VERSION 5.7 ;
  NOWIREEXTENSIONATPIN ON ;
  DIVIDERCHAR "/" ;
  BUSBITCHARS "[]" ;
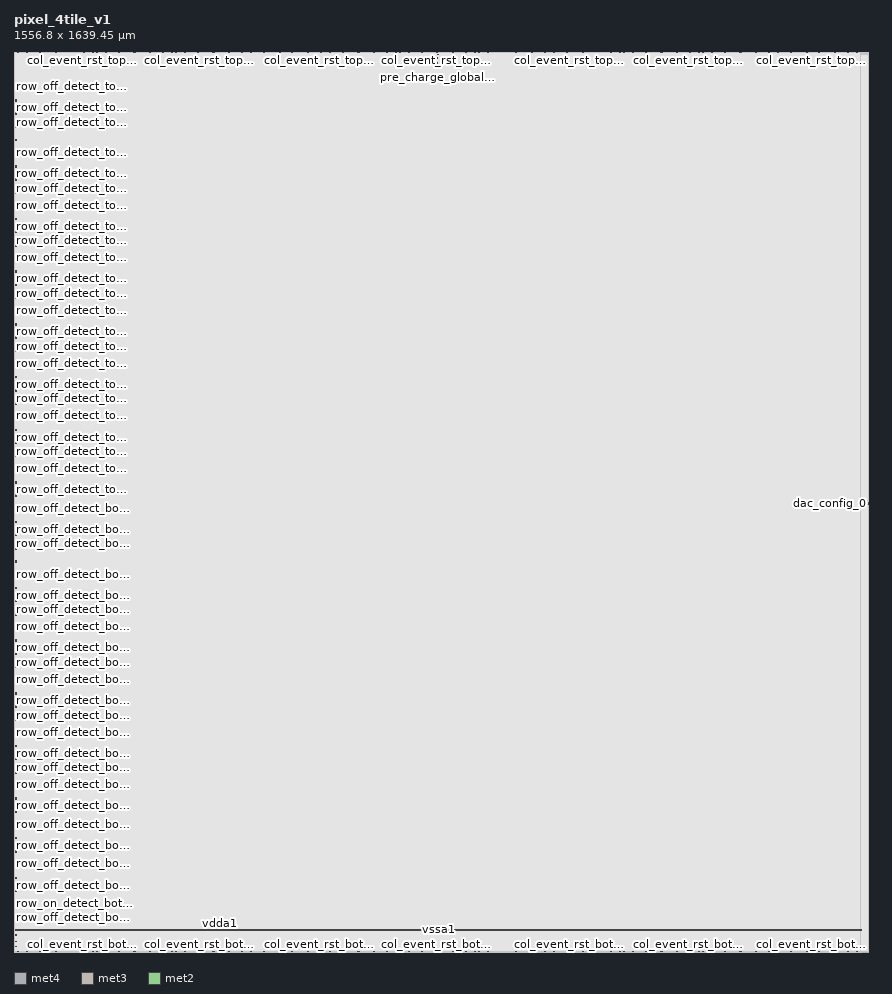
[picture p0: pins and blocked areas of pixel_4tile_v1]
MACRO pixel_4tile_v1
  CLASS BLOCK ;
  FOREIGN pixel_4tile_v1 ;
  ORIGIN 0.775 0.005 ;
  SIZE 1556.795 BY 1639.450 ;
  PIN vdda1
    ANTENNADIFFAREA 30146.603516 ;
    PORT
      LAYER met4 ;
        RECT 368.795 50.390 380.585 52.050 ;
    END
  END vdda1
  PIN dac_config_3
    ANTENNAGATEAREA 1228.799927 ;
    PORT
      LAYER met3 ;
        RECT 1555.525 820.220 1556.020 821.220 ;
    END
  END dac_config_3
  PIN dac_config_5
    ANTENNAGATEAREA 10321.919922 ;
    PORT
      LAYER met3 ;
        RECT 1555.525 821.715 1556.020 822.720 ;
    END
  END dac_config_5
  PIN dac_config_1
    ANTENNAGATEAREA 36864.000000 ;
    PORT
      LAYER met3 ;
        RECT 1555.525 817.220 1556.020 818.220 ;
    END
  END dac_config_1
  PIN dac_config_4
    ANTENNAGATEAREA 10321.919922 ;
    PORT
      LAYER met3 ;
        RECT 1555.525 818.720 1556.020 819.720 ;
    END
  END dac_config_4
  PIN dac_config_0
    ANTENNAGATEAREA 36576.000000 ;
    PORT
      LAYER met3 ;
        RECT 1555.525 815.720 1556.020 816.720 ;
    END
  END dac_config_0
  PIN array_col_bot_left<19>
    ANTENNADIFFAREA 0.870000 ;
    PORT
      LAYER met3 ;
        RECT 534.245 0.125 535.015 0.425 ;
    END
  END array_col_bot_left<19>
  PIN array_col_bot_left<18>
    ANTENNADIFFAREA 0.870000 ;
    PORT
      LAYER met3 ;
        RECT 550.365 0.125 551.135 0.425 ;
    END
  END array_col_bot_left<18>
  PIN array_col_bot_left<17>
    ANTENNADIFFAREA 0.870000 ;
    PORT
      LAYER met3 ;
        RECT 558.245 0.125 559.015 0.425 ;
    END
  END array_col_bot_left<17>
  PIN array_col_bot_left<16>
    ANTENNADIFFAREA 0.870000 ;
    PORT
      LAYER met3 ;
        RECT 574.365 0.125 575.135 0.425 ;
    END
  END array_col_bot_left<16>
  PIN array_col_bot_left<15>
    ANTENNADIFFAREA 0.870000 ;
    PORT
      LAYER met3 ;
        RECT 582.245 0.125 583.015 0.425 ;
    END
  END array_col_bot_left<15>
  PIN array_col_bot_left<6>
    ANTENNADIFFAREA 0.870000 ;
    PORT
      LAYER met3 ;
        RECT 694.365 0.125 695.135 0.425 ;
    END
  END array_col_bot_left<6>
  PIN array_col_top_right<15>
    ANTENNADIFFAREA 0.870000 ;
    PORT
      LAYER met3 ;
        RECT 1350.245 1638.015 1351.015 1638.315 ;
    END
  END array_col_top_right<15>
  PIN array_col_top_right<25>
    ANTENNADIFFAREA 0.870000 ;
    PORT
      LAYER met3 ;
        RECT 1230.245 1638.015 1231.015 1638.315 ;
    END
  END array_col_top_right<25>
  PIN array_col_top_right<14>
    ANTENNADIFFAREA 0.870000 ;
    PORT
      LAYER met3 ;
        RECT 1366.365 1638.015 1367.135 1638.315 ;
    END
  END array_col_top_right<14>
  PIN array_col_top_right<27>
    ANTENNADIFFAREA 0.870000 ;
    PORT
      LAYER met3 ;
        RECT 1206.245 1638.015 1207.015 1638.315 ;
    END
  END array_col_top_right<27>
  PIN array_col_top_right<21>
    ANTENNADIFFAREA 0.870000 ;
    PORT
      LAYER met3 ;
        RECT 1278.245 1638.015 1279.015 1638.315 ;
    END
  END array_col_top_right<21>
  PIN array_col_bot_left<63>
    ANTENNADIFFAREA 0.870000 ;
    PORT
      LAYER met3 ;
        RECT 6.245 0.125 7.015 0.425 ;
    END
  END array_col_bot_left<63>
  PIN array_col_bot_left<1>
    ANTENNADIFFAREA 0.870000 ;
    PORT
      LAYER met3 ;
        RECT 750.245 0.125 751.015 0.425 ;
    END
  END array_col_bot_left<1>
  PIN array_col_bot_left<4>
    ANTENNADIFFAREA 0.870000 ;
    PORT
      LAYER met3 ;
        RECT 718.365 0.125 719.135 0.425 ;
    END
  END array_col_bot_left<4>
  PIN col_event_rst_bot_left<53>
    ANTENNAGATEAREA 4.032000 ;
    PORT
      LAYER met3 ;
        RECT 123.500 0.245 123.800 0.545 ;
    END
  END col_event_rst_bot_left<53>
  PIN array_col_bot_right<50>
    ANTENNADIFFAREA 0.870000 ;
    PORT
      LAYER met3 ;
        RECT 934.365 0.125 935.135 0.425 ;
    END
  END array_col_bot_right<50>
  PIN col_event_rst_bot_left<47>
    ANTENNAGATEAREA 4.032000 ;
    PORT
      LAYER met3 ;
        RECT 195.500 0.245 195.800 0.545 ;
    END
  END col_event_rst_bot_left<47>
  PIN col_event_rst_top_left<62>
    ANTENNAGATEAREA 4.032000 ;
    PORT
      LAYER met3 ;
        RECT 25.595 1637.895 25.895 1638.195 ;
    END
  END col_event_rst_top_left<62>
  PIN array_col_bot_left<0>
    ANTENNADIFFAREA 0.870000 ;
    PORT
      LAYER met3 ;
        RECT 766.365 0.125 767.135 0.425 ;
    END
  END array_col_bot_left<0>
  PIN col_event_rst_bot_left<5>
    ANTENNAGATEAREA 4.032000 ;
    PORT
      LAYER met3 ;
        RECT 699.500 0.245 699.800 0.545 ;
    END
  END col_event_rst_bot_left<5>
  PIN col_event_rst_bot_left<6>
    ANTENNAGATEAREA 4.032000 ;
    PORT
      LAYER met3 ;
        RECT 697.595 0.245 697.895 0.545 ;
    END
  END col_event_rst_bot_left<6>
  PIN col_event_rst_bot_left<9>
    ANTENNAGATEAREA 4.032000 ;
    PORT
      LAYER met3 ;
        RECT 651.500 0.245 651.800 0.545 ;
    END
  END col_event_rst_bot_left<9>
  PIN col_event_rst_bot_left<10>
    ANTENNAGATEAREA 4.032000 ;
    PORT
      LAYER met3 ;
        RECT 649.595 0.245 649.895 0.545 ;
    END
  END col_event_rst_bot_left<10>
  PIN col_event_rst_bot_left<13>
    ANTENNAGATEAREA 4.032000 ;
    PORT
      LAYER met3 ;
        RECT 603.500 0.245 603.800 0.545 ;
    END
  END col_event_rst_bot_left<13>
  PIN array_col_bot_left<50>
    ANTENNADIFFAREA 0.870000 ;
    PORT
      LAYER met3 ;
        RECT 166.365 0.125 167.135 0.425 ;
    END
  END array_col_bot_left<50>
  PIN col_event_rst_bot_left<14>
    ANTENNAGATEAREA 4.032000 ;
    PORT
      LAYER met3 ;
        RECT 601.595 0.245 601.895 0.545 ;
    END
  END col_event_rst_bot_left<14>
  PIN col_event_rst_bot_left<15>
    ANTENNAGATEAREA 4.032000 ;
    PORT
      LAYER met3 ;
        RECT 579.500 0.245 579.800 0.545 ;
    END
  END col_event_rst_bot_left<15>
  PIN col_event_rst_bot_left<18>
    ANTENNAGATEAREA 4.032000 ;
    PORT
      LAYER met3 ;
        RECT 553.595 0.245 553.895 0.545 ;
    END
  END col_event_rst_bot_left<18>
  PIN col_event_rst_bot_left<19>
    ANTENNAGATEAREA 4.032000 ;
    PORT
      LAYER met3 ;
        RECT 531.500 0.245 531.800 0.545 ;
    END
  END col_event_rst_bot_left<19>
  PIN col_event_rst_bot_left<22>
    ANTENNAGATEAREA 4.032000 ;
    PORT
      LAYER met3 ;
        RECT 505.595 0.245 505.895 0.545 ;
    END
  END col_event_rst_bot_left<22>
  PIN col_event_rst_top_right<47>
    ANTENNAGATEAREA 4.032000 ;
    PORT
      LAYER met3 ;
        RECT 963.500 1637.895 963.800 1638.195 ;
    END
  END col_event_rst_top_right<47>
  PIN col_event_rst_top_right<49>
    ANTENNAGATEAREA 4.032000 ;
    PORT
      LAYER met3 ;
        RECT 939.500 1637.895 939.800 1638.195 ;
    END
  END col_event_rst_top_right<49>
  PIN col_event_rst_bot_left<24>
    ANTENNAGATEAREA 4.032000 ;
    PORT
      LAYER met3 ;
        RECT 481.595 0.245 481.895 0.545 ;
    END
  END col_event_rst_bot_left<24>
  PIN col_event_rst_bot_left<27>
    ANTENNAGATEAREA 4.032000 ;
    PORT
      LAYER met3 ;
        RECT 435.500 0.245 435.800 0.545 ;
    END
  END col_event_rst_bot_left<27>
  PIN col_event_rst_bot_left<28>
    ANTENNAGATEAREA 4.032000 ;
    PORT
      LAYER met3 ;
        RECT 433.595 0.245 433.895 0.545 ;
    END
  END col_event_rst_bot_left<28>
  PIN array_col_bot_left<47>
    ANTENNADIFFAREA 0.870000 ;
    PORT
      LAYER met3 ;
        RECT 198.245 0.125 199.015 0.425 ;
    END
  END array_col_bot_left<47>
  PIN col_event_rst_bot_left<31>
    ANTENNAGATEAREA 4.032000 ;
    PORT
      LAYER met3 ;
        RECT 387.500 0.245 387.800 0.545 ;
    END
  END col_event_rst_bot_left<31>
  PIN col_event_rst_bot_left<33>
    ANTENNAGATEAREA 4.032000 ;
    PORT
      LAYER met3 ;
        RECT 363.500 0.245 363.800 0.545 ;
    END
  END col_event_rst_bot_left<33>
  PIN col_event_rst_top_right<50>
    ANTENNAGATEAREA 4.032000 ;
    PORT
      LAYER met3 ;
        RECT 937.595 1637.895 937.895 1638.195 ;
    END
  END col_event_rst_top_right<50>
  PIN col_event_rst_bot_left<36>
    ANTENNAGATEAREA 4.032000 ;
    PORT
      LAYER met3 ;
        RECT 337.595 0.245 337.895 0.545 ;
    END
  END col_event_rst_bot_left<36>
  PIN col_event_rst_bot_left<37>
    ANTENNAGATEAREA 4.032000 ;
    PORT
      LAYER met3 ;
        RECT 315.500 0.245 315.800 0.545 ;
    END
  END col_event_rst_bot_left<37>
  PIN col_event_rst_bot_left<39>
    ANTENNAGATEAREA 4.032000 ;
    PORT
      LAYER met3 ;
        RECT 291.500 0.245 291.800 0.545 ;
    END
  END col_event_rst_bot_left<39>
  PIN col_event_rst_bot_left<40>
    ANTENNAGATEAREA 4.032000 ;
    PORT
      LAYER met3 ;
        RECT 289.595 0.245 289.895 0.545 ;
    END
  END col_event_rst_bot_left<40>
  PIN col_event_rst_bot_left<42>
    ANTENNAGATEAREA 4.032000 ;
    PORT
      LAYER met3 ;
        RECT 265.595 0.245 265.895 0.545 ;
    END
  END col_event_rst_bot_left<42>
  PIN col_event_rst_bot_left<43>
    ANTENNAGATEAREA 4.032000 ;
    PORT
      LAYER met3 ;
        RECT 243.500 0.245 243.800 0.545 ;
    END
  END col_event_rst_bot_left<43>
  PIN col_event_rst_top_right<51>
    ANTENNAGATEAREA 4.032000 ;
    PORT
      LAYER met3 ;
        RECT 915.500 1637.895 915.800 1638.195 ;
    END
  END col_event_rst_top_right<51>
  PIN col_event_rst_top_left<58>
    ANTENNAGATEAREA 4.032000 ;
    PORT
      LAYER met3 ;
        RECT 73.595 1637.895 73.895 1638.195 ;
    END
  END col_event_rst_top_left<58>
  PIN array_col_top_right<26>
    ANTENNADIFFAREA 0.870000 ;
    PORT
      LAYER met3 ;
        RECT 1222.365 1638.015 1223.135 1638.315 ;
    END
  END array_col_top_right<26>
  PIN col_event_rst_top_right<43>
    ANTENNAGATEAREA 4.032000 ;
    PORT
      LAYER met3 ;
        RECT 1011.500 1637.895 1011.800 1638.195 ;
    END
  END col_event_rst_top_right<43>
  PIN array_col_top_right<1>
    ANTENNADIFFAREA 0.870000 ;
    PORT
      LAYER met3 ;
        RECT 1518.245 1638.015 1519.015 1638.315 ;
    END
  END array_col_top_right<1>
  PIN array_col_top_right<2>
    ANTENNADIFFAREA 0.870000 ;
    PORT
      LAYER met3 ;
        RECT 1510.365 1638.015 1511.135 1638.315 ;
    END
  END array_col_top_right<2>
  PIN col_event_rst_top_left<44>
    ANTENNAGATEAREA 4.032000 ;
    PORT
      LAYER met3 ;
        RECT 241.595 1637.895 241.895 1638.195 ;
    END
  END col_event_rst_top_left<44>
  PIN array_col_top_right<12>
    ANTENNADIFFAREA 0.870000 ;
    PORT
      LAYER met3 ;
        RECT 1390.365 1638.015 1391.135 1638.315 ;
    END
  END array_col_top_right<12>
  PIN col_event_rst_bot_left<49>
    ANTENNAGATEAREA 4.032000 ;
    PORT
      LAYER met3 ;
        RECT 171.500 0.245 171.800 0.545 ;
    END
  END col_event_rst_bot_left<49>
  PIN col_event_rst_bot_left<48>
    ANTENNAGATEAREA 4.032000 ;
    PORT
      LAYER met3 ;
        RECT 193.595 0.245 193.895 0.545 ;
    END
  END col_event_rst_bot_left<48>
  PIN array_col_top_right<30>
    ANTENNADIFFAREA 0.870000 ;
    PORT
      LAYER met3 ;
        RECT 1174.365 1638.015 1175.135 1638.315 ;
    END
  END array_col_top_right<30>
  PIN array_col_top_right<29>
    ANTENNADIFFAREA 0.870000 ;
    PORT
      LAYER met3 ;
        RECT 1182.245 1638.015 1183.015 1638.315 ;
    END
  END array_col_top_right<29>
  PIN array_col_top_right<28>
    ANTENNADIFFAREA 0.870000 ;
    PORT
      LAYER met3 ;
        RECT 1198.365 1638.015 1199.135 1638.315 ;
    END
  END array_col_top_right<28>
  PIN array_col_bot_left<2>
    ANTENNADIFFAREA 0.870000 ;
    PORT
      LAYER met3 ;
        RECT 742.365 0.125 743.135 0.425 ;
    END
  END array_col_bot_left<2>
  PIN array_col_bot_left<3>
    ANTENNADIFFAREA 0.870000 ;
    PORT
      LAYER met3 ;
        RECT 726.245 0.125 727.015 0.425 ;
    END
  END array_col_bot_left<3>
  PIN col_event_rst_top_left<50>
    ANTENNAGATEAREA 4.032000 ;
    PORT
      LAYER met3 ;
        RECT 169.595 1637.895 169.895 1638.195 ;
    END
  END col_event_rst_top_left<50>
  PIN array_col_bot_left<5>
    ANTENNADIFFAREA 0.870000 ;
    PORT
      LAYER met3 ;
        RECT 702.245 0.125 703.015 0.425 ;
    END
  END array_col_bot_left<5>
  PIN array_col_bot_left<46>
    ANTENNADIFFAREA 0.870000 ;
    PORT
      LAYER met3 ;
        RECT 214.365 0.125 215.135 0.425 ;
    END
  END array_col_bot_left<46>
  PIN col_event_rst_top_left<61>
    ANTENNAGATEAREA 4.032000 ;
    PORT
      LAYER met3 ;
        RECT 27.500 1637.895 27.800 1638.195 ;
    END
  END col_event_rst_top_left<61>
  PIN array_col_top_right<16>
    ANTENNADIFFAREA 0.870000 ;
    PORT
      LAYER met3 ;
        RECT 1342.365 1638.015 1343.135 1638.315 ;
    END
  END array_col_top_right<16>
  PIN col_event_rst_bot_left<2>
    ANTENNAGATEAREA 4.032000 ;
    PORT
      LAYER met3 ;
        RECT 745.595 0.245 745.895 0.545 ;
    END
  END col_event_rst_bot_left<2>
  PIN col_event_rst_bot_left<7>
    ANTENNAGATEAREA 4.032000 ;
    PORT
      LAYER met3 ;
        RECT 675.500 0.245 675.800 0.545 ;
    END
  END col_event_rst_bot_left<7>
  PIN col_event_rst_bot_left<8>
    ANTENNAGATEAREA 4.032000 ;
    PORT
      LAYER met3 ;
        RECT 673.595 0.245 673.895 0.545 ;
    END
  END col_event_rst_bot_left<8>
  PIN col_event_rst_bot_left<11>
    ANTENNAGATEAREA 4.032000 ;
    PORT
      LAYER met3 ;
        RECT 627.500 0.245 627.800 0.545 ;
    END
  END col_event_rst_bot_left<11>
  PIN col_event_rst_bot_left<12>
    ANTENNAGATEAREA 4.032000 ;
    PORT
      LAYER met3 ;
        RECT 625.595 0.245 625.895 0.545 ;
    END
  END col_event_rst_bot_left<12>
  PIN col_event_rst_bot_left<3>
    ANTENNAGATEAREA 4.032000 ;
    PORT
      LAYER met3 ;
        RECT 723.500 0.245 723.800 0.545 ;
    END
  END col_event_rst_bot_left<3>
  PIN col_event_rst_top_right<48>
    ANTENNAGATEAREA 4.032000 ;
    PORT
      LAYER met3 ;
        RECT 961.595 1637.895 961.895 1638.195 ;
    END
  END col_event_rst_top_right<48>
  PIN col_event_rst_bot_left<16>
    ANTENNAGATEAREA 4.032000 ;
    PORT
      LAYER met3 ;
        RECT 577.595 0.245 577.895 0.545 ;
    END
  END col_event_rst_bot_left<16>
  PIN col_event_rst_bot_left<17>
    ANTENNAGATEAREA 4.032000 ;
    PORT
      LAYER met3 ;
        RECT 555.500 0.245 555.800 0.545 ;
    END
  END col_event_rst_bot_left<17>
  PIN col_event_rst_bot_left<20>
    ANTENNAGATEAREA 4.032000 ;
    PORT
      LAYER met3 ;
        RECT 529.595 0.245 529.895 0.545 ;
    END
  END col_event_rst_bot_left<20>
  PIN col_event_rst_bot_left<21>
    ANTENNAGATEAREA 4.032000 ;
    PORT
      LAYER met3 ;
        RECT 507.500 0.245 507.800 0.545 ;
    END
  END col_event_rst_bot_left<21>
  PIN col_event_rst_top_left<55>
    ANTENNAGATEAREA 4.032000 ;
    PORT
      LAYER met3 ;
        RECT 99.500 1637.895 99.800 1638.195 ;
    END
  END col_event_rst_top_left<55>
  PIN col_event_rst_bot_left<23>
    ANTENNAGATEAREA 4.032000 ;
    PORT
      LAYER met3 ;
        RECT 483.500 0.245 483.800 0.545 ;
    END
  END col_event_rst_bot_left<23>
  PIN col_event_rst_bot_left<25>
    ANTENNAGATEAREA 4.032000 ;
    PORT
      LAYER met3 ;
        RECT 459.500 0.245 459.800 0.545 ;
    END
  END col_event_rst_bot_left<25>
  PIN col_event_rst_bot_left<26>
    ANTENNAGATEAREA 4.032000 ;
    PORT
      LAYER met3 ;
        RECT 457.595 0.245 457.895 0.545 ;
    END
  END col_event_rst_bot_left<26>
  PIN col_event_rst_bot_left<29>
    ANTENNAGATEAREA 4.032000 ;
    PORT
      LAYER met3 ;
        RECT 411.500 0.245 411.800 0.545 ;
    END
  END col_event_rst_bot_left<29>
  PIN col_event_rst_bot_left<30>
    ANTENNAGATEAREA 4.032000 ;
    PORT
      LAYER met3 ;
        RECT 409.595 0.245 409.895 0.545 ;
    END
  END col_event_rst_bot_left<30>
  PIN col_event_rst_top_left<56>
    ANTENNAGATEAREA 4.032000 ;
    PORT
      LAYER met3 ;
        RECT 97.595 1637.895 97.895 1638.195 ;
    END
  END col_event_rst_top_left<56>
  PIN col_event_rst_bot_left<32>
    ANTENNAGATEAREA 4.032000 ;
    PORT
      LAYER met3 ;
        RECT 385.595 0.245 385.895 0.545 ;
    END
  END col_event_rst_bot_left<32>
  PIN col_event_rst_bot_left<34>
    ANTENNAGATEAREA 4.032000 ;
    PORT
      LAYER met3 ;
        RECT 361.595 0.245 361.895 0.545 ;
    END
  END col_event_rst_bot_left<34>
  PIN col_event_rst_bot_left<35>
    ANTENNAGATEAREA 4.032000 ;
    PORT
      LAYER met3 ;
        RECT 339.500 0.245 339.800 0.545 ;
    END
  END col_event_rst_bot_left<35>
  PIN col_event_rst_bot_left<38>
    ANTENNAGATEAREA 4.032000 ;
    PORT
      LAYER met3 ;
        RECT 313.595 0.245 313.895 0.545 ;
    END
  END col_event_rst_bot_left<38>
  PIN col_event_rst_bot_left<4>
    ANTENNAGATEAREA 4.032000 ;
    PORT
      LAYER met3 ;
        RECT 721.595 0.245 721.895 0.545 ;
    END
  END col_event_rst_bot_left<4>
  PIN col_event_rst_top_left<57>
    ANTENNAGATEAREA 4.032000 ;
    PORT
      LAYER met3 ;
        RECT 75.500 1637.895 75.800 1638.195 ;
    END
  END col_event_rst_top_left<57>
  PIN col_event_rst_bot_left<41>
    ANTENNAGATEAREA 4.032000 ;
    PORT
      LAYER met3 ;
        RECT 267.500 0.245 267.800 0.545 ;
    END
  END col_event_rst_bot_left<41>
  PIN array_col_bot_right<51>
    ANTENNADIFFAREA 0.870000 ;
    PORT
      LAYER met3 ;
        RECT 918.245 0.125 919.015 0.425 ;
    END
  END array_col_bot_right<51>
  PIN col_event_rst_top_right<55>
    ANTENNAGATEAREA 4.032000 ;
    PORT
      LAYER met3 ;
        RECT 867.500 1637.895 867.800 1638.195 ;
    END
  END col_event_rst_top_right<55>
  PIN col_event_rst_top_right<54>
    ANTENNAGATEAREA 4.032000 ;
    PORT
      LAYER met3 ;
        RECT 889.595 1637.895 889.895 1638.195 ;
    END
  END col_event_rst_top_right<54>
  PIN col_event_rst_top_right<42>
    ANTENNAGATEAREA 4.032000 ;
    PORT
      LAYER met3 ;
        RECT 1033.595 1637.895 1033.895 1638.195 ;
    END
  END col_event_rst_top_right<42>
  PIN col_event_rst_top_right<41>
    ANTENNAGATEAREA 4.032000 ;
    PORT
      LAYER met3 ;
        RECT 1035.500 1637.895 1035.800 1638.195 ;
    END
  END col_event_rst_top_right<41>
  PIN col_event_rst_top_right<40>
    ANTENNAGATEAREA 4.032000 ;
    PORT
      LAYER met3 ;
        RECT 1057.595 1637.895 1057.895 1638.195 ;
    END
  END col_event_rst_top_right<40>
  PIN col_event_rst_top_right<39>
    ANTENNAGATEAREA 4.032000 ;
    PORT
      LAYER met3 ;
        RECT 1059.500 1637.895 1059.800 1638.195 ;
    END
  END col_event_rst_top_right<39>
  PIN col_event_rst_top_right<53>
    ANTENNAGATEAREA 4.032000 ;
    PORT
      LAYER met3 ;
        RECT 891.500 1637.895 891.800 1638.195 ;
    END
  END col_event_rst_top_right<53>
  PIN col_event_rst_top_right<38>
    ANTENNAGATEAREA 4.032000 ;
    PORT
      LAYER met3 ;
        RECT 1081.595 1637.895 1081.895 1638.195 ;
    END
  END col_event_rst_top_right<38>
  PIN col_event_rst_top_right<37>
    ANTENNAGATEAREA 4.032000 ;
    PORT
      LAYER met3 ;
        RECT 1083.500 1637.895 1083.800 1638.195 ;
    END
  END col_event_rst_top_right<37>
  PIN col_event_rst_top_right<36>
    ANTENNAGATEAREA 4.032000 ;
    PORT
      LAYER met3 ;
        RECT 1105.595 1637.895 1105.895 1638.195 ;
    END
  END col_event_rst_top_right<36>
  PIN col_event_rst_top_right<35>
    ANTENNAGATEAREA 4.032000 ;
    PORT
      LAYER met3 ;
        RECT 1107.500 1637.895 1107.800 1638.195 ;
    END
  END col_event_rst_top_right<35>
  PIN col_event_rst_top_right<34>
    ANTENNAGATEAREA 4.032000 ;
    PORT
      LAYER met3 ;
        RECT 1129.595 1637.895 1129.895 1638.195 ;
    END
  END col_event_rst_top_right<34>
  PIN col_event_rst_top_right<33>
    ANTENNAGATEAREA 4.032000 ;
    PORT
      LAYER met3 ;
        RECT 1131.500 1637.895 1131.800 1638.195 ;
    END
  END col_event_rst_top_right<33>
  PIN array_col_bot_right<55>
    ANTENNADIFFAREA 0.870000 ;
    PORT
      LAYER met3 ;
        RECT 870.245 0.125 871.015 0.425 ;
    END
  END array_col_bot_right<55>
  PIN col_event_rst_top_right<32>
    ANTENNAGATEAREA 4.032000 ;
    PORT
      LAYER met3 ;
        RECT 1153.595 1637.895 1153.895 1638.195 ;
    END
  END col_event_rst_top_right<32>
  PIN array_col_bot_right<63>
    ANTENNADIFFAREA 0.870000 ;
    PORT
      LAYER met3 ;
        RECT 774.245 0.125 775.015 0.425 ;
    END
  END array_col_bot_right<63>
  PIN array_col_bot_right<0>
    ANTENNADIFFAREA 0.870000 ;
    PORT
      LAYER met3 ;
        RECT 1534.365 0.125 1535.135 0.425 ;
    END
  END array_col_bot_right<0>
  PIN array_col_top_right<3>
    ANTENNADIFFAREA 0.870000 ;
    PORT
      LAYER met3 ;
        RECT 1494.245 1638.015 1495.015 1638.315 ;
    END
  END array_col_top_right<3>
  PIN array_col_top_right<4>
    ANTENNADIFFAREA 0.870000 ;
    PORT
      LAYER met3 ;
        RECT 1486.365 1638.015 1487.135 1638.315 ;
    END
  END array_col_top_right<4>
  PIN array_col_top_right<13>
    ANTENNADIFFAREA 0.870000 ;
    PORT
      LAYER met3 ;
        RECT 1374.245 1638.015 1375.015 1638.315 ;
    END
  END array_col_top_right<13>
  PIN col_event_rst_top_right<31>
    ANTENNAGATEAREA 4.032000 ;
    PORT
      LAYER met3 ;
        RECT 1155.500 1637.895 1155.800 1638.195 ;
    END
  END col_event_rst_top_right<31>
  PIN col_event_rst_top_right<30>
    ANTENNAGATEAREA 4.032000 ;
    PORT
      LAYER met3 ;
        RECT 1177.595 1637.895 1177.895 1638.195 ;
    END
  END col_event_rst_top_right<30>
  PIN col_event_rst_top_right<52>
    ANTENNAGATEAREA 4.032000 ;
    PORT
      LAYER met3 ;
        RECT 913.595 1637.895 913.895 1638.195 ;
    END
  END col_event_rst_top_right<52>
  PIN col_event_rst_top_right<29>
    ANTENNAGATEAREA 4.032000 ;
    PORT
      LAYER met3 ;
        RECT 1179.500 1637.895 1179.800 1638.195 ;
    END
  END col_event_rst_top_right<29>
  PIN col_event_rst_top_right<28>
    ANTENNAGATEAREA 4.032000 ;
    PORT
      LAYER met3 ;
        RECT 1201.595 1637.895 1201.895 1638.195 ;
    END
  END col_event_rst_top_right<28>
  PIN col_event_rst_top_right<27>
    ANTENNAGATEAREA 4.032000 ;
    PORT
      LAYER met3 ;
        RECT 1203.500 1637.895 1203.800 1638.195 ;
    END
  END col_event_rst_top_right<27>
  PIN col_event_rst_top_right<26>
    ANTENNAGATEAREA 4.032000 ;
    PORT
      LAYER met3 ;
        RECT 1225.595 1637.895 1225.895 1638.195 ;
    END
  END col_event_rst_top_right<26>
  PIN col_event_rst_top_right<25>
    ANTENNAGATEAREA 4.032000 ;
    PORT
      LAYER met3 ;
        RECT 1227.500 1637.895 1227.800 1638.195 ;
    END
  END col_event_rst_top_right<25>
  PIN col_event_rst_top_right<24>
    ANTENNAGATEAREA 4.032000 ;
    PORT
      LAYER met3 ;
        RECT 1249.595 1637.895 1249.895 1638.195 ;
    END
  END col_event_rst_top_right<24>
  PIN col_event_rst_top_right<23>
    ANTENNAGATEAREA 4.032000 ;
    PORT
      LAYER met3 ;
        RECT 1251.500 1637.895 1251.800 1638.195 ;
    END
  END col_event_rst_top_right<23>
  PIN array_col_bot_right<54>
    ANTENNADIFFAREA 0.870000 ;
    PORT
      LAYER met3 ;
        RECT 886.365 0.125 887.135 0.425 ;
    END
  END array_col_bot_right<54>
  PIN col_event_rst_top_right<22>
    ANTENNAGATEAREA 4.032000 ;
    PORT
      LAYER met3 ;
        RECT 1273.595 1637.895 1273.895 1638.195 ;
    END
  END col_event_rst_top_right<22>
  PIN col_event_rst_top_right<21>
    ANTENNAGATEAREA 4.032000 ;
    PORT
      LAYER met3 ;
        RECT 1275.500 1637.895 1275.800 1638.195 ;
    END
  END col_event_rst_top_right<21>
  PIN col_event_rst_top_left<42>
    ANTENNAGATEAREA 4.032000 ;
    PORT
      LAYER met3 ;
        RECT 265.595 1637.895 265.895 1638.195 ;
    END
  END col_event_rst_top_left<42>
  PIN col_event_rst_top_right<20>
    ANTENNAGATEAREA 4.032000 ;
    PORT
      LAYER met3 ;
        RECT 1297.595 1637.895 1297.895 1638.195 ;
    END
  END col_event_rst_top_right<20>
  PIN col_event_rst_top_right<19>
    ANTENNAGATEAREA 4.032000 ;
    PORT
      LAYER met3 ;
        RECT 1299.500 1637.895 1299.800 1638.195 ;
    END
  END col_event_rst_top_right<19>
  PIN col_event_rst_top_right<18>
    ANTENNAGATEAREA 4.032000 ;
    PORT
      LAYER met3 ;
        RECT 1321.595 1637.895 1321.895 1638.195 ;
    END
  END col_event_rst_top_right<18>
  PIN col_event_rst_top_right<17>
    ANTENNAGATEAREA 4.032000 ;
    PORT
      LAYER met3 ;
        RECT 1323.500 1637.895 1323.800 1638.195 ;
    END
  END col_event_rst_top_right<17>
  PIN col_event_rst_top_right<16>
    ANTENNAGATEAREA 4.032000 ;
    PORT
      LAYER met3 ;
        RECT 1345.595 1637.895 1345.895 1638.195 ;
    END
  END col_event_rst_top_right<16>
  PIN col_event_rst_top_right<15>
    ANTENNAGATEAREA 4.032000 ;
    PORT
      LAYER met3 ;
        RECT 1347.500 1637.895 1347.800 1638.195 ;
    END
  END col_event_rst_top_right<15>
  PIN col_event_rst_top_right<14>
    ANTENNAGATEAREA 4.032000 ;
    PORT
      LAYER met3 ;
        RECT 1369.595 1637.895 1369.895 1638.195 ;
    END
  END col_event_rst_top_right<14>
  PIN col_event_rst_top_right<13>
    ANTENNAGATEAREA 4.032000 ;
    PORT
      LAYER met3 ;
        RECT 1371.500 1637.895 1371.800 1638.195 ;
    END
  END col_event_rst_top_right<13>
  PIN array_col_bot_right<53>
    ANTENNADIFFAREA 0.870000 ;
    PORT
      LAYER met3 ;
        RECT 894.245 0.125 895.015 0.425 ;
    END
  END array_col_bot_right<53>
  PIN col_event_rst_top_right<12>
    ANTENNAGATEAREA 4.032000 ;
    PORT
      LAYER met3 ;
        RECT 1393.595 1637.895 1393.895 1638.195 ;
    END
  END col_event_rst_top_right<12>
  PIN col_event_rst_bot_left<46>
    ANTENNAGATEAREA 4.032000 ;
    PORT
      LAYER met3 ;
        RECT 217.595 0.245 217.895 0.545 ;
    END
  END col_event_rst_bot_left<46>
  PIN col_event_rst_top_right<11>
    ANTENNAGATEAREA 4.032000 ;
    PORT
      LAYER met3 ;
        RECT 1395.500 1637.895 1395.800 1638.195 ;
    END
  END col_event_rst_top_right<11>
  PIN col_event_rst_top_right<10>
    ANTENNAGATEAREA 4.032000 ;
    PORT
      LAYER met3 ;
        RECT 1417.595 1637.895 1417.895 1638.195 ;
    END
  END col_event_rst_top_right<10>
  PIN col_event_rst_top_right<9>
    ANTENNAGATEAREA 4.032000 ;
    PORT
      LAYER met3 ;
        RECT 1419.500 1637.895 1419.800 1638.195 ;
    END
  END col_event_rst_top_right<9>
  PIN col_event_rst_top_right<8>
    ANTENNAGATEAREA 4.032000 ;
    PORT
      LAYER met3 ;
        RECT 1441.595 1637.895 1441.895 1638.195 ;
    END
  END col_event_rst_top_right<8>
  PIN col_event_rst_top_right<7>
    ANTENNAGATEAREA 4.032000 ;
    PORT
      LAYER met3 ;
        RECT 1443.500 1637.895 1443.800 1638.195 ;
    END
  END col_event_rst_top_right<7>
  PIN col_event_rst_top_right<6>
    ANTENNAGATEAREA 4.032000 ;
    PORT
      LAYER met3 ;
        RECT 1465.595 1637.895 1465.895 1638.195 ;
    END
  END col_event_rst_top_right<6>
  PIN col_event_rst_top_right<5>
    ANTENNAGATEAREA 4.032000 ;
    PORT
      LAYER met3 ;
        RECT 1467.500 1637.895 1467.800 1638.195 ;
    END
  END col_event_rst_top_right<5>
  PIN col_event_rst_top_right<4>
    ANTENNAGATEAREA 4.032000 ;
    PORT
      LAYER met3 ;
        RECT 1489.595 1637.895 1489.895 1638.195 ;
    END
  END col_event_rst_top_right<4>
  PIN col_event_rst_top_right<3>
    ANTENNAGATEAREA 4.032000 ;
    PORT
      LAYER met3 ;
        RECT 1491.500 1637.895 1491.800 1638.195 ;
    END
  END col_event_rst_top_right<3>
  PIN array_col_bot_right<52>
    ANTENNADIFFAREA 0.870000 ;
    PORT
      LAYER met3 ;
        RECT 910.365 0.125 911.135 0.425 ;
    END
  END array_col_bot_right<52>
  PIN col_event_rst_bot_left<45>
    ANTENNAGATEAREA 4.032000 ;
    PORT
      LAYER met3 ;
        RECT 219.500 0.245 219.800 0.545 ;
    END
  END col_event_rst_bot_left<45>
  PIN col_event_rst_top_right<2>
    ANTENNAGATEAREA 4.032000 ;
    PORT
      LAYER met3 ;
        RECT 1513.595 1637.895 1513.895 1638.195 ;
    END
  END col_event_rst_top_right<2>
  PIN col_event_rst_top_right<1>
    ANTENNAGATEAREA 4.032000 ;
    PORT
      LAYER met3 ;
        RECT 1515.500 1637.895 1515.800 1638.195 ;
    END
  END col_event_rst_top_right<1>
  PIN col_event_rst_top_right<63>
    ANTENNAGATEAREA 4.032000 ;
    PORT
      LAYER met3 ;
        RECT 771.500 1635.225 771.800 1635.525 ;
    END
  END col_event_rst_top_right<63>
  PIN col_event_rst_top_right<0>
    ANTENNAGATEAREA 4.032000 ;
    PORT
      LAYER met3 ;
        RECT 1537.595 1637.895 1537.895 1638.195 ;
    END
  END col_event_rst_top_right<0>
  PIN array_col_bot_right<62>
    ANTENNADIFFAREA 0.870000 ;
    PORT
      LAYER met3 ;
        RECT 790.365 0.125 791.135 0.425 ;
    END
  END array_col_bot_right<62>
  PIN array_col_bot_right<61>
    ANTENNADIFFAREA 0.870000 ;
    PORT
      LAYER met3 ;
        RECT 798.245 0.125 799.015 0.425 ;
    END
  END array_col_bot_right<61>
  PIN array_col_bot_right<60>
    ANTENNADIFFAREA 0.870000 ;
    PORT
      LAYER met3 ;
        RECT 814.365 0.125 815.135 0.425 ;
    END
  END array_col_bot_right<60>
  PIN array_col_bot_right<59>
    ANTENNADIFFAREA 0.870000 ;
    PORT
      LAYER met3 ;
        RECT 822.245 0.125 823.015 0.425 ;
    END
  END array_col_bot_right<59>
  PIN array_col_bot_right<58>
    ANTENNADIFFAREA 0.870000 ;
    PORT
      LAYER met3 ;
        RECT 838.365 0.125 839.135 0.425 ;
    END
  END array_col_bot_right<58>
  PIN array_col_bot_right<57>
    ANTENNADIFFAREA 0.870000 ;
    PORT
      LAYER met3 ;
        RECT 846.245 0.125 847.015 0.425 ;
    END
  END array_col_bot_right<57>
  PIN array_col_top_left<43>
    ANTENNADIFFAREA 0.870000 ;
    PORT
      LAYER met3 ;
        RECT 246.245 1638.015 247.015 1638.315 ;
    END
  END array_col_top_left<43>
  PIN array_col_top_left<44>
    ANTENNADIFFAREA 0.870000 ;
    PORT
      LAYER met3 ;
        RECT 238.365 1638.015 239.135 1638.315 ;
    END
  END array_col_top_left<44>
  PIN array_col_top_left<37>
    ANTENNADIFFAREA 0.870000 ;
    PORT
      LAYER met3 ;
        RECT 318.245 1638.015 319.015 1638.315 ;
    END
  END array_col_top_left<37>
  PIN array_col_top_left<50>
    ANTENNADIFFAREA 0.870000 ;
    PORT
      LAYER met3 ;
        RECT 166.365 1638.015 167.135 1638.315 ;
    END
  END array_col_top_left<50>
  PIN array_col_top_left<51>
    ANTENNADIFFAREA 0.870000 ;
    PORT
      LAYER met3 ;
        RECT 150.245 1638.015 151.015 1638.315 ;
    END
  END array_col_top_left<51>
  PIN col_event_rst_bot_right<40>
    ANTENNAGATEAREA 4.032000 ;
    PORT
      LAYER met3 ;
        RECT 1057.595 0.245 1057.895 0.545 ;
    END
  END col_event_rst_bot_right<40>
  PIN col_event_rst_bot_right<42>
    ANTENNAGATEAREA 4.032000 ;
    PORT
      LAYER met3 ;
        RECT 1033.595 0.245 1033.895 0.545 ;
    END
  END col_event_rst_bot_right<42>
  PIN col_event_rst_bot_right<43>
    ANTENNAGATEAREA 4.032000 ;
    PORT
      LAYER met3 ;
        RECT 1011.500 0.245 1011.800 0.545 ;
    END
  END col_event_rst_bot_right<43>
  PIN col_event_rst_bot_left<0>
    ANTENNAGATEAREA 4.032000 ;
    PORT
      LAYER met3 ;
        RECT 769.595 0.245 769.895 0.545 ;
    END
  END col_event_rst_bot_left<0>
  PIN col_event_rst_bot_left<63>
    ANTENNAGATEAREA 4.032000 ;
    PORT
      LAYER met3 ;
        RECT 3.500 0.245 3.800 0.545 ;
    END
  END col_event_rst_bot_left<63>
  PIN array_col_top_left<10>
    ANTENNADIFFAREA 0.870000 ;
    PORT
      LAYER met3 ;
        RECT 646.365 1638.015 647.135 1638.315 ;
    END
  END array_col_top_left<10>
  PIN array_col_top_left<12>
    ANTENNADIFFAREA 0.870000 ;
    PORT
      LAYER met3 ;
        RECT 622.365 1638.015 623.135 1638.315 ;
    END
  END array_col_top_left<12>
  PIN array_col_top_left<13>
    ANTENNADIFFAREA 0.870000 ;
    PORT
      LAYER met3 ;
        RECT 606.245 1638.015 607.015 1638.315 ;
    END
  END array_col_top_left<13>
  PIN array_col_top_left<16>
    ANTENNADIFFAREA 0.870000 ;
    PORT
      LAYER met3 ;
        RECT 574.365 1638.015 575.135 1638.315 ;
    END
  END array_col_top_left<16>
  PIN array_col_top_left<19>
    ANTENNADIFFAREA 0.870000 ;
    PORT
      LAYER met3 ;
        RECT 534.245 1638.015 535.015 1638.315 ;
    END
  END array_col_top_left<19>
  PIN array_col_top_left<1>
    ANTENNADIFFAREA 0.870000 ;
    PORT
      LAYER met3 ;
        RECT 750.245 1638.015 751.015 1638.315 ;
    END
  END array_col_top_left<1>
  PIN array_col_top_left<21>
    ANTENNADIFFAREA 0.870000 ;
    PORT
      LAYER met3 ;
        RECT 510.245 1638.015 511.015 1638.315 ;
    END
  END array_col_top_left<21>
  PIN array_col_top_left<22>
    ANTENNADIFFAREA 0.870000 ;
    PORT
      LAYER met3 ;
        RECT 502.365 1638.015 503.135 1638.315 ;
    END
  END array_col_top_left<22>
  PIN array_col_top_left<25>
    ANTENNADIFFAREA 0.870000 ;
    PORT
      LAYER met3 ;
        RECT 462.245 1638.015 463.015 1638.315 ;
    END
  END array_col_top_left<25>
  PIN array_col_top_left<28>
    ANTENNADIFFAREA 0.870000 ;
    PORT
      LAYER met3 ;
        RECT 430.365 1638.015 431.135 1638.315 ;
    END
  END array_col_top_left<28>
  PIN array_col_top_left<29>
    ANTENNADIFFAREA 0.870000 ;
    PORT
      LAYER met3 ;
        RECT 414.245 1638.015 415.015 1638.315 ;
    END
  END array_col_top_left<29>
  PIN array_col_top_left<30>
    ANTENNADIFFAREA 0.870000 ;
    PORT
      LAYER met3 ;
        RECT 406.365 1638.015 407.135 1638.315 ;
    END
  END array_col_top_left<30>
  PIN array_col_top_left<31>
    ANTENNADIFFAREA 0.870000 ;
    PORT
      LAYER met3 ;
        RECT 390.245 1638.015 391.015 1638.315 ;
    END
  END array_col_top_left<31>
  PIN array_col_top_left<33>
    ANTENNADIFFAREA 0.870000 ;
    PORT
      LAYER met3 ;
        RECT 366.245 1638.015 367.015 1638.315 ;
    END
  END array_col_top_left<33>
  PIN array_col_top_left<34>
    ANTENNADIFFAREA 0.870000 ;
    PORT
      LAYER met3 ;
        RECT 358.365 1638.015 359.135 1638.315 ;
    END
  END array_col_top_left<34>
  PIN array_col_bot_right<47>
    ANTENNADIFFAREA 0.870000 ;
    PORT
      LAYER met3 ;
        RECT 966.245 0.125 967.015 0.425 ;
    END
  END array_col_bot_right<47>
  PIN array_col_bot_right<42>
    ANTENNADIFFAREA 0.870000 ;
    PORT
      LAYER met3 ;
        RECT 1030.365 0.125 1031.135 0.425 ;
    END
  END array_col_bot_right<42>
  PIN array_col_top_right<20>
    ANTENNADIFFAREA 0.870000 ;
    PORT
      LAYER met3 ;
        RECT 1294.365 1638.015 1295.135 1638.315 ;
    END
  END array_col_top_right<20>
  PIN array_col_bot_right<35>
    ANTENNADIFFAREA 0.870000 ;
    PORT
      LAYER met3 ;
        RECT 1110.245 0.125 1111.015 0.425 ;
    END
  END array_col_bot_right<35>
  PIN array_col_bot_right<36>
    ANTENNADIFFAREA 0.870000 ;
    PORT
      LAYER met3 ;
        RECT 1102.365 0.125 1103.135 0.425 ;
    END
  END array_col_bot_right<36>
  PIN array_col_bot_right<37>
    ANTENNADIFFAREA 0.870000 ;
    PORT
      LAYER met3 ;
        RECT 1086.245 0.125 1087.015 0.425 ;
    END
  END array_col_bot_right<37>
  PIN array_col_bot_right<38>
    ANTENNADIFFAREA 0.870000 ;
    PORT
      LAYER met3 ;
        RECT 1078.365 0.125 1079.135 0.425 ;
    END
  END array_col_bot_right<38>
  PIN array_col_bot_right<3>
    ANTENNADIFFAREA 0.870000 ;
    PORT
      LAYER met3 ;
        RECT 1494.245 0.125 1495.015 0.425 ;
    END
  END array_col_bot_right<3>
  PIN col_event_rst_bot_left<52>
    ANTENNAGATEAREA 4.032000 ;
    PORT
      LAYER met3 ;
        RECT 145.595 0.245 145.895 0.545 ;
    END
  END col_event_rst_bot_left<52>
  PIN col_event_rst_top_right<58>
    ANTENNAGATEAREA 4.032000 ;
    PORT
      LAYER met3 ;
        RECT 841.595 1637.895 841.895 1638.195 ;
    END
  END col_event_rst_top_right<58>
  PIN col_event_rst_top_right<59>
    ANTENNAGATEAREA 4.032000 ;
    PORT
      LAYER met3 ;
        RECT 819.500 1637.895 819.800 1638.195 ;
    END
  END col_event_rst_top_right<59>
  PIN col_event_rst_top_right<61>
    ANTENNAGATEAREA 4.032000 ;
    PORT
      LAYER met3 ;
        RECT 795.500 1637.895 795.800 1638.195 ;
    END
  END col_event_rst_top_right<61>
  PIN col_event_rst_top_right<62>
    ANTENNAGATEAREA 4.032000 ;
    PORT
      LAYER met3 ;
        RECT 793.595 1637.895 793.895 1638.195 ;
    END
  END col_event_rst_top_right<62>
  PIN array_col_bot_right<5>
    ANTENNADIFFAREA 0.870000 ;
    PORT
      LAYER met3 ;
        RECT 1470.245 0.125 1471.015 0.425 ;
    END
  END array_col_bot_right<5>
  PIN array_col_bot_right<6>
    ANTENNADIFFAREA 0.870000 ;
    PORT
      LAYER met3 ;
        RECT 1462.365 0.125 1463.135 0.425 ;
    END
  END array_col_bot_right<6>
  PIN array_col_top_left<48>
    ANTENNADIFFAREA 0.870000 ;
    PORT
      LAYER met3 ;
        RECT 190.365 1638.015 191.135 1638.315 ;
    END
  END array_col_top_left<48>
  PIN array_col_top_left<58>
    ANTENNADIFFAREA 0.870000 ;
    PORT
      LAYER met3 ;
        RECT 70.365 1638.015 71.135 1638.315 ;
    END
  END array_col_top_left<58>
  PIN array_col_top_right<6>
    ANTENNADIFFAREA 0.870000 ;
    PORT
      LAYER met3 ;
        RECT 1462.365 1638.015 1463.135 1638.315 ;
    END
  END array_col_top_right<6>
  PIN array_col_top_left<39>
    ANTENNADIFFAREA 0.870000 ;
    PORT
      LAYER met3 ;
        RECT 294.245 1638.015 295.015 1638.315 ;
    END
  END array_col_top_left<39>
  PIN array_col_top_left<59>
    ANTENNADIFFAREA 0.870000 ;
    PORT
      LAYER met3 ;
        RECT 54.245 1638.015 55.015 1638.315 ;
    END
  END array_col_top_left<59>
  PIN array_col_top_right<8>
    ANTENNADIFFAREA 0.870000 ;
    PORT
      LAYER met3 ;
        RECT 1438.365 1638.015 1439.135 1638.315 ;
    END
  END array_col_top_right<8>
  PIN array_col_top_left<61>
    ANTENNADIFFAREA 0.870000 ;
    PORT
      LAYER met3 ;
        RECT 30.245 1638.015 31.015 1638.315 ;
    END
  END array_col_top_left<61>
  PIN array_col_top_left<6>
    ANTENNADIFFAREA 0.870000 ;
    PORT
      LAYER met3 ;
        RECT 694.365 1638.015 695.135 1638.315 ;
    END
  END array_col_top_left<6>
  PIN array_col_top_left<7>
    ANTENNADIFFAREA 0.870000 ;
    PORT
      LAYER met3 ;
        RECT 678.245 1638.015 679.015 1638.315 ;
    END
  END array_col_top_left<7>
  PIN array_col_top_left<9>
    ANTENNADIFFAREA 0.870000 ;
    PORT
      LAYER met3 ;
        RECT 654.245 1638.015 655.015 1638.315 ;
    END
  END array_col_top_left<9>
  PIN array_col_top_right<9>
    ANTENNADIFFAREA 0.870000 ;
    PORT
      LAYER met3 ;
        RECT 1422.245 1638.015 1423.015 1638.315 ;
    END
  END array_col_top_right<9>
  PIN array_col_top_right<10>
    ANTENNADIFFAREA 0.870000 ;
    PORT
      LAYER met3 ;
        RECT 1414.365 1638.015 1415.135 1638.315 ;
    END
  END array_col_top_right<10>
  PIN array_col_top_left<40>
    ANTENNADIFFAREA 0.870000 ;
    PORT
      LAYER met3 ;
        RECT 286.365 1638.015 287.135 1638.315 ;
    END
  END array_col_top_left<40>
  PIN array_col_top_right<11>
    ANTENNADIFFAREA 0.870000 ;
    PORT
      LAYER met3 ;
        RECT 1398.245 1638.015 1399.015 1638.315 ;
    END
  END array_col_top_right<11>
  PIN array_col_bot_right<56>
    ANTENNADIFFAREA 0.870000 ;
    PORT
      LAYER met3 ;
        RECT 862.365 0.125 863.135 0.425 ;
    END
  END array_col_bot_right<56>
  PIN col_event_rst_bot_left<54>
    ANTENNAGATEAREA 4.032000 ;
    PORT
      LAYER met3 ;
        RECT 121.595 0.245 121.895 0.545 ;
    END
  END col_event_rst_bot_left<54>
  PIN col_event_rst_top_left<35>
    ANTENNAGATEAREA 4.032000 ;
    PORT
      LAYER met3 ;
        RECT 339.500 1637.895 339.800 1638.195 ;
    END
  END col_event_rst_top_left<35>
  PIN col_event_rst_top_left<36>
    ANTENNAGATEAREA 4.032000 ;
    PORT
      LAYER met3 ;
        RECT 337.595 1637.895 337.895 1638.195 ;
    END
  END col_event_rst_top_left<36>
  PIN col_event_rst_top_left<37>
    ANTENNAGATEAREA 4.032000 ;
    PORT
      LAYER met3 ;
        RECT 315.500 1637.895 315.800 1638.195 ;
    END
  END col_event_rst_top_left<37>
  PIN col_event_rst_top_left<38>
    ANTENNAGATEAREA 4.032000 ;
    PORT
      LAYER met3 ;
        RECT 313.595 1637.895 313.895 1638.195 ;
    END
  END col_event_rst_top_left<38>
  PIN col_event_rst_top_left<39>
    ANTENNAGATEAREA 4.032000 ;
    PORT
      LAYER met3 ;
        RECT 291.500 1637.895 291.800 1638.195 ;
    END
  END col_event_rst_top_left<39>
  PIN array_col_top_left<63>
    ANTENNADIFFAREA 0.870000 ;
    PORT
      LAYER met3 ;
        RECT 6.245 1638.015 7.015 1638.315 ;
    END
  END array_col_top_left<63>
  PIN col_event_rst_top_left<43>
    ANTENNAGATEAREA 4.032000 ;
    PORT
      LAYER met3 ;
        RECT 243.500 1637.895 243.800 1638.195 ;
    END
  END col_event_rst_top_left<43>
  PIN col_event_rst_bot_right<57>
    ANTENNAGATEAREA 4.032000 ;
    PORT
      LAYER met3 ;
        RECT 843.500 0.245 843.800 0.545 ;
    END
  END col_event_rst_bot_right<57>
  PIN col_event_rst_bot_right<58>
    ANTENNAGATEAREA 4.032000 ;
    PORT
      LAYER met3 ;
        RECT 841.595 0.245 841.895 0.545 ;
    END
  END col_event_rst_bot_right<58>
  PIN col_event_rst_bot_right<59>
    ANTENNAGATEAREA 4.032000 ;
    PORT
      LAYER met3 ;
        RECT 819.500 0.245 819.800 0.545 ;
    END
  END col_event_rst_bot_right<59>
  PIN col_event_rst_bot_right<60>
    ANTENNAGATEAREA 4.032000 ;
    PORT
      LAYER met3 ;
        RECT 817.595 0.245 817.895 0.545 ;
    END
  END col_event_rst_bot_right<60>
  PIN col_event_rst_bot_right<61>
    ANTENNAGATEAREA 4.032000 ;
    PORT
      LAYER met3 ;
        RECT 795.500 0.245 795.800 0.545 ;
    END
  END col_event_rst_bot_right<61>
  PIN col_event_rst_bot_right<62>
    ANTENNAGATEAREA 4.032000 ;
    PORT
      LAYER met3 ;
        RECT 793.595 0.245 793.895 0.545 ;
    END
  END col_event_rst_bot_right<62>
  PIN col_event_rst_top_left<40>
    ANTENNAGATEAREA 4.032000 ;
    PORT
      LAYER met3 ;
        RECT 289.595 1637.895 289.895 1638.195 ;
    END
  END col_event_rst_top_left<40>
  PIN col_event_rst_top_left<0>
    ANTENNAGATEAREA 4.032000 ;
    PORT
      LAYER met3 ;
        RECT 769.595 1637.895 769.895 1638.195 ;
    END
  END col_event_rst_top_left<0>
  PIN col_event_rst_top_left<63>
    PORT
      LAYER met3 ;
        RECT 3.500 1639.145 3.800 1639.445 ;
    END
  END col_event_rst_top_left<63>
  PIN col_event_rst_top_left<1>
    ANTENNAGATEAREA 4.032000 ;
    PORT
      LAYER met3 ;
        RECT 747.500 1637.895 747.800 1638.195 ;
    END
  END col_event_rst_top_left<1>
  PIN col_event_rst_top_left<2>
    ANTENNAGATEAREA 4.032000 ;
    PORT
      LAYER met3 ;
        RECT 745.595 1637.895 745.895 1638.195 ;
    END
  END col_event_rst_top_left<2>
  PIN col_event_rst_bot_right<48>
    ANTENNAGATEAREA 4.032000 ;
    PORT
      LAYER met3 ;
        RECT 961.595 0.245 961.895 0.545 ;
    END
  END col_event_rst_bot_right<48>
  PIN col_event_rst_top_left<3>
    ANTENNAGATEAREA 4.032000 ;
    PORT
      LAYER met3 ;
        RECT 723.500 1637.895 723.800 1638.195 ;
    END
  END col_event_rst_top_left<3>
  PIN col_event_rst_top_left<4>
    ANTENNAGATEAREA 4.032000 ;
    PORT
      LAYER met3 ;
        RECT 721.595 1637.895 721.895 1638.195 ;
    END
  END col_event_rst_top_left<4>
  PIN col_event_rst_top_left<5>
    ANTENNAGATEAREA 4.032000 ;
    PORT
      LAYER met3 ;
        RECT 699.500 1637.895 699.800 1638.195 ;
    END
  END col_event_rst_top_left<5>
  PIN col_event_rst_top_left<6>
    ANTENNAGATEAREA 4.032000 ;
    PORT
      LAYER met3 ;
        RECT 697.595 1637.895 697.895 1638.195 ;
    END
  END col_event_rst_top_left<6>
  PIN col_event_rst_top_left<7>
    ANTENNAGATEAREA 4.032000 ;
    PORT
      LAYER met3 ;
        RECT 675.500 1637.895 675.800 1638.195 ;
    END
  END col_event_rst_top_left<7>
  PIN col_event_rst_top_left<41>
    ANTENNAGATEAREA 4.032000 ;
    PORT
      LAYER met3 ;
        RECT 267.500 1637.895 267.800 1638.195 ;
    END
  END col_event_rst_top_left<41>
  PIN col_event_rst_top_left<8>
    ANTENNAGATEAREA 4.032000 ;
    PORT
      LAYER met3 ;
        RECT 673.595 1637.895 673.895 1638.195 ;
    END
  END col_event_rst_top_left<8>
  PIN col_event_rst_top_left<9>
    ANTENNAGATEAREA 4.032000 ;
    PORT
      LAYER met3 ;
        RECT 651.500 1637.895 651.800 1638.195 ;
    END
  END col_event_rst_top_left<9>
  PIN col_event_rst_top_left<10>
    ANTENNAGATEAREA 4.032000 ;
    PORT
      LAYER met3 ;
        RECT 649.595 1637.895 649.895 1638.195 ;
    END
  END col_event_rst_top_left<10>
  PIN col_event_rst_top_left<11>
    ANTENNAGATEAREA 4.032000 ;
    PORT
      LAYER met3 ;
        RECT 627.500 1637.895 627.800 1638.195 ;
    END
  END col_event_rst_top_left<11>
  PIN col_event_rst_top_left<12>
    ANTENNAGATEAREA 4.032000 ;
    PORT
      LAYER met3 ;
        RECT 625.595 1637.895 625.895 1638.195 ;
    END
  END col_event_rst_top_left<12>
  PIN col_event_rst_bot_right<49>
    ANTENNAGATEAREA 4.032000 ;
    PORT
      LAYER met3 ;
        RECT 939.500 0.245 939.800 0.545 ;
    END
  END col_event_rst_bot_right<49>
  PIN col_event_rst_top_left<13>
    ANTENNAGATEAREA 4.032000 ;
    PORT
      LAYER met3 ;
        RECT 603.500 1637.895 603.800 1638.195 ;
    END
  END col_event_rst_top_left<13>
  PIN col_event_rst_top_left<14>
    ANTENNAGATEAREA 4.032000 ;
    PORT
      LAYER met3 ;
        RECT 601.595 1637.895 601.895 1638.195 ;
    END
  END col_event_rst_top_left<14>
  PIN col_event_rst_top_left<15>
    ANTENNAGATEAREA 4.032000 ;
    PORT
      LAYER met3 ;
        RECT 579.500 1637.895 579.800 1638.195 ;
    END
  END col_event_rst_top_left<15>
  PIN col_event_rst_top_left<16>
    ANTENNAGATEAREA 4.032000 ;
    PORT
      LAYER met3 ;
        RECT 577.595 1637.895 577.895 1638.195 ;
    END
  END col_event_rst_top_left<16>
  PIN array_col_top_left<41>
    ANTENNADIFFAREA 0.870000 ;
    PORT
      LAYER met3 ;
        RECT 270.245 1638.015 271.015 1638.315 ;
    END
  END array_col_top_left<41>
  PIN array_col_top_left<42>
    ANTENNADIFFAREA 0.870000 ;
    PORT
      LAYER met3 ;
        RECT 262.365 1638.015 263.135 1638.315 ;
    END
  END array_col_top_left<42>
  PIN array_col_top_left<45>
    ANTENNADIFFAREA 0.870000 ;
    PORT
      LAYER met3 ;
        RECT 222.245 1638.015 223.015 1638.315 ;
    END
  END array_col_top_left<45>
  PIN array_col_bot_left<54>
    ANTENNADIFFAREA 0.870000 ;
    PORT
      LAYER met3 ;
        RECT 118.365 0.125 119.135 0.425 ;
    END
  END array_col_bot_left<54>
  PIN array_col_top_left<49>
    ANTENNADIFFAREA 0.870000 ;
    PORT
      LAYER met3 ;
        RECT 174.245 1638.015 175.015 1638.315 ;
    END
  END array_col_top_left<49>
  PIN array_col_top_left<4>
    ANTENNADIFFAREA 0.870000 ;
    PORT
      LAYER met3 ;
        RECT 718.365 1638.015 719.135 1638.315 ;
    END
  END array_col_top_left<4>
  PIN array_col_top_left<57>
    ANTENNADIFFAREA 0.870000 ;
    PORT
      LAYER met3 ;
        RECT 78.245 1638.015 79.015 1638.315 ;
    END
  END array_col_top_left<57>
  PIN col_event_rst_bot_right<41>
    ANTENNAGATEAREA 4.032000 ;
    PORT
      LAYER met3 ;
        RECT 1035.500 0.245 1035.800 0.545 ;
    END
  END col_event_rst_bot_right<41>
  PIN array_col_top_left<52>
    ANTENNADIFFAREA 0.870000 ;
    PORT
      LAYER met3 ;
        RECT 142.365 1638.015 143.135 1638.315 ;
    END
  END array_col_top_left<52>
  PIN array_col_top_left<11>
    ANTENNADIFFAREA 0.870000 ;
    PORT
      LAYER met3 ;
        RECT 630.245 1638.015 631.015 1638.315 ;
    END
  END array_col_top_left<11>
  PIN array_col_top_left<53>
    ANTENNADIFFAREA 0.870000 ;
    PORT
      LAYER met3 ;
        RECT 126.245 1638.015 127.015 1638.315 ;
    END
  END array_col_top_left<53>
  PIN array_col_top_left<14>
    ANTENNADIFFAREA 0.870000 ;
    PORT
      LAYER met3 ;
        RECT 598.365 1638.015 599.135 1638.315 ;
    END
  END array_col_top_left<14>
  PIN array_col_top_left<15>
    ANTENNADIFFAREA 0.870000 ;
    PORT
      LAYER met3 ;
        RECT 582.245 1638.015 583.015 1638.315 ;
    END
  END array_col_top_left<15>
  PIN array_col_top_left<17>
    ANTENNADIFFAREA 0.870000 ;
    PORT
      LAYER met3 ;
        RECT 558.245 1638.015 559.015 1638.315 ;
    END
  END array_col_top_left<17>
  PIN array_col_top_left<18>
    ANTENNADIFFAREA 0.870000 ;
    PORT
      LAYER met3 ;
        RECT 550.365 1638.015 551.135 1638.315 ;
    END
  END array_col_top_left<18>
  PIN array_col_top_left<20>
    ANTENNADIFFAREA 0.870000 ;
    PORT
      LAYER met3 ;
        RECT 526.365 1638.015 527.135 1638.315 ;
    END
  END array_col_top_left<20>
  PIN array_col_top_left<54>
    ANTENNADIFFAREA 0.870000 ;
    PORT
      LAYER met3 ;
        RECT 118.365 1638.015 119.135 1638.315 ;
    END
  END array_col_top_left<54>
  PIN array_col_top_left<23>
    ANTENNADIFFAREA 0.870000 ;
    PORT
      LAYER met3 ;
        RECT 486.245 1638.015 487.015 1638.315 ;
    END
  END array_col_top_left<23>
  PIN array_col_top_left<24>
    ANTENNADIFFAREA 0.870000 ;
    PORT
      LAYER met3 ;
        RECT 478.365 1638.015 479.135 1638.315 ;
    END
  END array_col_top_left<24>
  PIN array_col_top_left<26>
    ANTENNADIFFAREA 0.870000 ;
    PORT
      LAYER met3 ;
        RECT 454.365 1638.015 455.135 1638.315 ;
    END
  END array_col_top_left<26>
  PIN array_col_top_left<27>
    ANTENNADIFFAREA 0.870000 ;
    PORT
      LAYER met3 ;
        RECT 438.245 1638.015 439.015 1638.315 ;
    END
  END array_col_top_left<27>
  PIN array_col_top_left<2>
    ANTENNADIFFAREA 0.870000 ;
    PORT
      LAYER met3 ;
        RECT 742.365 1638.015 743.135 1638.315 ;
    END
  END array_col_top_left<2>
  PIN array_col_top_left<55>
    ANTENNADIFFAREA 0.870000 ;
    PORT
      LAYER met3 ;
        RECT 102.245 1638.015 103.015 1638.315 ;
    END
  END array_col_top_left<55>
  PIN array_col_top_left<32>
    ANTENNADIFFAREA 0.870000 ;
    PORT
      LAYER met3 ;
        RECT 382.365 1638.015 383.135 1638.315 ;
    END
  END array_col_top_left<32>
  PIN array_col_top_left<35>
    ANTENNADIFFAREA 0.870000 ;
    PORT
      LAYER met3 ;
        RECT 342.245 1638.015 343.015 1638.315 ;
    END
  END array_col_top_left<35>
  PIN array_col_top_left<36>
    ANTENNADIFFAREA 0.870000 ;
    PORT
      LAYER met3 ;
        RECT 334.365 1638.015 335.135 1638.315 ;
    END
  END array_col_top_left<36>
  PIN col_event_rst_bot_right<46>
    ANTENNAGATEAREA 4.032000 ;
    PORT
      LAYER met3 ;
        RECT 985.595 0.245 985.895 0.545 ;
    END
  END col_event_rst_bot_right<46>
  PIN array_col_top_right<31>
    ANTENNADIFFAREA 0.870000 ;
    PORT
      LAYER met3 ;
        RECT 1158.245 1638.015 1159.015 1638.315 ;
    END
  END array_col_top_right<31>
  PIN array_col_top_right<32>
    ANTENNADIFFAREA 0.870000 ;
    PORT
      LAYER met3 ;
        RECT 1150.365 1638.015 1151.135 1638.315 ;
    END
  END array_col_top_right<32>
  PIN array_col_bot_left<53>
    ANTENNADIFFAREA 0.870000 ;
    PORT
      LAYER met3 ;
        RECT 126.245 0.125 127.015 0.425 ;
    END
  END array_col_bot_left<53>
  PIN array_col_bot_right<39>
    ANTENNADIFFAREA 0.870000 ;
    PORT
      LAYER met3 ;
        RECT 1062.245 0.125 1063.015 0.425 ;
    END
  END array_col_bot_right<39>
  PIN array_col_bot_right<40>
    ANTENNADIFFAREA 0.870000 ;
    PORT
      LAYER met3 ;
        RECT 1054.365 0.125 1055.135 0.425 ;
    END
  END array_col_bot_right<40>
  PIN col_event_rst_bot_left<44>
    ANTENNAGATEAREA 4.032000 ;
    PORT
      LAYER met3 ;
        RECT 241.595 0.245 241.895 0.545 ;
    END
  END col_event_rst_bot_left<44>
  PIN col_event_rst_top_right<57>
    ANTENNAGATEAREA 4.032000 ;
    PORT
      LAYER met3 ;
        RECT 843.500 1637.895 843.800 1638.195 ;
    END
  END col_event_rst_top_right<57>
  PIN col_event_rst_top_right<60>
    ANTENNAGATEAREA 4.032000 ;
    PORT
      LAYER met3 ;
        RECT 817.595 1637.895 817.895 1638.195 ;
    END
  END col_event_rst_top_right<60>
  PIN array_col_bot_right<4>
    ANTENNADIFFAREA 0.870000 ;
    PORT
      LAYER met3 ;
        RECT 1486.365 0.125 1487.135 0.425 ;
    END
  END array_col_bot_right<4>
  PIN col_event_rst_bot_left<1>
    ANTENNAGATEAREA 4.032000 ;
    PORT
      LAYER met3 ;
        RECT 747.500 0.245 747.800 0.545 ;
    END
  END col_event_rst_bot_left<1>
  PIN col_event_rst_top_right<44>
    ANTENNAGATEAREA 4.032000 ;
    PORT
      LAYER met3 ;
        RECT 1009.595 1637.895 1009.895 1638.195 ;
    END
  END col_event_rst_top_right<44>
  PIN array_col_bot_right<7>
    ANTENNADIFFAREA 0.870000 ;
    PORT
      LAYER met3 ;
        RECT 1446.245 0.125 1447.015 0.425 ;
    END
  END array_col_bot_right<7>
  PIN array_col_top_left<46>
    ANTENNADIFFAREA 0.870000 ;
    PORT
      LAYER met3 ;
        RECT 214.365 1638.015 215.135 1638.315 ;
    END
  END array_col_top_left<46>
  PIN array_col_top_left<47>
    ANTENNADIFFAREA 0.870000 ;
    PORT
      LAYER met3 ;
        RECT 198.245 1638.015 199.015 1638.315 ;
    END
  END array_col_top_left<47>
  PIN col_event_rst_bot_left<50>
    ANTENNAGATEAREA 4.032000 ;
    PORT
      LAYER met3 ;
        RECT 169.595 0.245 169.895 0.545 ;
    END
  END col_event_rst_bot_left<50>
  PIN array_col_top_right<5>
    ANTENNADIFFAREA 0.870000 ;
    PORT
      LAYER met3 ;
        RECT 1470.245 1638.015 1471.015 1638.315 ;
    END
  END array_col_top_right<5>
  PIN array_col_top_right<7>
    ANTENNADIFFAREA 0.870000 ;
    PORT
      LAYER met3 ;
        RECT 1446.245 1638.015 1447.015 1638.315 ;
    END
  END array_col_top_right<7>
  PIN array_col_top_left<5>
    ANTENNADIFFAREA 0.870000 ;
    PORT
      LAYER met3 ;
        RECT 702.245 1638.015 703.015 1638.315 ;
    END
  END array_col_top_left<5>
  PIN array_col_top_left<60>
    ANTENNADIFFAREA 0.870000 ;
    PORT
      LAYER met3 ;
        RECT 46.365 1638.015 47.135 1638.315 ;
    END
  END array_col_top_left<60>
  PIN array_col_top_left<62>
    ANTENNADIFFAREA 0.870000 ;
    PORT
      LAYER met3 ;
        RECT 22.365 1638.015 23.135 1638.315 ;
    END
  END array_col_top_left<62>
  PIN array_col_top_left<8>
    ANTENNADIFFAREA 0.870000 ;
    PORT
      LAYER met3 ;
        RECT 670.365 1638.015 671.135 1638.315 ;
    END
  END array_col_top_left<8>
  PIN array_col_top_left<56>
    ANTENNADIFFAREA 0.870000 ;
    PORT
      LAYER met3 ;
        RECT 94.365 1638.015 95.135 1638.315 ;
    END
  END array_col_top_left<56>
  PIN col_event_rst_bot_right<47>
    ANTENNAGATEAREA 4.032000 ;
    PORT
      LAYER met3 ;
        RECT 963.500 0.245 963.800 0.545 ;
    END
  END col_event_rst_bot_right<47>
  PIN array_col_top_left<3>
    ANTENNADIFFAREA 0.870000 ;
    PORT
      LAYER met3 ;
        RECT 726.245 1638.015 727.015 1638.315 ;
    END
  END array_col_top_left<3>
  PIN col_event_rst_top_left<45>
    ANTENNAGATEAREA 4.032000 ;
    PORT
      LAYER met3 ;
        RECT 219.500 1637.895 219.800 1638.195 ;
    END
  END col_event_rst_top_left<45>
  PIN col_event_rst_top_left<17>
    ANTENNAGATEAREA 4.032000 ;
    PORT
      LAYER met3 ;
        RECT 555.500 1637.895 555.800 1638.195 ;
    END
  END col_event_rst_top_left<17>
  PIN col_event_rst_top_left<18>
    ANTENNAGATEAREA 4.032000 ;
    PORT
      LAYER met3 ;
        RECT 553.595 1637.895 553.895 1638.195 ;
    END
  END col_event_rst_top_left<18>
  PIN col_event_rst_top_left<19>
    ANTENNAGATEAREA 4.032000 ;
    PORT
      LAYER met3 ;
        RECT 531.500 1637.895 531.800 1638.195 ;
    END
  END col_event_rst_top_left<19>
  PIN col_event_rst_top_left<20>
    ANTENNAGATEAREA 4.032000 ;
    PORT
      LAYER met3 ;
        RECT 529.595 1637.895 529.895 1638.195 ;
    END
  END col_event_rst_top_left<20>
  PIN col_event_rst_top_left<21>
    ANTENNAGATEAREA 4.032000 ;
    PORT
      LAYER met3 ;
        RECT 507.500 1637.895 507.800 1638.195 ;
    END
  END col_event_rst_top_left<21>
  PIN col_event_rst_top_left<22>
    ANTENNAGATEAREA 4.032000 ;
    PORT
      LAYER met3 ;
        RECT 505.595 1637.895 505.895 1638.195 ;
    END
  END col_event_rst_top_left<22>
  PIN col_event_rst_bot_right<50>
    ANTENNAGATEAREA 4.032000 ;
    PORT
      LAYER met3 ;
        RECT 937.595 0.245 937.895 0.545 ;
    END
  END col_event_rst_bot_right<50>
  PIN col_event_rst_top_left<23>
    ANTENNAGATEAREA 4.032000 ;
    PORT
      LAYER met3 ;
        RECT 483.500 1637.895 483.800 1638.195 ;
    END
  END col_event_rst_top_left<23>
  PIN col_event_rst_top_left<24>
    ANTENNAGATEAREA 4.032000 ;
    PORT
      LAYER met3 ;
        RECT 481.595 1637.895 481.895 1638.195 ;
    END
  END col_event_rst_top_left<24>
  PIN col_event_rst_top_left<25>
    ANTENNAGATEAREA 4.032000 ;
    PORT
      LAYER met3 ;
        RECT 459.500 1637.895 459.800 1638.195 ;
    END
  END col_event_rst_top_left<25>
  PIN col_event_rst_bot_right<52>
    ANTENNAGATEAREA 4.032000 ;
    PORT
      LAYER met3 ;
        RECT 913.595 0.245 913.895 0.545 ;
    END
  END col_event_rst_bot_right<52>
  PIN col_event_rst_top_left<26>
    ANTENNAGATEAREA 4.032000 ;
    PORT
      LAYER met3 ;
        RECT 457.595 1637.895 457.895 1638.195 ;
    END
  END col_event_rst_top_left<26>
  PIN col_event_rst_top_left<27>
    ANTENNAGATEAREA 4.032000 ;
    PORT
      LAYER met3 ;
        RECT 435.500 1637.895 435.800 1638.195 ;
    END
  END col_event_rst_top_left<27>
  PIN col_event_rst_top_left<28>
    ANTENNAGATEAREA 4.032000 ;
    PORT
      LAYER met3 ;
        RECT 433.595 1637.895 433.895 1638.195 ;
    END
  END col_event_rst_top_left<28>
  PIN col_event_rst_top_left<29>
    ANTENNAGATEAREA 4.032000 ;
    PORT
      LAYER met3 ;
        RECT 411.500 1637.895 411.800 1638.195 ;
    END
  END col_event_rst_top_left<29>
  PIN col_event_rst_top_left<30>
    ANTENNAGATEAREA 4.032000 ;
    PORT
      LAYER met3 ;
        RECT 409.595 1637.895 409.895 1638.195 ;
    END
  END col_event_rst_top_left<30>
  PIN col_event_rst_top_left<31>
    ANTENNAGATEAREA 4.032000 ;
    PORT
      LAYER met3 ;
        RECT 387.500 1637.895 387.800 1638.195 ;
    END
  END col_event_rst_top_left<31>
  PIN col_event_rst_top_left<32>
    ANTENNAGATEAREA 4.032000 ;
    PORT
      LAYER met3 ;
        RECT 385.595 1637.895 385.895 1638.195 ;
    END
  END col_event_rst_top_left<32>
  PIN col_event_rst_bot_right<51>
    ANTENNAGATEAREA 4.032000 ;
    PORT
      LAYER met3 ;
        RECT 915.500 0.245 915.800 0.545 ;
    END
  END col_event_rst_bot_right<51>
  PIN col_event_rst_top_left<33>
    ANTENNAGATEAREA 4.032000 ;
    PORT
      LAYER met3 ;
        RECT 363.500 1637.895 363.800 1638.195 ;
    END
  END col_event_rst_top_left<33>
  PIN col_event_rst_top_left<34>
    ANTENNAGATEAREA 4.032000 ;
    PORT
      LAYER met3 ;
        RECT 361.595 1637.895 361.895 1638.195 ;
    END
  END col_event_rst_top_left<34>
  PIN col_event_rst_bot_left<55>
    ANTENNAGATEAREA 4.032000 ;
    PORT
      LAYER met3 ;
        RECT 99.500 0.245 99.800 0.545 ;
    END
  END col_event_rst_bot_left<55>
  PIN col_event_rst_bot_right<31>
    ANTENNAGATEAREA 4.032000 ;
    PORT
      LAYER met3 ;
        RECT 1155.500 0.245 1155.800 0.545 ;
    END
  END col_event_rst_bot_right<31>
  PIN col_event_rst_bot_right<32>
    ANTENNAGATEAREA 4.032000 ;
    PORT
      LAYER met3 ;
        RECT 1153.595 0.245 1153.895 0.545 ;
    END
  END col_event_rst_bot_right<32>
  PIN col_event_rst_bot_right<33>
    ANTENNAGATEAREA 4.032000 ;
    PORT
      LAYER met3 ;
        RECT 1131.500 0.245 1131.800 0.545 ;
    END
  END col_event_rst_bot_right<33>
  PIN col_event_rst_bot_right<39>
    ANTENNAGATEAREA 4.032000 ;
    PORT
      LAYER met3 ;
        RECT 1059.500 0.245 1059.800 0.545 ;
    END
  END col_event_rst_bot_right<39>
  PIN col_event_rst_top_left<46>
    ANTENNAGATEAREA 4.032000 ;
    PORT
      LAYER met3 ;
        RECT 217.595 1637.895 217.895 1638.195 ;
    END
  END col_event_rst_top_left<46>
  PIN col_event_rst_top_left<47>
    ANTENNAGATEAREA 4.032000 ;
    PORT
      LAYER met3 ;
        RECT 195.500 1637.895 195.800 1638.195 ;
    END
  END col_event_rst_top_left<47>
  PIN col_event_rst_top_left<48>
    ANTENNAGATEAREA 4.032000 ;
    PORT
      LAYER met3 ;
        RECT 193.595 1637.895 193.895 1638.195 ;
    END
  END col_event_rst_top_left<48>
  PIN col_event_rst_bot_right<34>
    ANTENNAGATEAREA 4.032000 ;
    PORT
      LAYER met3 ;
        RECT 1129.595 0.245 1129.895 0.545 ;
    END
  END col_event_rst_bot_right<34>
  PIN array_col_bot_left<48>
    ANTENNADIFFAREA 0.870000 ;
    PORT
      LAYER met3 ;
        RECT 190.365 0.125 191.135 0.425 ;
    END
  END array_col_bot_left<48>
  PIN col_event_rst_bot_right<53>
    ANTENNAGATEAREA 4.032000 ;
    PORT
      LAYER met3 ;
        RECT 891.500 0.245 891.800 0.545 ;
    END
  END col_event_rst_bot_right<53>
  PIN col_event_rst_bot_right<54>
    ANTENNAGATEAREA 4.032000 ;
    PORT
      LAYER met3 ;
        RECT 889.595 0.245 889.895 0.545 ;
    END
  END col_event_rst_bot_right<54>
  PIN col_event_rst_bot_right<55>
    ANTENNAGATEAREA 4.032000 ;
    PORT
      LAYER met3 ;
        RECT 867.500 0.245 867.800 0.545 ;
    END
  END col_event_rst_bot_right<55>
  PIN col_event_rst_bot_right<56>
    ANTENNAGATEAREA 4.032000 ;
    PORT
      LAYER met3 ;
        RECT 865.595 0.245 865.895 0.545 ;
    END
  END col_event_rst_bot_right<56>
  PIN col_event_rst_bot_right<44>
    ANTENNAGATEAREA 4.032000 ;
    PORT
      LAYER met3 ;
        RECT 1009.595 0.245 1009.895 0.545 ;
    END
  END col_event_rst_bot_right<44>
  PIN col_event_rst_bot_right<1>
    ANTENNAGATEAREA 4.032000 ;
    PORT
      LAYER met3 ;
        RECT 1515.500 0.245 1515.800 0.545 ;
    END
  END col_event_rst_bot_right<1>
  PIN col_event_rst_bot_right<2>
    ANTENNAGATEAREA 4.032000 ;
    PORT
      LAYER met3 ;
        RECT 1513.595 0.245 1513.895 0.545 ;
    END
  END col_event_rst_bot_right<2>
  PIN col_event_rst_top_left<52>
    ANTENNAGATEAREA 4.032000 ;
    PORT
      LAYER met3 ;
        RECT 145.595 1637.895 145.895 1638.195 ;
    END
  END col_event_rst_top_left<52>
  PIN array_col_bot_left<25>
    ANTENNADIFFAREA 0.870000 ;
    PORT
      LAYER met3 ;
        RECT 462.245 0.125 463.015 0.425 ;
    END
  END array_col_bot_left<25>
  PIN array_col_bot_left<26>
    ANTENNADIFFAREA 0.870000 ;
    PORT
      LAYER met3 ;
        RECT 454.365 0.125 455.135 0.425 ;
    END
  END array_col_bot_left<26>
  PIN array_col_bot_left<27>
    ANTENNADIFFAREA 0.870000 ;
    PORT
      LAYER met3 ;
        RECT 438.245 0.125 439.015 0.425 ;
    END
  END array_col_bot_left<27>
  PIN array_col_bot_left<28>
    ANTENNADIFFAREA 0.870000 ;
    PORT
      LAYER met3 ;
        RECT 430.365 0.125 431.135 0.425 ;
    END
  END array_col_bot_left<28>
  PIN array_col_bot_left<29>
    ANTENNADIFFAREA 0.870000 ;
    PORT
      LAYER met3 ;
        RECT 414.245 0.125 415.015 0.425 ;
    END
  END array_col_bot_left<29>
  PIN array_col_bot_left<30>
    ANTENNADIFFAREA 0.870000 ;
    PORT
      LAYER met3 ;
        RECT 406.365 0.125 407.135 0.425 ;
    END
  END array_col_bot_left<30>
  PIN array_col_bot_left<31>
    ANTENNADIFFAREA 0.870000 ;
    PORT
      LAYER met3 ;
        RECT 390.245 0.125 391.015 0.425 ;
    END
  END array_col_bot_left<31>
  PIN array_col_bot_left<32>
    ANTENNADIFFAREA 0.870000 ;
    PORT
      LAYER met3 ;
        RECT 382.365 0.125 383.135 0.425 ;
    END
  END array_col_bot_left<32>
  PIN array_col_bot_left<9>
    ANTENNADIFFAREA 0.870000 ;
    PORT
      LAYER met3 ;
        RECT 654.245 0.125 655.015 0.425 ;
    END
  END array_col_bot_left<9>
  PIN array_col_bot_left<33>
    ANTENNADIFFAREA 0.870000 ;
    PORT
      LAYER met3 ;
        RECT 366.245 0.125 367.015 0.425 ;
    END
  END array_col_bot_left<33>
  PIN array_col_bot_left<57>
    ANTENNADIFFAREA 0.870000 ;
    PORT
      LAYER met3 ;
        RECT 78.245 0.125 79.015 0.425 ;
    END
  END array_col_bot_left<57>
  PIN array_col_bot_left<34>
    ANTENNADIFFAREA 0.870000 ;
    PORT
      LAYER met3 ;
        RECT 358.365 0.125 359.135 0.425 ;
    END
  END array_col_bot_left<34>
  PIN col_event_rst_top_left<53>
    ANTENNAGATEAREA 4.032000 ;
    PORT
      LAYER met3 ;
        RECT 123.500 1637.895 123.800 1638.195 ;
    END
  END col_event_rst_top_left<53>
  PIN array_col_bot_left<35>
    ANTENNADIFFAREA 0.870000 ;
    PORT
      LAYER met3 ;
        RECT 342.245 0.125 343.015 0.425 ;
    END
  END array_col_bot_left<35>
  PIN array_col_bot_left<36>
    ANTENNADIFFAREA 0.870000 ;
    PORT
      LAYER met3 ;
        RECT 334.365 0.125 335.135 0.425 ;
    END
  END array_col_bot_left<36>
  PIN array_col_bot_left<37>
    ANTENNADIFFAREA 0.870000 ;
    PORT
      LAYER met3 ;
        RECT 318.245 0.125 319.015 0.425 ;
    END
  END array_col_bot_left<37>
  PIN array_col_bot_left<38>
    ANTENNADIFFAREA 0.870000 ;
    PORT
      LAYER met3 ;
        RECT 310.365 0.125 311.135 0.425 ;
    END
  END array_col_bot_left<38>
  PIN array_col_bot_left<39>
    ANTENNADIFFAREA 0.870000 ;
    PORT
      LAYER met3 ;
        RECT 294.245 0.125 295.015 0.425 ;
    END
  END array_col_bot_left<39>
  PIN array_col_bot_left<40>
    ANTENNADIFFAREA 0.870000 ;
    PORT
      LAYER met3 ;
        RECT 286.365 0.125 287.135 0.425 ;
    END
  END array_col_bot_left<40>
  PIN array_col_bot_left<10>
    ANTENNADIFFAREA 0.870000 ;
    PORT
      LAYER met3 ;
        RECT 646.365 0.125 647.135 0.425 ;
    END
  END array_col_bot_left<10>
  PIN array_col_bot_left<41>
    ANTENNADIFFAREA 0.870000 ;
    PORT
      LAYER met3 ;
        RECT 270.245 0.125 271.015 0.425 ;
    END
  END array_col_bot_left<41>
  PIN array_col_top_left<0>
    ANTENNADIFFAREA 0.870000 ;
    PORT
      LAYER met3 ;
        RECT 766.365 1638.015 767.135 1638.315 ;
    END
  END array_col_top_left<0>
  PIN array_col_top_right<33>
    ANTENNADIFFAREA 0.870000 ;
    PORT
      LAYER met3 ;
        RECT 1134.245 1638.015 1135.015 1638.315 ;
    END
  END array_col_top_right<33>
  PIN array_col_top_right<34>
    ANTENNADIFFAREA 0.870000 ;
    PORT
      LAYER met3 ;
        RECT 1126.365 1638.015 1127.135 1638.315 ;
    END
  END array_col_top_right<34>
  PIN array_col_top_right<35>
    ANTENNADIFFAREA 0.870000 ;
    PORT
      LAYER met3 ;
        RECT 1110.245 1638.015 1111.015 1638.315 ;
    END
  END array_col_top_right<35>
  PIN array_col_top_right<36>
    ANTENNADIFFAREA 0.870000 ;
    PORT
      LAYER met3 ;
        RECT 1102.365 1638.015 1103.135 1638.315 ;
    END
  END array_col_top_right<36>
  PIN array_col_top_right<37>
    ANTENNADIFFAREA 0.870000 ;
    PORT
      LAYER met3 ;
        RECT 1086.245 1638.015 1087.015 1638.315 ;
    END
  END array_col_top_right<37>
  PIN array_col_top_right<38>
    ANTENNADIFFAREA 0.870000 ;
    PORT
      LAYER met3 ;
        RECT 1078.365 1638.015 1079.135 1638.315 ;
    END
  END array_col_top_right<38>
  PIN array_col_top_right<39>
    ANTENNADIFFAREA 0.870000 ;
    PORT
      LAYER met3 ;
        RECT 1062.245 1638.015 1063.015 1638.315 ;
    END
  END array_col_top_right<39>
  PIN array_col_bot_right<43>
    ANTENNADIFFAREA 0.870000 ;
    PORT
      LAYER met3 ;
        RECT 1014.245 0.125 1015.015 0.425 ;
    END
  END array_col_bot_right<43>
  PIN array_col_top_right<40>
    ANTENNADIFFAREA 0.870000 ;
    PORT
      LAYER met3 ;
        RECT 1054.365 1638.015 1055.135 1638.315 ;
    END
  END array_col_top_right<40>
  PIN array_col_top_right<22>
    ANTENNADIFFAREA 0.870000 ;
    PORT
      LAYER met3 ;
        RECT 1270.365 1638.015 1271.135 1638.315 ;
    END
  END array_col_top_right<22>
  PIN col_event_rst_top_right<46>
    ANTENNAGATEAREA 4.032000 ;
    PORT
      LAYER met3 ;
        RECT 985.595 1637.895 985.895 1638.195 ;
    END
  END col_event_rst_top_right<46>
  PIN array_col_top_right<41>
    ANTENNADIFFAREA 0.870000 ;
    PORT
      LAYER met3 ;
        RECT 1038.245 1638.015 1039.015 1638.315 ;
    END
  END array_col_top_right<41>
  PIN array_col_top_right<42>
    ANTENNADIFFAREA 0.870000 ;
    PORT
      LAYER met3 ;
        RECT 1030.365 1638.015 1031.135 1638.315 ;
    END
  END array_col_top_right<42>
  PIN array_col_top_right<43>
    ANTENNADIFFAREA 0.870000 ;
    PORT
      LAYER met3 ;
        RECT 1014.245 1638.015 1015.015 1638.315 ;
    END
  END array_col_top_right<43>
  PIN array_col_top_right<44>
    ANTENNADIFFAREA 0.870000 ;
    PORT
      LAYER met3 ;
        RECT 1006.365 1638.015 1007.135 1638.315 ;
    END
  END array_col_top_right<44>
  PIN array_col_top_right<45>
    ANTENNADIFFAREA 0.870000 ;
    PORT
      LAYER met3 ;
        RECT 990.245 1638.015 991.015 1638.315 ;
    END
  END array_col_top_right<45>
  PIN array_col_top_right<46>
    ANTENNADIFFAREA 0.870000 ;
    PORT
      LAYER met3 ;
        RECT 982.365 1638.015 983.135 1638.315 ;
    END
  END array_col_top_right<46>
  PIN array_col_top_right<47>
    ANTENNADIFFAREA 0.870000 ;
    PORT
      LAYER met3 ;
        RECT 966.245 1638.015 967.015 1638.315 ;
    END
  END array_col_top_right<47>
  PIN array_col_top_right<48>
    ANTENNADIFFAREA 0.870000 ;
    PORT
      LAYER met3 ;
        RECT 958.365 1638.015 959.135 1638.315 ;
    END
  END array_col_top_right<48>
  PIN array_col_bot_right<44>
    ANTENNADIFFAREA 0.870000 ;
    PORT
      LAYER met3 ;
        RECT 1006.365 0.125 1007.135 0.425 ;
    END
  END array_col_bot_right<44>
  PIN array_col_top_right<49>
    ANTENNADIFFAREA 0.870000 ;
    PORT
      LAYER met3 ;
        RECT 942.245 1638.015 943.015 1638.315 ;
    END
  END array_col_top_right<49>
  PIN col_event_rst_top_right<56>
    ANTENNAGATEAREA 4.032000 ;
    PORT
      LAYER met3 ;
        RECT 865.595 1637.895 865.895 1638.195 ;
    END
  END col_event_rst_top_right<56>
  PIN array_col_top_right<50>
    ANTENNADIFFAREA 0.870000 ;
    PORT
      LAYER met3 ;
        RECT 934.365 1638.015 935.135 1638.315 ;
    END
  END array_col_top_right<50>
  PIN array_col_top_right<23>
    ANTENNADIFFAREA 0.870000 ;
    PORT
      LAYER met3 ;
        RECT 1254.245 1638.015 1255.015 1638.315 ;
    END
  END array_col_top_right<23>
  PIN array_col_top_right<51>
    ANTENNADIFFAREA 0.870000 ;
    PORT
      LAYER met3 ;
        RECT 918.245 1638.015 919.015 1638.315 ;
    END
  END array_col_top_right<51>
  PIN array_col_top_right<52>
    ANTENNADIFFAREA 0.870000 ;
    PORT
      LAYER met3 ;
        RECT 910.365 1638.015 911.135 1638.315 ;
    END
  END array_col_top_right<52>
  PIN array_col_top_right<53>
    ANTENNADIFFAREA 0.870000 ;
    PORT
      LAYER met3 ;
        RECT 894.245 1638.015 895.015 1638.315 ;
    END
  END array_col_top_right<53>
  PIN array_col_top_right<54>
    ANTENNADIFFAREA 0.870000 ;
    PORT
      LAYER met3 ;
        RECT 886.365 1638.015 887.135 1638.315 ;
    END
  END array_col_top_right<54>
  PIN array_col_top_right<55>
    ANTENNADIFFAREA 0.870000 ;
    PORT
      LAYER met3 ;
        RECT 870.245 1638.015 871.015 1638.315 ;
    END
  END array_col_top_right<55>
  PIN array_col_top_right<56>
    ANTENNADIFFAREA 0.870000 ;
    PORT
      LAYER met3 ;
        RECT 862.365 1638.015 863.135 1638.315 ;
    END
  END array_col_top_right<56>
  PIN array_col_top_right<57>
    ANTENNADIFFAREA 0.870000 ;
    PORT
      LAYER met3 ;
        RECT 846.245 1638.015 847.015 1638.315 ;
    END
  END array_col_top_right<57>
  PIN array_col_bot_right<45>
    ANTENNADIFFAREA 0.870000 ;
    PORT
      LAYER met3 ;
        RECT 990.245 0.125 991.015 0.425 ;
    END
  END array_col_bot_right<45>
  PIN col_event_rst_bot_right<45>
    ANTENNAGATEAREA 4.032000 ;
    PORT
      LAYER met3 ;
        RECT 987.500 0.245 987.800 0.545 ;
    END
  END col_event_rst_bot_right<45>
  PIN array_col_top_right<58>
    ANTENNADIFFAREA 0.870000 ;
    PORT
      LAYER met3 ;
        RECT 838.365 1638.015 839.135 1638.315 ;
    END
  END array_col_top_right<58>
  PIN array_col_top_right<59>
    ANTENNADIFFAREA 0.870000 ;
    PORT
      LAYER met3 ;
        RECT 822.245 1638.015 823.015 1638.315 ;
    END
  END array_col_top_right<59>
  PIN array_col_top_right<60>
    ANTENNADIFFAREA 0.870000 ;
    PORT
      LAYER met3 ;
        RECT 814.365 1638.015 815.135 1638.315 ;
    END
  END array_col_top_right<60>
  PIN array_col_top_right<24>
    ANTENNADIFFAREA 0.870000 ;
    PORT
      LAYER met3 ;
        RECT 1246.365 1638.015 1247.135 1638.315 ;
    END
  END array_col_top_right<24>
  PIN array_col_top_right<61>
    ANTENNADIFFAREA 0.870000 ;
    PORT
      LAYER met3 ;
        RECT 798.245 1638.015 799.015 1638.315 ;
    END
  END array_col_top_right<61>
  PIN array_col_top_right<62>
    ANTENNADIFFAREA 0.870000 ;
    PORT
      LAYER met3 ;
        RECT 790.365 1638.015 791.135 1638.315 ;
    END
  END array_col_top_right<62>
  PIN array_col_top_right<63>
    ANTENNADIFFAREA 0.870000 ;
    PORT
      LAYER met3 ;
        RECT 774.245 1638.015 775.015 1638.315 ;
    END
  END array_col_top_right<63>
  PIN array_col_top_right<0>
    ANTENNADIFFAREA 0.870000 ;
    PORT
      LAYER met3 ;
        RECT 1534.365 1638.015 1535.135 1638.315 ;
    END
  END array_col_top_right<0>
  PIN array_col_bot_left<42>
    ANTENNADIFFAREA 0.870000 ;
    PORT
      LAYER met3 ;
        RECT 262.365 0.125 263.135 0.425 ;
    END
  END array_col_bot_left<42>
  PIN array_col_bot_left<58>
    ANTENNADIFFAREA 0.870000 ;
    PORT
      LAYER met3 ;
        RECT 70.365 0.125 71.135 0.425 ;
    END
  END array_col_bot_left<58>
  PIN array_col_bot_left<43>
    ANTENNADIFFAREA 0.870000 ;
    PORT
      LAYER met3 ;
        RECT 246.245 0.125 247.015 0.425 ;
    END
  END array_col_bot_left<43>
  PIN array_col_bot_left<44>
    ANTENNADIFFAREA 0.870000 ;
    PORT
      LAYER met3 ;
        RECT 238.365 0.125 239.135 0.425 ;
    END
  END array_col_bot_left<44>
  PIN col_event_rst_top_left<54>
    ANTENNAGATEAREA 4.032000 ;
    PORT
      LAYER met3 ;
        RECT 121.595 1637.895 121.895 1638.195 ;
    END
  END col_event_rst_top_left<54>
  PIN array_col_bot_left<45>
    ANTENNADIFFAREA 0.870000 ;
    PORT
      LAYER met3 ;
        RECT 222.245 0.125 223.015 0.425 ;
    END
  END array_col_bot_left<45>
  PIN col_event_rst_top_left<49>
    ANTENNAGATEAREA 4.032000 ;
    PORT
      LAYER met3 ;
        RECT 171.500 1637.895 171.800 1638.195 ;
    END
  END col_event_rst_top_left<49>
  PIN col_event_rst_top_left<59>
    ANTENNAGATEAREA 4.032000 ;
    PORT
      LAYER met3 ;
        RECT 51.500 1637.895 51.800 1638.195 ;
    END
  END col_event_rst_top_left<59>
  PIN array_col_bot_left<11>
    ANTENNADIFFAREA 0.870000 ;
    PORT
      LAYER met3 ;
        RECT 630.245 0.125 631.015 0.425 ;
    END
  END array_col_bot_left<11>
  PIN col_event_rst_top_left<60>
    ANTENNAGATEAREA 4.032000 ;
    PORT
      LAYER met3 ;
        RECT 49.595 1637.895 49.895 1638.195 ;
    END
  END col_event_rst_top_left<60>
  PIN col_event_rst_bot_left<51>
    ANTENNAGATEAREA 4.032000 ;
    PORT
      LAYER met3 ;
        RECT 147.500 0.245 147.800 0.545 ;
    END
  END col_event_rst_bot_left<51>
  PIN array_col_bot_right<41>
    ANTENNADIFFAREA 0.870000 ;
    PORT
      LAYER met3 ;
        RECT 1038.245 0.125 1039.015 0.425 ;
    END
  END array_col_bot_right<41>
  PIN array_col_bot_left<49>
    ANTENNADIFFAREA 0.870000 ;
    PORT
      LAYER met3 ;
        RECT 174.245 0.125 175.015 0.425 ;
    END
  END array_col_bot_left<49>
  PIN array_col_bot_left<59>
    ANTENNADIFFAREA 0.870000 ;
    PORT
      LAYER met3 ;
        RECT 54.245 0.125 55.015 0.425 ;
    END
  END array_col_bot_left<59>
  PIN array_col_bot_left<12>
    ANTENNADIFFAREA 0.870000 ;
    PORT
      LAYER met3 ;
        RECT 622.365 0.125 623.135 0.425 ;
    END
  END array_col_bot_left<12>
  PIN array_col_bot_left<60>
    ANTENNADIFFAREA 0.870000 ;
    PORT
      LAYER met3 ;
        RECT 46.365 0.125 47.135 0.425 ;
    END
  END array_col_bot_left<60>
  PIN col_event_rst_bot_right<3>
    ANTENNAGATEAREA 4.032000 ;
    PORT
      LAYER met3 ;
        RECT 1491.500 0.245 1491.800 0.545 ;
    END
  END col_event_rst_bot_right<3>
  PIN col_event_rst_bot_right<35>
    ANTENNAGATEAREA 4.032000 ;
    PORT
      LAYER met3 ;
        RECT 1107.500 0.245 1107.800 0.545 ;
    END
  END col_event_rst_bot_right<35>
  PIN col_event_rst_bot_right<4>
    ANTENNAGATEAREA 4.032000 ;
    PORT
      LAYER met3 ;
        RECT 1489.595 0.245 1489.895 0.545 ;
    END
  END col_event_rst_bot_right<4>
  PIN col_event_rst_bot_right<5>
    ANTENNAGATEAREA 4.032000 ;
    PORT
      LAYER met3 ;
        RECT 1467.500 0.245 1467.800 0.545 ;
    END
  END col_event_rst_bot_right<5>
  PIN col_event_rst_bot_right<6>
    ANTENNAGATEAREA 4.032000 ;
    PORT
      LAYER met3 ;
        RECT 1465.595 0.245 1465.895 0.545 ;
    END
  END col_event_rst_bot_right<6>
  PIN col_event_rst_bot_right<7>
    ANTENNAGATEAREA 4.032000 ;
    PORT
      LAYER met3 ;
        RECT 1443.500 0.245 1443.800 0.545 ;
    END
  END col_event_rst_bot_right<7>
  PIN col_event_rst_bot_right<8>
    ANTENNAGATEAREA 4.032000 ;
    PORT
      LAYER met3 ;
        RECT 1441.595 0.245 1441.895 0.545 ;
    END
  END col_event_rst_bot_right<8>
  PIN col_event_rst_bot_right<9>
    ANTENNAGATEAREA 4.032000 ;
    PORT
      LAYER met3 ;
        RECT 1419.500 0.245 1419.800 0.545 ;
    END
  END col_event_rst_bot_right<9>
  PIN col_event_rst_bot_right<10>
    ANTENNAGATEAREA 4.032000 ;
    PORT
      LAYER met3 ;
        RECT 1417.595 0.245 1417.895 0.545 ;
    END
  END col_event_rst_bot_right<10>
  PIN col_event_rst_bot_right<11>
    ANTENNAGATEAREA 4.032000 ;
    PORT
      LAYER met3 ;
        RECT 1395.500 0.245 1395.800 0.545 ;
    END
  END col_event_rst_bot_right<11>
  PIN col_event_rst_bot_right<12>
    ANTENNAGATEAREA 4.032000 ;
    PORT
      LAYER met3 ;
        RECT 1393.595 0.245 1393.895 0.545 ;
    END
  END col_event_rst_bot_right<12>
  PIN col_event_rst_bot_right<36>
    ANTENNAGATEAREA 4.032000 ;
    PORT
      LAYER met3 ;
        RECT 1105.595 0.245 1105.895 0.545 ;
    END
  END col_event_rst_bot_right<36>
  PIN col_event_rst_bot_right<13>
    ANTENNAGATEAREA 4.032000 ;
    PORT
      LAYER met3 ;
        RECT 1371.500 0.245 1371.800 0.545 ;
    END
  END col_event_rst_bot_right<13>
  PIN col_event_rst_bot_right<14>
    ANTENNAGATEAREA 4.032000 ;
    PORT
      LAYER met3 ;
        RECT 1369.595 0.245 1369.895 0.545 ;
    END
  END col_event_rst_bot_right<14>
  PIN col_event_rst_bot_right<15>
    ANTENNAGATEAREA 4.032000 ;
    PORT
      LAYER met3 ;
        RECT 1347.500 0.245 1347.800 0.545 ;
    END
  END col_event_rst_bot_right<15>
  PIN col_event_rst_bot_right<16>
    ANTENNAGATEAREA 4.032000 ;
    PORT
      LAYER met3 ;
        RECT 1345.595 0.245 1345.895 0.545 ;
    END
  END col_event_rst_bot_right<16>
  PIN col_event_rst_bot_right<17>
    ANTENNAGATEAREA 4.032000 ;
    PORT
      LAYER met3 ;
        RECT 1323.500 0.245 1323.800 0.545 ;
    END
  END col_event_rst_bot_right<17>
  PIN col_event_rst_bot_right<18>
    ANTENNAGATEAREA 4.032000 ;
    PORT
      LAYER met3 ;
        RECT 1321.595 0.245 1321.895 0.545 ;
    END
  END col_event_rst_bot_right<18>
  PIN col_event_rst_bot_right<19>
    ANTENNAGATEAREA 4.032000 ;
    PORT
      LAYER met3 ;
        RECT 1299.500 0.245 1299.800 0.545 ;
    END
  END col_event_rst_bot_right<19>
  PIN col_event_rst_bot_right<20>
    ANTENNAGATEAREA 4.032000 ;
    PORT
      LAYER met3 ;
        RECT 1297.595 0.245 1297.895 0.545 ;
    END
  END col_event_rst_bot_right<20>
  PIN col_event_rst_bot_right<21>
    ANTENNAGATEAREA 4.032000 ;
    PORT
      LAYER met3 ;
        RECT 1275.500 0.245 1275.800 0.545 ;
    END
  END col_event_rst_bot_right<21>
  PIN col_event_rst_bot_right<37>
    ANTENNAGATEAREA 4.032000 ;
    PORT
      LAYER met3 ;
        RECT 1083.500 0.245 1083.800 0.545 ;
    END
  END col_event_rst_bot_right<37>
  PIN col_event_rst_bot_right<22>
    ANTENNAGATEAREA 4.032000 ;
    PORT
      LAYER met3 ;
        RECT 1273.595 0.245 1273.895 0.545 ;
    END
  END col_event_rst_bot_right<22>
  PIN col_event_rst_bot_right<23>
    ANTENNAGATEAREA 4.032000 ;
    PORT
      LAYER met3 ;
        RECT 1251.500 0.245 1251.800 0.545 ;
    END
  END col_event_rst_bot_right<23>
  PIN col_event_rst_bot_right<24>
    ANTENNAGATEAREA 4.032000 ;
    PORT
      LAYER met3 ;
        RECT 1249.595 0.245 1249.895 0.545 ;
    END
  END col_event_rst_bot_right<24>
  PIN col_event_rst_bot_right<25>
    ANTENNAGATEAREA 4.032000 ;
    PORT
      LAYER met3 ;
        RECT 1227.500 0.245 1227.800 0.545 ;
    END
  END col_event_rst_bot_right<25>
  PIN col_event_rst_bot_right<26>
    ANTENNAGATEAREA 4.032000 ;
    PORT
      LAYER met3 ;
        RECT 1225.595 0.245 1225.895 0.545 ;
    END
  END col_event_rst_bot_right<26>
  PIN col_event_rst_bot_right<27>
    ANTENNAGATEAREA 4.032000 ;
    PORT
      LAYER met3 ;
        RECT 1203.500 0.245 1203.800 0.545 ;
    END
  END col_event_rst_bot_right<27>
  PIN col_event_rst_bot_right<28>
    ANTENNAGATEAREA 4.032000 ;
    PORT
      LAYER met3 ;
        RECT 1201.595 0.245 1201.895 0.545 ;
    END
  END col_event_rst_bot_right<28>
  PIN col_event_rst_bot_right<29>
    ANTENNAGATEAREA 4.032000 ;
    PORT
      LAYER met3 ;
        RECT 1179.500 0.245 1179.800 0.545 ;
    END
  END col_event_rst_bot_right<29>
  PIN col_event_rst_bot_right<30>
    ANTENNAGATEAREA 4.032000 ;
    PORT
      LAYER met3 ;
        RECT 1177.595 0.245 1177.895 0.545 ;
    END
  END col_event_rst_bot_right<30>
  PIN col_event_rst_bot_right<38>
    ANTENNAGATEAREA 4.032000 ;
    PORT
      LAYER met3 ;
        RECT 1081.595 0.245 1081.895 0.545 ;
    END
  END col_event_rst_bot_right<38>
  PIN col_event_rst_bot_left<56>
    ANTENNAGATEAREA 4.032000 ;
    PORT
      LAYER met3 ;
        RECT 97.595 0.245 97.895 0.545 ;
    END
  END col_event_rst_bot_left<56>
  PIN col_event_rst_bot_left<57>
    ANTENNAGATEAREA 4.032000 ;
    PORT
      LAYER met3 ;
        RECT 75.500 0.245 75.800 0.545 ;
    END
  END col_event_rst_bot_left<57>
  PIN col_event_rst_bot_left<58>
    ANTENNAGATEAREA 4.032000 ;
    PORT
      LAYER met3 ;
        RECT 73.595 0.245 73.895 0.545 ;
    END
  END col_event_rst_bot_left<58>
  PIN col_event_rst_bot_left<59>
    ANTENNAGATEAREA 4.032000 ;
    PORT
      LAYER met3 ;
        RECT 51.500 0.245 51.800 0.545 ;
    END
  END col_event_rst_bot_left<59>
  PIN col_event_rst_bot_left<60>
    ANTENNAGATEAREA 4.032000 ;
    PORT
      LAYER met3 ;
        RECT 49.595 0.245 49.895 0.545 ;
    END
  END col_event_rst_bot_left<60>
  PIN col_event_rst_bot_left<61>
    ANTENNAGATEAREA 4.032000 ;
    PORT
      LAYER met3 ;
        RECT 27.500 0.245 27.800 0.545 ;
    END
  END col_event_rst_bot_left<61>
  PIN col_event_rst_bot_left<62>
    ANTENNAGATEAREA 4.032000 ;
    PORT
      LAYER met3 ;
        RECT 25.595 0.245 25.895 0.545 ;
    END
  END col_event_rst_bot_left<62>
  PIN array_col_bot_left<61>
    ANTENNADIFFAREA 0.870000 ;
    PORT
      LAYER met3 ;
        RECT 30.245 0.125 31.015 0.425 ;
    END
  END array_col_bot_left<61>
  PIN array_col_bot_left<62>
    ANTENNADIFFAREA 0.870000 ;
    PORT
      LAYER met3 ;
        RECT 22.365 0.125 23.135 0.425 ;
    END
  END array_col_bot_left<62>
  PIN array_col_bot_left<7>
    ANTENNADIFFAREA 0.870000 ;
    PORT
      LAYER met3 ;
        RECT 678.245 0.125 679.015 0.425 ;
    END
  END array_col_bot_left<7>
  PIN array_col_bot_left<13>
    ANTENNADIFFAREA 0.870000 ;
    PORT
      LAYER met3 ;
        RECT 606.245 0.125 607.015 0.425 ;
    END
  END array_col_bot_left<13>
  PIN array_col_bot_left<14>
    ANTENNADIFFAREA 0.870000 ;
    PORT
      LAYER met3 ;
        RECT 598.365 0.125 599.135 0.425 ;
    END
  END array_col_bot_left<14>
  PIN col_event_rst_top_left<51>
    ANTENNAGATEAREA 4.032000 ;
    PORT
      LAYER met3 ;
        RECT 147.500 1637.895 147.800 1638.195 ;
    END
  END col_event_rst_top_left<51>
  PIN array_col_bot_left<55>
    ANTENNADIFFAREA 0.870000 ;
    PORT
      LAYER met3 ;
        RECT 102.245 0.125 103.015 0.425 ;
    END
  END array_col_bot_left<55>
  PIN array_col_bot_right<48>
    ANTENNADIFFAREA 0.870000 ;
    PORT
      LAYER met3 ;
        RECT 958.365 0.125 959.135 0.425 ;
    END
  END array_col_bot_right<48>
  PIN array_col_bot_right<8>
    ANTENNADIFFAREA 0.870000 ;
    PORT
      LAYER met3 ;
        RECT 1438.365 0.125 1439.135 0.425 ;
    END
  END array_col_bot_right<8>
  PIN array_col_bot_right<9>
    ANTENNADIFFAREA 0.870000 ;
    PORT
      LAYER met3 ;
        RECT 1422.245 0.125 1423.015 0.425 ;
    END
  END array_col_bot_right<9>
  PIN array_col_bot_right<10>
    ANTENNADIFFAREA 0.870000 ;
    PORT
      LAYER met3 ;
        RECT 1414.365 0.125 1415.135 0.425 ;
    END
  END array_col_bot_right<10>
  PIN array_col_bot_right<11>
    ANTENNADIFFAREA 0.870000 ;
    PORT
      LAYER met3 ;
        RECT 1398.245 0.125 1399.015 0.425 ;
    END
  END array_col_bot_right<11>
  PIN array_col_bot_right<12>
    ANTENNADIFFAREA 0.870000 ;
    PORT
      LAYER met3 ;
        RECT 1390.365 0.125 1391.135 0.425 ;
    END
  END array_col_bot_right<12>
  PIN array_col_bot_right<13>
    ANTENNADIFFAREA 0.870000 ;
    PORT
      LAYER met3 ;
        RECT 1374.245 0.125 1375.015 0.425 ;
    END
  END array_col_bot_right<13>
  PIN array_col_bot_right<14>
    ANTENNADIFFAREA 0.870000 ;
    PORT
      LAYER met3 ;
        RECT 1366.365 0.125 1367.135 0.425 ;
    END
  END array_col_bot_right<14>
  PIN array_col_bot_right<15>
    ANTENNADIFFAREA 0.870000 ;
    PORT
      LAYER met3 ;
        RECT 1350.245 0.125 1351.015 0.425 ;
    END
  END array_col_bot_right<15>
  PIN array_col_bot_right<16>
    ANTENNADIFFAREA 0.870000 ;
    PORT
      LAYER met3 ;
        RECT 1342.365 0.125 1343.135 0.425 ;
    END
  END array_col_bot_right<16>
  PIN array_col_bot_left<51>
    ANTENNADIFFAREA 0.870000 ;
    PORT
      LAYER met3 ;
        RECT 150.245 0.125 151.015 0.425 ;
    END
  END array_col_bot_left<51>
  PIN array_col_bot_right<17>
    ANTENNADIFFAREA 0.870000 ;
    PORT
      LAYER met3 ;
        RECT 1326.245 0.125 1327.015 0.425 ;
    END
  END array_col_bot_right<17>
  PIN col_event_rst_bot_right<63>
    ANTENNAGATEAREA 4.032000 ;
    PORT
      LAYER met3 ;
        RECT 771.500 0.245 771.800 0.545 ;
    END
  END col_event_rst_bot_right<63>
  PIN array_col_bot_right<49>
    ANTENNADIFFAREA 0.870000 ;
    PORT
      LAYER met3 ;
        RECT 942.245 0.125 943.015 0.425 ;
    END
  END array_col_bot_right<49>
  PIN array_col_bot_right<46>
    ANTENNADIFFAREA 0.870000 ;
    PORT
      LAYER met3 ;
        RECT 982.365 0.125 983.135 0.425 ;
    END
  END array_col_bot_right<46>
  PIN col_event_rst_bot_right<0>
    ANTENNAGATEAREA 4.032000 ;
    PORT
      LAYER met3 ;
        RECT 1537.595 0.245 1537.895 0.545 ;
    END
  END col_event_rst_bot_right<0>
  PIN array_col_top_right<17>
    ANTENNADIFFAREA 0.870000 ;
    PORT
      LAYER met3 ;
        RECT 1326.245 1638.015 1327.015 1638.315 ;
    END
  END array_col_top_right<17>
  PIN array_col_top_right<18>
    ANTENNADIFFAREA 0.870000 ;
    PORT
      LAYER met3 ;
        RECT 1318.365 1638.015 1319.135 1638.315 ;
    END
  END array_col_top_right<18>
  PIN array_col_top_right<19>
    ANTENNADIFFAREA 0.870000 ;
    PORT
      LAYER met3 ;
        RECT 1302.245 1638.015 1303.015 1638.315 ;
    END
  END array_col_top_right<19>
  PIN col_event_rst_top_right<45>
    ANTENNAGATEAREA 4.032000 ;
    PORT
      LAYER met3 ;
        RECT 987.500 1637.895 987.800 1638.195 ;
    END
  END col_event_rst_top_right<45>
  PIN array_col_top_left<38>
    ANTENNADIFFAREA 0.870000 ;
    PORT
      LAYER met3 ;
        RECT 310.365 1638.015 311.135 1638.315 ;
    END
  END array_col_top_left<38>
  PIN array_col_bot_right<18>
    ANTENNADIFFAREA 0.870000 ;
    PORT
      LAYER met3 ;
        RECT 1318.365 0.125 1319.135 0.425 ;
    END
  END array_col_bot_right<18>
  PIN array_col_bot_right<19>
    ANTENNADIFFAREA 0.870000 ;
    PORT
      LAYER met3 ;
        RECT 1302.245 0.125 1303.015 0.425 ;
    END
  END array_col_bot_right<19>
  PIN array_col_bot_right<20>
    ANTENNADIFFAREA 0.870000 ;
    PORT
      LAYER met3 ;
        RECT 1294.365 0.125 1295.135 0.425 ;
    END
  END array_col_bot_right<20>
  PIN array_col_bot_right<21>
    ANTENNADIFFAREA 0.870000 ;
    PORT
      LAYER met3 ;
        RECT 1278.245 0.125 1279.015 0.425 ;
    END
  END array_col_bot_right<21>
  PIN array_col_bot_right<22>
    ANTENNADIFFAREA 0.870000 ;
    PORT
      LAYER met3 ;
        RECT 1270.365 0.125 1271.135 0.425 ;
    END
  END array_col_bot_right<22>
  PIN array_col_bot_right<23>
    ANTENNADIFFAREA 0.870000 ;
    PORT
      LAYER met3 ;
        RECT 1254.245 0.125 1255.015 0.425 ;
    END
  END array_col_bot_right<23>
  PIN array_col_bot_right<24>
    ANTENNADIFFAREA 0.870000 ;
    PORT
      LAYER met3 ;
        RECT 1246.365 0.125 1247.135 0.425 ;
    END
  END array_col_bot_right<24>
  PIN array_col_bot_right<1>
    ANTENNADIFFAREA 0.870000 ;
    PORT
      LAYER met3 ;
        RECT 1518.245 0.125 1519.015 0.425 ;
    END
  END array_col_bot_right<1>
  PIN array_col_bot_right<25>
    ANTENNADIFFAREA 0.870000 ;
    PORT
      LAYER met3 ;
        RECT 1230.245 0.125 1231.015 0.425 ;
    END
  END array_col_bot_right<25>
  PIN array_col_bot_right<26>
    ANTENNADIFFAREA 0.870000 ;
    PORT
      LAYER met3 ;
        RECT 1222.365 0.125 1223.135 0.425 ;
    END
  END array_col_bot_right<26>
  PIN array_col_bot_left<52>
    ANTENNADIFFAREA 0.870000 ;
    PORT
      LAYER met3 ;
        RECT 142.365 0.125 143.135 0.425 ;
    END
  END array_col_bot_left<52>
  PIN array_col_bot_right<27>
    ANTENNADIFFAREA 0.870000 ;
    PORT
      LAYER met3 ;
        RECT 1206.245 0.125 1207.015 0.425 ;
    END
  END array_col_bot_right<27>
  PIN array_col_bot_right<28>
    ANTENNADIFFAREA 0.870000 ;
    PORT
      LAYER met3 ;
        RECT 1198.365 0.125 1199.135 0.425 ;
    END
  END array_col_bot_right<28>
  PIN array_col_bot_right<29>
    ANTENNADIFFAREA 0.870000 ;
    PORT
      LAYER met3 ;
        RECT 1182.245 0.125 1183.015 0.425 ;
    END
  END array_col_bot_right<29>
  PIN array_col_bot_right<30>
    ANTENNADIFFAREA 0.870000 ;
    PORT
      LAYER met3 ;
        RECT 1174.365 0.125 1175.135 0.425 ;
    END
  END array_col_bot_right<30>
  PIN array_col_bot_right<31>
    ANTENNADIFFAREA 0.870000 ;
    PORT
      LAYER met3 ;
        RECT 1158.245 0.125 1159.015 0.425 ;
    END
  END array_col_bot_right<31>
  PIN array_col_bot_right<32>
    ANTENNADIFFAREA 0.870000 ;
    PORT
      LAYER met3 ;
        RECT 1150.365 0.125 1151.135 0.425 ;
    END
  END array_col_bot_right<32>
  PIN array_col_bot_right<2>
    ANTENNADIFFAREA 0.870000 ;
    PORT
      LAYER met3 ;
        RECT 1510.365 0.125 1511.135 0.425 ;
    END
  END array_col_bot_right<2>
  PIN array_col_bot_right<33>
    ANTENNADIFFAREA 0.870000 ;
    PORT
      LAYER met3 ;
        RECT 1134.245 0.125 1135.015 0.425 ;
    END
  END array_col_bot_right<33>
  PIN array_col_bot_right<34>
    ANTENNADIFFAREA 0.870000 ;
    PORT
      LAYER met3 ;
        RECT 1126.365 0.125 1127.135 0.425 ;
    END
  END array_col_bot_right<34>
  PIN array_col_bot_left<20>
    ANTENNADIFFAREA 0.870000 ;
    PORT
      LAYER met3 ;
        RECT 526.365 0.125 527.135 0.425 ;
    END
  END array_col_bot_left<20>
  PIN array_col_bot_left<21>
    ANTENNADIFFAREA 0.870000 ;
    PORT
      LAYER met3 ;
        RECT 510.245 0.125 511.015 0.425 ;
    END
  END array_col_bot_left<21>
  PIN array_col_bot_left<22>
    ANTENNADIFFAREA 0.870000 ;
    PORT
      LAYER met3 ;
        RECT 502.365 0.125 503.135 0.425 ;
    END
  END array_col_bot_left<22>
  PIN array_col_bot_left<23>
    ANTENNADIFFAREA 0.870000 ;
    PORT
      LAYER met3 ;
        RECT 486.245 0.125 487.015 0.425 ;
    END
  END array_col_bot_left<23>
  PIN array_col_bot_left<24>
    ANTENNADIFFAREA 0.870000 ;
    PORT
      LAYER met3 ;
        RECT 478.365 0.125 479.135 0.425 ;
    END
  END array_col_bot_left<24>
  PIN array_col_bot_left<8>
    ANTENNADIFFAREA 0.870000 ;
    PORT
      LAYER met3 ;
        RECT 670.365 0.125 671.135 0.425 ;
    END
  END array_col_bot_left<8>
  PIN array_col_bot_left<56>
    ANTENNADIFFAREA 0.870000 ;
    PORT
      LAYER met3 ;
        RECT 94.365 0.125 95.135 0.425 ;
    END
  END array_col_bot_left<56>
  PIN row_off_detect_top<57>
    ANTENNAGATEAREA 8.064000 ;
    PORT
      LAYER met2 ;
        RECT 2.690 901.850 2.950 902.110 ;
    END
  END row_off_detect_top<57>
  PIN row_on_detect_bot<15>
    ANTENNAGATEAREA 16.128000 ;
    PORT
      LAYER met2 ;
        RECT 2.690 638.250 2.950 638.510 ;
    END
  END row_on_detect_bot<15>
  PIN row_on_detect_bot<41>
    ANTENNAGATEAREA 16.128000 ;
    PORT
      LAYER met2 ;
        RECT 2.690 326.250 2.950 326.510 ;
    END
  END row_on_detect_bot<41>
  PIN detect_pulse_global_top_left
    ANTENNAGATEAREA 147.199997 ;
    PORT
      LAYER met2 ;
        RECT 770.690 1619.020 770.990 1620.020 ;
    END
  END detect_pulse_global_top_left
  PIN row_off_detect_top<23>
    ANTENNAGATEAREA 8.064000 ;
    PORT
      LAYER met2 ;
        RECT 2.690 1309.850 2.950 1310.110 ;
    END
  END row_off_detect_top<23>
  PIN row_off_detect_top<21>
    ANTENNAGATEAREA 8.064000 ;
    PORT
      LAYER met2 ;
        RECT 2.690 1333.850 2.950 1334.110 ;
    END
  END row_off_detect_top<21>
  PIN row_off_detect_top<20>
    ANTENNAGATEAREA 8.064000 ;
    PORT
      LAYER met2 ;
        RECT 2.690 1336.330 2.950 1336.590 ;
    END
  END row_off_detect_top<20>
  PIN row_on_detect_bot<40>
    ANTENNAGATEAREA 16.128000 ;
    PORT
      LAYER met2 ;
        RECT 2.690 327.930 2.950 328.190 ;
    END
  END row_on_detect_bot<40>
  PIN row_on_detect_bot<59>
    ANTENNAGATEAREA 16.128000 ;
    PORT
      LAYER met2 ;
        RECT 2.690 110.250 2.950 110.510 ;
    END
  END row_on_detect_bot<59>
  PIN row_off_detect_top<3>
    ANTENNAGATEAREA 8.064000 ;
    PORT
      LAYER met2 ;
        RECT 2.690 1549.850 2.950 1550.110 ;
    END
  END row_off_detect_top<3>
  PIN row_off_detect_top<4>
    ANTENNAGATEAREA 8.064000 ;
    PORT
      LAYER met2 ;
        RECT 2.690 1528.330 2.950 1528.590 ;
    END
  END row_off_detect_top<4>
  PIN row_off_detect_bot<30>
    ANTENNAGATEAREA 8.064000 ;
    PORT
      LAYER met2 ;
        RECT 2.690 448.330 2.950 448.590 ;
    END
  END row_off_detect_bot<30>
  PIN row_off_detect_top<59>
    ANTENNAGATEAREA 8.064000 ;
    PORT
      LAYER met2 ;
        RECT 2.690 877.850 2.950 878.110 ;
    END
  END row_off_detect_top<59>
  PIN row_off_detect_bot<59>
    ANTENNAGATEAREA 8.064000 ;
    PORT
      LAYER met2 ;
        RECT 2.690 109.850 2.950 110.110 ;
    END
  END row_off_detect_bot<59>
  PIN row_off_detect_top<14>
    ANTENNAGATEAREA 8.064000 ;
    PORT
      LAYER met2 ;
        RECT 2.690 1408.330 2.950 1408.590 ;
    END
  END row_off_detect_top<14>
  PIN row_off_detect_bot<33>
    ANTENNAGATEAREA 8.064000 ;
    PORT
      LAYER met2 ;
        RECT 2.690 421.850 2.950 422.110 ;
    END
  END row_off_detect_bot<33>
  PIN row_off_detect_top<62>
    ANTENNAGATEAREA 8.064000 ;
    PORT
      LAYER met2 ;
        RECT 2.690 832.330 2.950 832.590 ;
    END
  END row_off_detect_top<62>
  PIN row_off_detect_bot<35>
    ANTENNAGATEAREA 8.064000 ;
    PORT
      LAYER met2 ;
        RECT 2.690 397.850 2.950 398.110 ;
    END
  END row_off_detect_bot<35>
  PIN row_off_detect_top<18>
    ANTENNAGATEAREA 8.064000 ;
    PORT
      LAYER met2 ;
        RECT 2.690 1360.330 2.950 1360.590 ;
    END
  END row_off_detect_top<18>
  PIN row_off_detect_bot<37>
    ANTENNAGATEAREA 8.064000 ;
    PORT
      LAYER met2 ;
        RECT 2.690 373.850 2.950 374.110 ;
    END
  END row_off_detect_bot<37>
  PIN row_on_detect_top<1>
    ANTENNAGATEAREA 16.128000 ;
    PORT
      LAYER met2 ;
        RECT 2.690 1574.250 2.950 1574.510 ;
    END
  END row_on_detect_top<1>
  PIN row_off_detect_bot<38>
    ANTENNAGATEAREA 8.064000 ;
    PORT
      LAYER met2 ;
        RECT 2.690 352.330 2.950 352.590 ;
    END
  END row_off_detect_bot<38>
  PIN row_on_detect_top<3>
    ANTENNAGATEAREA 16.128000 ;
    PORT
      LAYER met2 ;
        RECT 2.690 1550.250 2.950 1550.510 ;
    END
  END row_on_detect_top<3>
  PIN row_off_detect_bot<40>
    ANTENNAGATEAREA 8.064000 ;
    PORT
      LAYER met2 ;
        RECT 2.690 328.330 2.950 328.590 ;
    END
  END row_off_detect_bot<40>
  PIN row_on_detect_top<5>
    ANTENNAGATEAREA 16.128000 ;
    PORT
      LAYER met2 ;
        RECT 2.690 1526.250 2.950 1526.510 ;
    END
  END row_on_detect_top<5>
  PIN row_off_detect_bot<60>
    ANTENNAGATEAREA 8.064000 ;
    PORT
      LAYER met2 ;
        RECT 2.690 88.330 2.950 88.590 ;
    END
  END row_off_detect_bot<60>
  PIN row_on_detect_top<20>
    ANTENNAGATEAREA 16.128000 ;
    PORT
      LAYER met2 ;
        RECT 2.690 1335.930 2.950 1336.190 ;
    END
  END row_on_detect_top<20>
  PIN row_off_detect_bot<43>
    ANTENNAGATEAREA 8.064000 ;
    PORT
      LAYER met2 ;
        RECT 2.690 301.850 2.950 302.110 ;
    END
  END row_off_detect_bot<43>
  PIN row_off_detect_bot<45>
    ANTENNAGATEAREA 8.064000 ;
    PORT
      LAYER met2 ;
        RECT 2.690 277.850 2.950 278.110 ;
    END
  END row_off_detect_bot<45>
  PIN row_off_detect_top<11>
    ANTENNAGATEAREA 8.064000 ;
    PORT
      LAYER met2 ;
        RECT 2.690 1453.850 2.950 1454.110 ;
    END
  END row_off_detect_top<11>
  PIN row_off_detect_top<7>
    ANTENNAGATEAREA 8.064000 ;
    PORT
      LAYER met2 ;
        RECT 2.690 1501.850 2.950 1502.110 ;
    END
  END row_off_detect_top<7>
  PIN row_off_detect_bot<8>
    ANTENNAGATEAREA 8.064000 ;
    PORT
      LAYER met2 ;
        RECT 2.690 712.330 2.950 712.590 ;
    END
  END row_off_detect_bot<8>
  PIN row_off_detect_bot<48>
    ANTENNAGATEAREA 8.064000 ;
    PORT
      LAYER met2 ;
        RECT 2.690 232.330 2.950 232.590 ;
    END
  END row_off_detect_bot<48>
  PIN row_off_detect_bot<10>
    ANTENNAGATEAREA 8.064000 ;
    PORT
      LAYER met2 ;
        RECT 2.690 688.330 2.950 688.590 ;
    END
  END row_off_detect_bot<10>
  PIN row_off_detect_bot<50>
    ANTENNAGATEAREA 8.064000 ;
    PORT
      LAYER met2 ;
        RECT 2.690 208.330 2.950 208.590 ;
    END
  END row_off_detect_bot<50>
  PIN row_off_detect_bot<11>
    ANTENNAGATEAREA 8.064000 ;
    PORT
      LAYER met2 ;
        RECT 2.690 685.850 2.950 686.110 ;
    END
  END row_off_detect_bot<11>
  PIN row_off_detect_bot<62>
    ANTENNAGATEAREA 8.064000 ;
    PORT
      LAYER met2 ;
        RECT 2.690 64.330 2.950 64.590 ;
    END
  END row_off_detect_bot<62>
  PIN row_off_detect_bot<12>
    ANTENNAGATEAREA 8.064000 ;
    PORT
      LAYER met2 ;
        RECT 2.690 664.330 2.950 664.590 ;
    END
  END row_off_detect_bot<12>
  PIN row_off_detect_bot<14>
    ANTENNAGATEAREA 8.064000 ;
    PORT
      LAYER met2 ;
        RECT 2.690 640.330 2.950 640.590 ;
    END
  END row_off_detect_bot<14>
  PIN row_on_detect_top<22>
    ANTENNAGATEAREA 16.128000 ;
    PORT
      LAYER met2 ;
        RECT 2.690 1311.930 2.950 1312.190 ;
    END
  END row_on_detect_top<22>
  PIN row_off_detect_bot<16>
    ANTENNAGATEAREA 8.064000 ;
    PORT
      LAYER met2 ;
        RECT 2.690 616.330 2.950 616.590 ;
    END
  END row_off_detect_bot<16>
  PIN row_off_detect_bot<18>
    ANTENNAGATEAREA 8.064000 ;
    PORT
      LAYER met2 ;
        RECT 2.690 592.330 2.950 592.590 ;
    END
  END row_off_detect_bot<18>
  PIN row_off_detect_bot<21>
    ANTENNAGATEAREA 8.064000 ;
    PORT
      LAYER met2 ;
        RECT 2.690 565.850 2.950 566.110 ;
    END
  END row_off_detect_bot<21>
  PIN row_off_detect_bot<22>
    ANTENNAGATEAREA 8.064000 ;
    PORT
      LAYER met2 ;
        RECT 2.690 544.330 2.950 544.590 ;
    END
  END row_off_detect_bot<22>
  PIN row_off_detect_bot<24>
    ANTENNAGATEAREA 8.064000 ;
    PORT
      LAYER met2 ;
        RECT 2.690 520.330 2.950 520.590 ;
    END
  END row_off_detect_bot<24>
  PIN row_off_detect_bot<26>
    ANTENNAGATEAREA 8.064000 ;
    PORT
      LAYER met2 ;
        RECT 2.690 496.330 2.950 496.590 ;
    END
  END row_off_detect_bot<26>
  PIN row_off_detect_top<55>
    ANTENNAGATEAREA 8.064000 ;
    PORT
      LAYER met2 ;
        RECT 2.690 925.850 2.950 926.110 ;
    END
  END row_off_detect_top<55>
  PIN row_off_detect_top<56>
    ANTENNAGATEAREA 8.064000 ;
    PORT
      LAYER met2 ;
        RECT 2.690 904.330 2.950 904.590 ;
    END
  END row_off_detect_top<56>
  PIN row_off_detect_top<53>
    ANTENNAGATEAREA 8.064000 ;
    PORT
      LAYER met2 ;
        RECT 2.690 949.850 2.950 950.110 ;
    END
  END row_off_detect_top<53>
  PIN row_off_detect_top<17>
    ANTENNAGATEAREA 8.064000 ;
    PORT
      LAYER met2 ;
        RECT 2.690 1381.850 2.950 1382.110 ;
    END
  END row_off_detect_top<17>
  PIN ndetect_pulse_global_top_left
    ANTENNAGATEAREA 64.000000 ;
    PORT
      LAYER met2 ;
        RECT 770.690 1627.550 770.990 1628.550 ;
    END
  END ndetect_pulse_global_top_left
  PIN row_on_detect_top<6>
    ANTENNAGATEAREA 16.128000 ;
    PORT
      LAYER met2 ;
        RECT 2.690 1503.930 2.950 1504.190 ;
    END
  END row_on_detect_top<6>
  PIN row_on_detect_top<63>
    ANTENNAGATEAREA 16.128000 ;
    PORT
      LAYER met2 ;
        RECT 2.690 830.250 2.950 830.510 ;
    END
  END row_on_detect_top<63>
  PIN row_on_detect_top<0>
    ANTENNAGATEAREA 16.128000 ;
    PORT
      LAYER met2 ;
        RECT 2.690 1575.930 2.950 1576.190 ;
    END
  END row_on_detect_top<0>
  PIN row_off_detect_top<13>
    ANTENNAGATEAREA 8.064000 ;
    PORT
      LAYER met2 ;
        RECT 2.690 1429.850 2.950 1430.110 ;
    END
  END row_off_detect_top<13>
  PIN row_off_detect_top<25>
    ANTENNAGATEAREA 8.064000 ;
    PORT
      LAYER met2 ;
        RECT 2.690 1285.850 2.950 1286.110 ;
    END
  END row_off_detect_top<25>
  PIN row_off_detect_top<26>
    ANTENNAGATEAREA 8.064000 ;
    PORT
      LAYER met2 ;
        RECT 2.690 1264.330 2.950 1264.590 ;
    END
  END row_off_detect_top<26>
  PIN row_off_detect_top<28>
    ANTENNAGATEAREA 8.064000 ;
    PORT
      LAYER met2 ;
        RECT 2.690 1240.330 2.950 1240.590 ;
    END
  END row_off_detect_top<28>
  PIN row_off_detect_top<29>
    ANTENNAGATEAREA 8.064000 ;
    PORT
      LAYER met2 ;
        RECT 2.690 1237.850 2.950 1238.110 ;
    END
  END row_off_detect_top<29>
  PIN row_off_detect_top<32>
    ANTENNAGATEAREA 8.064000 ;
    PORT
      LAYER met2 ;
        RECT 2.690 1192.330 2.950 1192.590 ;
    END
  END row_off_detect_top<32>
  PIN row_off_detect_top<33>
    ANTENNAGATEAREA 8.064000 ;
    PORT
      LAYER met2 ;
        RECT 2.690 1189.850 2.950 1190.110 ;
    END
  END row_off_detect_top<33>
  PIN row_off_detect_top<34>
    ANTENNAGATEAREA 8.064000 ;
    PORT
      LAYER met2 ;
        RECT 2.690 1168.330 2.950 1168.590 ;
    END
  END row_off_detect_top<34>
  PIN row_on_detect_top<28>
    ANTENNAGATEAREA 16.128000 ;
    PORT
      LAYER met2 ;
        RECT 2.690 1239.930 2.950 1240.190 ;
    END
  END row_on_detect_top<28>
  PIN row_off_detect_top<37>
    ANTENNAGATEAREA 8.064000 ;
    PORT
      LAYER met2 ;
        RECT 2.690 1141.850 2.950 1142.110 ;
    END
  END row_off_detect_top<37>
  PIN row_off_detect_top<38>
    ANTENNAGATEAREA 8.064000 ;
    PORT
      LAYER met2 ;
        RECT 2.690 1120.330 2.950 1120.590 ;
    END
  END row_off_detect_top<38>
  PIN row_off_detect_top<41>
    ANTENNAGATEAREA 8.064000 ;
    PORT
      LAYER met2 ;
        RECT 2.690 1093.850 2.950 1094.110 ;
    END
  END row_off_detect_top<41>
  PIN row_off_detect_top<42>
    ANTENNAGATEAREA 8.064000 ;
    PORT
      LAYER met2 ;
        RECT 2.690 1072.330 2.950 1072.590 ;
    END
  END row_off_detect_top<42>
  PIN pre_charge_global_bot_left
    ANTENNAGATEAREA 1024.000000 ;
    PORT
      LAYER met2 ;
        RECT 2.690 29.970 2.990 30.980 ;
    END
  END pre_charge_global_bot_left
  PIN row_off_detect_top<16>
    ANTENNAGATEAREA 8.064000 ;
    PORT
      LAYER met2 ;
        RECT 2.690 1384.330 2.950 1384.590 ;
    END
  END row_off_detect_top<16>
  PIN row_off_detect_top<46>
    ANTENNAGATEAREA 8.064000 ;
    PORT
      LAYER met2 ;
        RECT 2.690 1024.330 2.950 1024.590 ;
    END
  END row_off_detect_top<46>
  PIN row_off_detect_top<47>
    ANTENNAGATEAREA 8.064000 ;
    PORT
      LAYER met2 ;
        RECT 2.690 1021.850 2.950 1022.110 ;
    END
  END row_off_detect_top<47>
  PIN row_off_detect_top<50>
    ANTENNAGATEAREA 8.064000 ;
    PORT
      LAYER met2 ;
        RECT 2.690 976.330 2.950 976.590 ;
    END
  END row_off_detect_top<50>
  PIN row_off_detect_top<51>
    ANTENNAGATEAREA 8.064000 ;
    PORT
      LAYER met2 ;
        RECT 2.690 973.850 2.950 974.110 ;
    END
  END row_off_detect_top<51>
  PIN row_off_detect_bot<28>
    ANTENNAGATEAREA 8.064000 ;
    PORT
      LAYER met2 ;
        RECT 2.690 472.330 2.950 472.590 ;
    END
  END row_off_detect_bot<28>
  PIN row_off_detect_bot<29>
    ANTENNAGATEAREA 8.064000 ;
    PORT
      LAYER met2 ;
        RECT 2.690 469.850 2.950 470.110 ;
    END
  END row_off_detect_bot<29>
  PIN row_on_detect_bot<16>
    ANTENNAGATEAREA 16.128000 ;
    PORT
      LAYER met2 ;
        RECT 2.690 615.930 2.950 616.190 ;
    END
  END row_on_detect_bot<16>
  PIN row_on_detect_bot<14>
    ANTENNAGATEAREA 16.128000 ;
    PORT
      LAYER met2 ;
        RECT 2.690 639.930 2.950 640.190 ;
    END
  END row_on_detect_bot<14>
  PIN row_on_detect_top<15>
    ANTENNAGATEAREA 16.128000 ;
    PORT
      LAYER met2 ;
        RECT 2.690 1406.250 2.950 1406.510 ;
    END
  END row_on_detect_top<15>
  PIN row_on_detect_bot<61>
    ANTENNAGATEAREA 16.128000 ;
    PORT
      LAYER met2 ;
        RECT 2.690 86.250 2.950 86.510 ;
    END
  END row_on_detect_bot<61>
  PIN row_off_detect_top<22>
    ANTENNAGATEAREA 8.064000 ;
    PORT
      LAYER met2 ;
        RECT 2.690 1312.330 2.950 1312.590 ;
    END
  END row_off_detect_top<22>
  PIN row_on_detect_bot<1>
    ANTENNAGATEAREA 16.128000 ;
    PORT
      LAYER met2 ;
        RECT 2.690 806.250 2.950 806.510 ;
    END
  END row_on_detect_bot<1>
  PIN row_on_detect_bot<60>
    ANTENNAGATEAREA 16.128000 ;
    PORT
      LAYER met2 ;
        RECT 2.690 87.930 2.950 88.190 ;
    END
  END row_on_detect_bot<60>
  PIN row_on_detect_bot<58>
    ANTENNAGATEAREA 16.128000 ;
    PORT
      LAYER met2 ;
        RECT 2.690 111.930 2.950 112.190 ;
    END
  END row_on_detect_bot<58>
  PIN row_on_detect_bot<57>
    ANTENNAGATEAREA 16.128000 ;
    PORT
      LAYER met2 ;
        RECT 2.690 134.250 2.950 134.510 ;
    END
  END row_on_detect_bot<57>
  PIN row_off_detect_top<2>
    ANTENNAGATEAREA 8.064000 ;
    PORT
      LAYER met2 ;
        RECT 2.690 1552.330 2.950 1552.590 ;
    END
  END row_off_detect_top<2>
  PIN row_off_detect_bot<31>
    ANTENNAGATEAREA 8.064000 ;
    PORT
      LAYER met2 ;
        RECT 2.690 445.850 2.950 446.110 ;
    END
  END row_off_detect_bot<31>
  PIN row_off_detect_top<58>
    ANTENNAGATEAREA 8.064000 ;
    PORT
      LAYER met2 ;
        RECT 2.690 880.330 2.950 880.590 ;
    END
  END row_off_detect_top<58>
  PIN row_off_detect_bot<32>
    ANTENNAGATEAREA 8.064000 ;
    PORT
      LAYER met2 ;
        RECT 2.690 424.330 2.950 424.590 ;
    END
  END row_off_detect_bot<32>
  PIN row_off_detect_top<60>
    ANTENNAGATEAREA 8.064000 ;
    PORT
      LAYER met2 ;
        RECT 2.690 856.330 2.950 856.590 ;
    END
  END row_off_detect_top<60>
  PIN row_off_detect_bot<34>
    ANTENNAGATEAREA 8.064000 ;
    PORT
      LAYER met2 ;
        RECT 2.690 400.330 2.950 400.590 ;
    END
  END row_off_detect_bot<34>
  PIN row_off_detect_top<61>
    ANTENNAGATEAREA 8.064000 ;
    PORT
      LAYER met2 ;
        RECT 2.690 853.850 2.950 854.110 ;
    END
  END row_off_detect_top<61>
  PIN row_off_detect_bot<36>
    ANTENNAGATEAREA 8.064000 ;
    PORT
      LAYER met2 ;
        RECT 2.690 376.330 2.950 376.590 ;
    END
  END row_off_detect_bot<36>
  PIN row_off_detect_top<63>
    ANTENNAGATEAREA 8.064000 ;
    PORT
      LAYER met2 ;
        RECT 2.690 829.850 2.950 830.110 ;
    END
  END row_off_detect_top<63>
  PIN row_off_detect_top<8>
    ANTENNAGATEAREA 8.064000 ;
    PORT
      LAYER met2 ;
        RECT 2.690 1480.330 2.950 1480.590 ;
    END
  END row_off_detect_top<8>
  PIN row_off_detect_top<0>
    ANTENNAGATEAREA 8.064000 ;
    PORT
      LAYER met2 ;
        RECT 2.690 1576.330 2.950 1576.590 ;
    END
  END row_off_detect_top<0>
  PIN row_off_detect_bot<39>
    ANTENNAGATEAREA 8.064000 ;
    PORT
      LAYER met2 ;
        RECT 2.690 349.850 2.950 350.110 ;
    END
  END row_off_detect_bot<39>
  PIN row_on_detect_top<2>
    ANTENNAGATEAREA 16.128000 ;
    PORT
      LAYER met2 ;
        RECT 2.690 1551.930 2.950 1552.190 ;
    END
  END row_on_detect_top<2>
  PIN row_off_detect_bot<41>
    ANTENNAGATEAREA 8.064000 ;
    PORT
      LAYER met2 ;
        RECT 2.690 325.850 2.950 326.110 ;
    END
  END row_off_detect_bot<41>
  PIN row_on_detect_top<4>
    ANTENNAGATEAREA 16.128000 ;
    PORT
      LAYER met2 ;
        RECT 2.690 1527.930 2.950 1528.190 ;
    END
  END row_on_detect_top<4>
  PIN row_off_detect_bot<42>
    ANTENNAGATEAREA 8.064000 ;
    PORT
      LAYER met2 ;
        RECT 2.690 304.330 2.950 304.590 ;
    END
  END row_off_detect_bot<42>
  PIN row_off_detect_bot<44>
    ANTENNAGATEAREA 8.064000 ;
    PORT
      LAYER met2 ;
        RECT 2.690 280.330 2.950 280.590 ;
    END
  END row_off_detect_bot<44>
  PIN row_off_detect_bot<46>
    ANTENNAGATEAREA 8.064000 ;
    PORT
      LAYER met2 ;
        RECT 2.690 256.330 2.950 256.590 ;
    END
  END row_off_detect_bot<46>
  PIN row_off_detect_top<12>
    ANTENNAGATEAREA 8.064000 ;
    PORT
      LAYER met2 ;
        RECT 2.690 1432.330 2.950 1432.590 ;
    END
  END row_off_detect_top<12>
  PIN row_off_detect_bot<47>
    ANTENNAGATEAREA 8.064000 ;
    PORT
      LAYER met2 ;
        RECT 2.690 253.850 2.950 254.110 ;
    END
  END row_off_detect_bot<47>
  PIN row_off_detect_bot<7>
    ANTENNAGATEAREA 8.064000 ;
    PORT
      LAYER met2 ;
        RECT 2.690 733.850 2.950 734.110 ;
    END
  END row_off_detect_bot<7>
  PIN row_off_detect_bot<49>
    ANTENNAGATEAREA 8.064000 ;
    PORT
      LAYER met2 ;
        RECT 2.690 229.850 2.950 230.110 ;
    END
  END row_off_detect_bot<49>
  PIN row_off_detect_bot<9>
    ANTENNAGATEAREA 8.064000 ;
    PORT
      LAYER met2 ;
        RECT 2.690 709.850 2.950 710.110 ;
    END
  END row_off_detect_bot<9>
  PIN row_off_detect_bot<51>
    ANTENNAGATEAREA 8.064000 ;
    PORT
      LAYER met2 ;
        RECT 2.690 205.850 2.950 206.110 ;
    END
  END row_off_detect_bot<51>
  PIN row_off_detect_top<10>
    ANTENNAGATEAREA 8.064000 ;
    PORT
      LAYER met2 ;
        RECT 2.690 1456.330 2.950 1456.590 ;
    END
  END row_off_detect_top<10>
  PIN row_off_detect_bot<57>
    ANTENNAGATEAREA 8.064000 ;
    PORT
      LAYER met2 ;
        RECT 2.690 133.850 2.950 134.110 ;
    END
  END row_off_detect_bot<57>
  PIN row_off_detect_bot<13>
    ANTENNAGATEAREA 8.064000 ;
    PORT
      LAYER met2 ;
        RECT 2.690 661.850 2.950 662.110 ;
    END
  END row_off_detect_bot<13>
  PIN row_off_detect_bot<6>
    ANTENNAGATEAREA 8.064000 ;
    PORT
      LAYER met2 ;
        RECT 2.690 736.330 2.950 736.590 ;
    END
  END row_off_detect_bot<6>
  PIN row_off_detect_bot<15>
    ANTENNAGATEAREA 8.064000 ;
    PORT
      LAYER met2 ;
        RECT 2.690 637.850 2.950 638.110 ;
    END
  END row_off_detect_bot<15>
  PIN row_off_detect_bot<17>
    ANTENNAGATEAREA 8.064000 ;
    PORT
      LAYER met2 ;
        RECT 2.690 613.850 2.950 614.110 ;
    END
  END row_off_detect_bot<17>
  PIN row_off_detect_bot<19>
    ANTENNAGATEAREA 8.064000 ;
    PORT
      LAYER met2 ;
        RECT 2.690 589.850 2.950 590.110 ;
    END
  END row_off_detect_bot<19>
  PIN row_off_detect_bot<20>
    ANTENNAGATEAREA 8.064000 ;
    PORT
      LAYER met2 ;
        RECT 2.690 568.330 2.950 568.590 ;
    END
  END row_off_detect_bot<20>
  PIN row_off_detect_bot<23>
    ANTENNAGATEAREA 8.064000 ;
    PORT
      LAYER met2 ;
        RECT 2.690 541.850 2.950 542.110 ;
    END
  END row_off_detect_bot<23>
  PIN row_off_detect_bot<25>
    ANTENNAGATEAREA 8.064000 ;
    PORT
      LAYER met2 ;
        RECT 2.690 517.850 2.950 518.110 ;
    END
  END row_off_detect_bot<25>
  PIN row_off_detect_bot<27>
    ANTENNAGATEAREA 8.064000 ;
    PORT
      LAYER met2 ;
        RECT 2.690 493.850 2.950 494.110 ;
    END
  END row_off_detect_bot<27>
  PIN row_on_detect_top<56>
    ANTENNAGATEAREA 16.128000 ;
    PORT
      LAYER met2 ;
        RECT 2.690 903.930 2.950 904.190 ;
    END
  END row_on_detect_top<56>
  PIN row_off_detect_top<52>
    ANTENNAGATEAREA 8.064000 ;
    PORT
      LAYER met2 ;
        RECT 2.690 952.330 2.950 952.590 ;
    END
  END row_off_detect_top<52>
  PIN row_off_detect_top<54>
    ANTENNAGATEAREA 8.064000 ;
    PORT
      LAYER met2 ;
        RECT 2.690 928.330 2.950 928.590 ;
    END
  END row_off_detect_top<54>
  PIN row_off_detect_bot<3>
    ANTENNAGATEAREA 8.064000 ;
    PORT
      LAYER met2 ;
        RECT 2.690 781.850 2.950 782.110 ;
    END
  END row_off_detect_bot<3>
  PIN row_on_detect_top<7>
    ANTENNAGATEAREA 16.128000 ;
    PORT
      LAYER met2 ;
        RECT 2.690 1502.250 2.950 1502.510 ;
    END
  END row_on_detect_top<7>
  PIN row_off_detect_top<19>
    ANTENNAGATEAREA 8.064000 ;
    PORT
      LAYER met2 ;
        RECT 2.690 1357.850 2.950 1358.110 ;
    END
  END row_off_detect_top<19>
  PIN row_off_detect_top<24>
    ANTENNAGATEAREA 8.064000 ;
    PORT
      LAYER met2 ;
        RECT 2.690 1288.330 2.950 1288.590 ;
    END
  END row_off_detect_top<24>
  PIN detect_pulse_global_bot_left
    ANTENNAGATEAREA 147.199997 ;
    PORT
      LAYER met2 ;
        RECT 2.690 18.420 2.990 19.420 ;
    END
  END detect_pulse_global_bot_left
  PIN row_off_detect_top<27>
    ANTENNAGATEAREA 8.064000 ;
    PORT
      LAYER met2 ;
        RECT 2.690 1261.850 2.950 1262.110 ;
    END
  END row_off_detect_top<27>
  PIN row_off_detect_top<30>
    ANTENNAGATEAREA 8.064000 ;
    PORT
      LAYER met2 ;
        RECT 2.690 1216.330 2.950 1216.590 ;
    END
  END row_off_detect_top<30>
  PIN row_off_detect_top<31>
    ANTENNAGATEAREA 8.064000 ;
    PORT
      LAYER met2 ;
        RECT 2.690 1213.850 2.950 1214.110 ;
    END
  END row_off_detect_top<31>
  PIN row_on_detect_bot<2>
    ANTENNAGATEAREA 16.128000 ;
    PORT
      LAYER met2 ;
        RECT 2.690 783.930 2.950 784.190 ;
    END
  END row_on_detect_bot<2>
  PIN row_off_detect_top<15>
    ANTENNAGATEAREA 8.064000 ;
    PORT
      LAYER met2 ;
        RECT 2.690 1405.850 2.950 1406.110 ;
    END
  END row_off_detect_top<15>
  PIN row_off_detect_top<35>
    ANTENNAGATEAREA 8.064000 ;
    PORT
      LAYER met2 ;
        RECT 2.690 1165.850 2.950 1166.110 ;
    END
  END row_off_detect_top<35>
  PIN row_off_detect_top<36>
    ANTENNAGATEAREA 8.064000 ;
    PORT
      LAYER met2 ;
        RECT 2.690 1144.330 2.950 1144.590 ;
    END
  END row_off_detect_top<36>
  PIN row_off_detect_top<39>
    ANTENNAGATEAREA 8.064000 ;
    PORT
      LAYER met2 ;
        RECT 2.690 1117.850 2.950 1118.110 ;
    END
  END row_off_detect_top<39>
  PIN row_off_detect_top<40>
    ANTENNAGATEAREA 8.064000 ;
    PORT
      LAYER met2 ;
        RECT 2.690 1096.330 2.950 1096.590 ;
    END
  END row_off_detect_top<40>
  PIN row_on_detect_bot<3>
    ANTENNAGATEAREA 16.128000 ;
    PORT
      LAYER met2 ;
        RECT 2.690 782.250 2.950 782.510 ;
    END
  END row_on_detect_bot<3>
  PIN row_off_detect_top<43>
    ANTENNAGATEAREA 8.064000 ;
    PORT
      LAYER met2 ;
        RECT 2.690 1069.850 2.950 1070.110 ;
    END
  END row_off_detect_top<43>
  PIN row_off_detect_top<44>
    ANTENNAGATEAREA 8.064000 ;
    PORT
      LAYER met2 ;
        RECT 2.690 1048.330 2.950 1048.590 ;
    END
  END row_off_detect_top<44>
  PIN row_off_detect_top<45>
    ANTENNAGATEAREA 8.064000 ;
    PORT
      LAYER met2 ;
        RECT 2.690 1045.850 2.950 1046.110 ;
    END
  END row_off_detect_top<45>
  PIN row_off_detect_top<48>
    ANTENNAGATEAREA 8.064000 ;
    PORT
      LAYER met2 ;
        RECT 2.690 1000.330 2.950 1000.590 ;
    END
  END row_off_detect_top<48>
  PIN row_off_detect_top<49>
    ANTENNAGATEAREA 8.064000 ;
    PORT
      LAYER met2 ;
        RECT 2.690 997.850 2.950 998.110 ;
    END
  END row_off_detect_top<49>
  PIN row_on_detect_bot<4>
    ANTENNAGATEAREA 16.128000 ;
    PORT
      LAYER met2 ;
        RECT 2.690 759.930 2.950 760.190 ;
    END
  END row_on_detect_bot<4>
  PIN pre_charge_global_top_left
    ANTENNAGATEAREA 1024.000000 ;
    PORT
      LAYER met2 ;
        RECT 770.690 1607.460 770.990 1608.470 ;
    END
  END pre_charge_global_top_left
  PIN row_off_detect_top<9>
    ANTENNAGATEAREA 8.064000 ;
    PORT
      LAYER met2 ;
        RECT 2.690 1477.850 2.950 1478.110 ;
    END
  END row_off_detect_top<9>
  PIN row_on_detect_top<16>
    ANTENNAGATEAREA 16.128000 ;
    PORT
      LAYER met2 ;
        RECT 2.690 1383.930 2.950 1384.190 ;
    END
  END row_on_detect_top<16>
  PIN row_on_detect_bot<11>
    ANTENNAGATEAREA 16.128000 ;
    PORT
      LAYER met2 ;
        RECT 2.690 686.250 2.950 686.510 ;
    END
  END row_on_detect_bot<11>
  PIN row_on_detect_bot<12>
    ANTENNAGATEAREA 16.128000 ;
    PORT
      LAYER met2 ;
        RECT 2.690 663.930 2.950 664.190 ;
    END
  END row_on_detect_bot<12>
  PIN row_off_detect_bot<58>
    ANTENNAGATEAREA 8.064000 ;
    PORT
      LAYER met2 ;
        RECT 2.690 112.330 2.950 112.590 ;
    END
  END row_off_detect_bot<58>
  PIN row_on_detect_top<61>
    ANTENNAGATEAREA 16.128000 ;
    PORT
      LAYER met2 ;
        RECT 2.690 854.250 2.950 854.510 ;
    END
  END row_on_detect_top<61>
  PIN ndetect_pulse_global_bot_left
    ANTENNAGATEAREA 64.000000 ;
    PORT
      LAYER met2 ;
        RECT 2.690 9.890 2.990 10.890 ;
    END
  END ndetect_pulse_global_bot_left
  PIN row_on_detect_bot<54>
    ANTENNAGATEAREA 16.128000 ;
    PORT
      LAYER met2 ;
        RECT 2.690 159.930 2.950 160.190 ;
    END
  END row_on_detect_bot<54>
  PIN row_on_detect_bot<55>
    ANTENNAGATEAREA 16.128000 ;
    PORT
      LAYER met2 ;
        RECT 2.690 158.250 2.950 158.510 ;
    END
  END row_on_detect_bot<55>
  PIN row_on_detect_top<17>
    ANTENNAGATEAREA 16.128000 ;
    PORT
      LAYER met2 ;
        RECT 2.690 1382.250 2.950 1382.510 ;
    END
  END row_on_detect_top<17>
  PIN row_on_detect_top<9>
    ANTENNAGATEAREA 16.128000 ;
    PORT
      LAYER met2 ;
        RECT 2.690 1478.250 2.950 1478.510 ;
    END
  END row_on_detect_top<9>
  PIN row_on_detect_bot<0>
    ANTENNAGATEAREA 16.128000 ;
    PORT
      LAYER met2 ;
        RECT 2.690 807.930 2.950 808.190 ;
    END
  END row_on_detect_bot<0>
  PIN row_on_detect_bot<48>
    ANTENNAGATEAREA 16.128000 ;
    PORT
      LAYER met2 ;
        RECT 2.690 231.930 2.950 232.190 ;
    END
  END row_on_detect_bot<48>
  PIN row_on_detect_bot<52>
    ANTENNAGATEAREA 16.128000 ;
    PORT
      LAYER met2 ;
        RECT 2.690 183.930 2.950 184.190 ;
    END
  END row_on_detect_bot<52>
  PIN row_on_detect_bot<53>
    ANTENNAGATEAREA 16.128000 ;
    PORT
      LAYER met2 ;
        RECT 2.690 182.250 2.950 182.510 ;
    END
  END row_on_detect_bot<53>
  PIN row_on_detect_bot<44>
    ANTENNAGATEAREA 16.128000 ;
    PORT
      LAYER met2 ;
        RECT 2.690 279.930 2.950 280.190 ;
    END
  END row_on_detect_bot<44>
  PIN row_on_detect_top<33>
    ANTENNAGATEAREA 16.128000 ;
    PORT
      LAYER met2 ;
        RECT 2.690 1190.250 2.950 1190.510 ;
    END
  END row_on_detect_top<33>
  PIN row_on_detect_top<34>
    ANTENNAGATEAREA 16.128000 ;
    PORT
      LAYER met2 ;
        RECT 2.690 1167.930 2.950 1168.190 ;
    END
  END row_on_detect_top<34>
  PIN row_off_detect_bot<55>
    ANTENNAGATEAREA 8.064000 ;
    PORT
      LAYER met2 ;
        RECT 2.690 157.850 2.950 158.110 ;
    END
  END row_off_detect_bot<55>
  PIN row_off_detect_bot<54>
    ANTENNAGATEAREA 8.064000 ;
    PORT
      LAYER met2 ;
        RECT 2.690 160.330 2.950 160.590 ;
    END
  END row_off_detect_bot<54>
  PIN row_on_detect_top<57>
    ANTENNAGATEAREA 16.128000 ;
    PORT
      LAYER met2 ;
        RECT 2.690 902.250 2.950 902.510 ;
    END
  END row_on_detect_top<57>
  PIN row_on_detect_top<29>
    ANTENNAGATEAREA 16.128000 ;
    PORT
      LAYER met2 ;
        RECT 2.690 1238.250 2.950 1238.510 ;
    END
  END row_on_detect_top<29>
  PIN row_on_detect_top<36>
    ANTENNAGATEAREA 16.128000 ;
    PORT
      LAYER met2 ;
        RECT 2.690 1143.930 2.950 1144.190 ;
    END
  END row_on_detect_top<36>
  PIN row_on_detect_top<37>
    ANTENNAGATEAREA 16.128000 ;
    PORT
      LAYER met2 ;
        RECT 2.690 1142.250 2.950 1142.510 ;
    END
  END row_on_detect_top<37>
  PIN row_on_detect_top<40>
    ANTENNAGATEAREA 16.128000 ;
    PORT
      LAYER met2 ;
        RECT 2.690 1095.930 2.950 1096.190 ;
    END
  END row_on_detect_top<40>
  PIN row_on_detect_top<43>
    ANTENNAGATEAREA 16.128000 ;
    PORT
      LAYER met2 ;
        RECT 2.690 1070.250 2.950 1070.510 ;
    END
  END row_on_detect_top<43>
  PIN row_on_detect_top<44>
    ANTENNAGATEAREA 16.128000 ;
    PORT
      LAYER met2 ;
        RECT 2.690 1047.930 2.950 1048.190 ;
    END
  END row_on_detect_top<44>
  PIN row_on_detect_top<45>
    ANTENNAGATEAREA 16.128000 ;
    PORT
      LAYER met2 ;
        RECT 2.690 1046.250 2.950 1046.510 ;
    END
  END row_on_detect_top<45>
  PIN row_on_detect_top<46>
    ANTENNAGATEAREA 16.128000 ;
    PORT
      LAYER met2 ;
        RECT 2.690 1023.930 2.950 1024.190 ;
    END
  END row_on_detect_top<46>
  PIN row_on_detect_top<49>
    ANTENNAGATEAREA 16.128000 ;
    PORT
      LAYER met2 ;
        RECT 2.690 998.250 2.950 998.510 ;
    END
  END row_on_detect_top<49>
  PIN row_on_detect_top<52>
    ANTENNAGATEAREA 16.128000 ;
    PORT
      LAYER met2 ;
        RECT 2.690 951.930 2.950 952.190 ;
    END
  END row_on_detect_top<52>
  PIN row_on_detect_top<53>
    ANTENNAGATEAREA 16.128000 ;
    PORT
      LAYER met2 ;
        RECT 2.690 950.250 2.950 950.510 ;
    END
  END row_on_detect_top<53>
  PIN row_on_detect_top<27>
    ANTENNAGATEAREA 16.128000 ;
    PORT
      LAYER met2 ;
        RECT 2.690 1262.250 2.950 1262.510 ;
    END
  END row_on_detect_top<27>
  PIN row_on_detect_top<55>
    ANTENNAGATEAREA 16.128000 ;
    PORT
      LAYER met2 ;
        RECT 2.690 926.250 2.950 926.510 ;
    END
  END row_on_detect_top<55>
  PIN row_off_detect_top<5>
    ANTENNAGATEAREA 8.064000 ;
    PORT
      LAYER met2 ;
        RECT 2.690 1525.850 2.950 1526.110 ;
    END
  END row_off_detect_top<5>
  PIN row_on_detect_bot<10>
    ANTENNAGATEAREA 16.128000 ;
    PORT
      LAYER met2 ;
        RECT 2.690 687.930 2.950 688.190 ;
    END
  END row_on_detect_bot<10>
  PIN row_on_detect_bot<13>
    ANTENNAGATEAREA 16.128000 ;
    PORT
      LAYER met2 ;
        RECT 2.690 662.250 2.950 662.510 ;
    END
  END row_on_detect_bot<13>
  PIN row_on_detect_top<59>
    ANTENNAGATEAREA 16.128000 ;
    PORT
      LAYER met2 ;
        RECT 2.690 878.250 2.950 878.510 ;
    END
  END row_on_detect_top<59>
  PIN row_on_detect_top<60>
    ANTENNAGATEAREA 16.128000 ;
    PORT
      LAYER met2 ;
        RECT 2.690 855.930 2.950 856.190 ;
    END
  END row_on_detect_top<60>
  PIN row_on_detect_bot<56>
    ANTENNAGATEAREA 16.128000 ;
    PORT
      LAYER met2 ;
        RECT 2.690 135.930 2.950 136.190 ;
    END
  END row_on_detect_bot<56>
  PIN row_off_detect_bot<63>
    ANTENNAGATEAREA 8.064000 ;
    PORT
      LAYER met2 ;
        RECT 2.690 61.850 2.950 62.110 ;
    END
  END row_off_detect_bot<63>
  PIN row_on_detect_bot<47>
    ANTENNAGATEAREA 16.128000 ;
    PORT
      LAYER met2 ;
        RECT 2.690 254.250 2.950 254.510 ;
    END
  END row_on_detect_bot<47>
  PIN row_on_detect_top<10>
    ANTENNAGATEAREA 16.128000 ;
    PORT
      LAYER met2 ;
        RECT 2.690 1455.930 2.950 1456.190 ;
    END
  END row_on_detect_top<10>
  PIN row_on_detect_top<8>
    ANTENNAGATEAREA 16.128000 ;
    PORT
      LAYER met2 ;
        RECT 2.690 1479.930 2.950 1480.190 ;
    END
  END row_on_detect_top<8>
  PIN row_on_detect_top<24>
    ANTENNAGATEAREA 16.128000 ;
    PORT
      LAYER met2 ;
        RECT 2.690 1287.930 2.950 1288.190 ;
    END
  END row_on_detect_top<24>
  PIN row_on_detect_bot<49>
    ANTENNAGATEAREA 16.128000 ;
    PORT
      LAYER met2 ;
        RECT 2.690 230.250 2.950 230.510 ;
    END
  END row_on_detect_bot<49>
  PIN row_on_detect_bot<50>
    ANTENNAGATEAREA 16.128000 ;
    PORT
      LAYER met2 ;
        RECT 2.690 207.930 2.950 208.190 ;
    END
  END row_on_detect_bot<50>
  PIN row_on_detect_bot<51>
    ANTENNAGATEAREA 16.128000 ;
    PORT
      LAYER met2 ;
        RECT 2.690 206.250 2.950 206.510 ;
    END
  END row_on_detect_bot<51>
  PIN row_on_detect_bot<8>
    ANTENNAGATEAREA 16.128000 ;
    PORT
      LAYER met2 ;
        RECT 2.690 711.930 2.950 712.190 ;
    END
  END row_on_detect_bot<8>
  PIN row_on_detect_top<31>
    ANTENNAGATEAREA 16.128000 ;
    PORT
      LAYER met2 ;
        RECT 2.690 1214.250 2.950 1214.510 ;
    END
  END row_on_detect_top<31>
  PIN row_on_detect_top<32>
    ANTENNAGATEAREA 16.128000 ;
    PORT
      LAYER met2 ;
        RECT 2.690 1191.930 2.950 1192.190 ;
    END
  END row_on_detect_top<32>
  PIN vssa1
    ANTENNADIFFAREA 28604.031250 ;
    PORT
      LAYER met2 ;
        RECT 2.690 39.860 1542.950 40.860 ;
    END
  END vssa1
  PIN row_off_detect_bot<61>
    ANTENNAGATEAREA 8.064000 ;
    PORT
      LAYER met2 ;
        RECT 2.690 85.850 2.950 86.110 ;
    END
  END row_off_detect_bot<61>
  PIN row_off_detect_bot<53>
    ANTENNAGATEAREA 8.064000 ;
    PORT
      LAYER met2 ;
        RECT 2.690 181.850 2.950 182.110 ;
    END
  END row_off_detect_bot<53>
  PIN row_off_detect_bot<52>
    ANTENNAGATEAREA 8.064000 ;
    PORT
      LAYER met2 ;
        RECT 2.690 184.330 2.950 184.590 ;
    END
  END row_off_detect_bot<52>
  PIN row_on_detect_bot<45>
    ANTENNAGATEAREA 16.128000 ;
    PORT
      LAYER met2 ;
        RECT 2.690 278.250 2.950 278.510 ;
    END
  END row_on_detect_bot<45>
  PIN row_off_detect_bot<5>
    ANTENNAGATEAREA 8.064000 ;
    PORT
      LAYER met2 ;
        RECT 2.690 757.850 2.950 758.110 ;
    END
  END row_off_detect_bot<5>
  PIN row_off_detect_bot<4>
    ANTENNAGATEAREA 8.064000 ;
    PORT
      LAYER met2 ;
        RECT 2.690 760.330 2.950 760.590 ;
    END
  END row_off_detect_bot<4>
  PIN row_on_detect_top<25>
    ANTENNAGATEAREA 16.128000 ;
    PORT
      LAYER met2 ;
        RECT 2.690 1286.250 2.950 1286.510 ;
    END
  END row_on_detect_top<25>
  PIN row_on_detect_top<35>
    ANTENNAGATEAREA 16.128000 ;
    PORT
      LAYER met2 ;
        RECT 2.690 1166.250 2.950 1166.510 ;
    END
  END row_on_detect_top<35>
  PIN row_on_detect_top<38>
    ANTENNAGATEAREA 16.128000 ;
    PORT
      LAYER met2 ;
        RECT 2.690 1119.930 2.950 1120.190 ;
    END
  END row_on_detect_top<38>
  PIN row_on_detect_top<39>
    ANTENNAGATEAREA 16.128000 ;
    PORT
      LAYER met2 ;
        RECT 2.690 1118.250 2.950 1118.510 ;
    END
  END row_on_detect_top<39>
  PIN row_on_detect_top<41>
    ANTENNAGATEAREA 16.128000 ;
    PORT
      LAYER met2 ;
        RECT 2.690 1094.250 2.950 1094.510 ;
    END
  END row_on_detect_top<41>
  PIN row_on_detect_top<42>
    ANTENNAGATEAREA 16.128000 ;
    PORT
      LAYER met2 ;
        RECT 2.690 1071.930 2.950 1072.190 ;
    END
  END row_on_detect_top<42>
  PIN row_on_detect_top<26>
    ANTENNAGATEAREA 16.128000 ;
    PORT
      LAYER met2 ;
        RECT 2.690 1263.930 2.950 1264.190 ;
    END
  END row_on_detect_top<26>
  PIN row_on_detect_top<47>
    ANTENNAGATEAREA 16.128000 ;
    PORT
      LAYER met2 ;
        RECT 2.690 1022.250 2.950 1022.510 ;
    END
  END row_on_detect_top<47>
  PIN row_on_detect_top<48>
    ANTENNAGATEAREA 16.128000 ;
    PORT
      LAYER met2 ;
        RECT 2.690 999.930 2.950 1000.190 ;
    END
  END row_on_detect_top<48>
  PIN row_on_detect_top<50>
    ANTENNAGATEAREA 16.128000 ;
    PORT
      LAYER met2 ;
        RECT 2.690 975.930 2.950 976.190 ;
    END
  END row_on_detect_top<50>
  PIN row_on_detect_top<51>
    ANTENNAGATEAREA 16.128000 ;
    PORT
      LAYER met2 ;
        RECT 2.690 974.250 2.950 974.510 ;
    END
  END row_on_detect_top<51>
  PIN row_on_detect_top<54>
    ANTENNAGATEAREA 16.128000 ;
    PORT
      LAYER met2 ;
        RECT 2.690 927.930 2.950 928.190 ;
    END
  END row_on_detect_top<54>
  PIN row_on_detect_top<58>
    ANTENNAGATEAREA 16.128000 ;
    PORT
      LAYER met2 ;
        RECT 2.690 879.930 2.950 880.190 ;
    END
  END row_on_detect_top<58>
  PIN row_off_detect_top<6>
    ANTENNAGATEAREA 8.064000 ;
    PORT
      LAYER met2 ;
        RECT 2.690 1504.330 2.950 1504.590 ;
    END
  END row_off_detect_top<6>
  PIN row_on_detect_top<11>
    ANTENNAGATEAREA 16.128000 ;
    PORT
      LAYER met2 ;
        RECT 2.690 1454.250 2.950 1454.510 ;
    END
  END row_on_detect_top<11>
  PIN row_on_detect_top<62>
    ANTENNAGATEAREA 16.128000 ;
    PORT
      LAYER met2 ;
        RECT 2.690 831.930 2.950 832.190 ;
    END
  END row_on_detect_top<62>
  PIN row_on_detect_top<19>
    ANTENNAGATEAREA 16.128000 ;
    PORT
      LAYER met2 ;
        RECT 2.690 1358.250 2.950 1358.510 ;
    END
  END row_on_detect_top<19>
  PIN row_on_detect_top<23>
    ANTENNAGATEAREA 16.128000 ;
    PORT
      LAYER met2 ;
        RECT 2.690 1310.250 2.950 1310.510 ;
    END
  END row_on_detect_top<23>
  PIN row_on_detect_top<21>
    ANTENNAGATEAREA 16.128000 ;
    PORT
      LAYER met2 ;
        RECT 2.690 1334.250 2.950 1334.510 ;
    END
  END row_on_detect_top<21>
  PIN row_on_detect_top<18>
    ANTENNAGATEAREA 16.128000 ;
    PORT
      LAYER met2 ;
        RECT 2.690 1359.930 2.950 1360.190 ;
    END
  END row_on_detect_top<18>
  PIN row_on_detect_top<14>
    ANTENNAGATEAREA 16.128000 ;
    PORT
      LAYER met2 ;
        RECT 2.690 1407.930 2.950 1408.190 ;
    END
  END row_on_detect_top<14>
  PIN row_on_detect_top<13>
    ANTENNAGATEAREA 16.128000 ;
    PORT
      LAYER met2 ;
        RECT 2.690 1430.250 2.950 1430.510 ;
    END
  END row_on_detect_top<13>
  PIN row_on_detect_top<12>
    ANTENNAGATEAREA 16.128000 ;
    PORT
      LAYER met2 ;
        RECT 2.690 1431.930 2.950 1432.190 ;
    END
  END row_on_detect_top<12>
  PIN row_on_detect_bot<46>
    ANTENNAGATEAREA 16.128000 ;
    PORT
      LAYER met2 ;
        RECT 2.690 255.930 2.950 256.190 ;
    END
  END row_on_detect_bot<46>
  PIN row_off_detect_bot<2>
    ANTENNAGATEAREA 8.064000 ;
    PORT
      LAYER met2 ;
        RECT 2.690 784.330 2.950 784.590 ;
    END
  END row_off_detect_bot<2>
  PIN row_off_detect_bot<56>
    ANTENNAGATEAREA 8.064000 ;
    PORT
      LAYER met2 ;
        RECT 2.690 136.330 2.950 136.590 ;
    END
  END row_off_detect_bot<56>
  PIN row_off_detect_top<1>
    ANTENNAGATEAREA 8.064000 ;
    PORT
      LAYER met2 ;
        RECT 2.690 1573.850 2.950 1574.110 ;
    END
  END row_off_detect_top<1>
  PIN row_on_detect_bot<7>
    ANTENNAGATEAREA 16.128000 ;
    PORT
      LAYER met2 ;
        RECT 2.690 734.250 2.950 734.510 ;
    END
  END row_on_detect_bot<7>
  PIN row_on_detect_top<30>
    ANTENNAGATEAREA 16.128000 ;
    PORT
      LAYER met2 ;
        RECT 2.690 1215.930 2.950 1216.190 ;
    END
  END row_on_detect_top<30>
  PIN row_on_detect_bot<39>
    ANTENNAGATEAREA 16.128000 ;
    PORT
      LAYER met2 ;
        RECT 2.690 350.250 2.950 350.510 ;
    END
  END row_on_detect_bot<39>
  PIN row_on_detect_bot<9>
    ANTENNAGATEAREA 16.128000 ;
    PORT
      LAYER met2 ;
        RECT 2.690 710.250 2.950 710.510 ;
    END
  END row_on_detect_bot<9>
  PIN row_on_detect_bot<38>
    ANTENNAGATEAREA 16.128000 ;
    PORT
      LAYER met2 ;
        RECT 2.690 351.930 2.950 352.190 ;
    END
  END row_on_detect_bot<38>
  PIN row_on_detect_bot<37>
    ANTENNAGATEAREA 16.128000 ;
    PORT
      LAYER met2 ;
        RECT 2.690 374.250 2.950 374.510 ;
    END
  END row_on_detect_bot<37>
  PIN row_on_detect_bot<36>
    ANTENNAGATEAREA 16.128000 ;
    PORT
      LAYER met2 ;
        RECT 2.690 375.930 2.950 376.190 ;
    END
  END row_on_detect_bot<36>
  PIN row_on_detect_bot<35>
    ANTENNAGATEAREA 16.128000 ;
    PORT
      LAYER met2 ;
        RECT 2.690 398.250 2.950 398.510 ;
    END
  END row_on_detect_bot<35>
  PIN row_on_detect_bot<34>
    ANTENNAGATEAREA 16.128000 ;
    PORT
      LAYER met2 ;
        RECT 2.690 399.930 2.950 400.190 ;
    END
  END row_on_detect_bot<34>
  PIN row_on_detect_bot<6>
    ANTENNAGATEAREA 16.128000 ;
    PORT
      LAYER met2 ;
        RECT 2.690 735.930 2.950 736.190 ;
    END
  END row_on_detect_bot<6>
  PIN row_on_detect_bot<33>
    ANTENNAGATEAREA 16.128000 ;
    PORT
      LAYER met2 ;
        RECT 2.690 422.250 2.950 422.510 ;
    END
  END row_on_detect_bot<33>
  PIN row_on_detect_bot<32>
    ANTENNAGATEAREA 16.128000 ;
    PORT
      LAYER met2 ;
        RECT 2.690 423.930 2.950 424.190 ;
    END
  END row_on_detect_bot<32>
  PIN row_on_detect_bot<43>
    ANTENNAGATEAREA 16.128000 ;
    PORT
      LAYER met2 ;
        RECT 2.690 302.250 2.950 302.510 ;
    END
  END row_on_detect_bot<43>
  PIN row_on_detect_bot<31>
    ANTENNAGATEAREA 16.128000 ;
    PORT
      LAYER met2 ;
        RECT 2.690 446.250 2.950 446.510 ;
    END
  END row_on_detect_bot<31>
  PIN row_on_detect_bot<30>
    ANTENNAGATEAREA 16.128000 ;
    PORT
      LAYER met2 ;
        RECT 2.690 447.930 2.950 448.190 ;
    END
  END row_on_detect_bot<30>
  PIN row_on_detect_bot<63>
    ANTENNAGATEAREA 16.128000 ;
    PORT
      LAYER met2 ;
        RECT 2.690 62.250 2.950 62.510 ;
    END
  END row_on_detect_bot<63>
  PIN row_on_detect_bot<29>
    ANTENNAGATEAREA 16.128000 ;
    PORT
      LAYER met2 ;
        RECT 2.690 470.250 2.950 470.510 ;
    END
  END row_on_detect_bot<29>
  PIN row_on_detect_bot<28>
    ANTENNAGATEAREA 16.128000 ;
    PORT
      LAYER met2 ;
        RECT 2.690 471.930 2.950 472.190 ;
    END
  END row_on_detect_bot<28>
  PIN row_on_detect_bot<27>
    ANTENNAGATEAREA 16.128000 ;
    PORT
      LAYER met2 ;
        RECT 2.690 494.250 2.950 494.510 ;
    END
  END row_on_detect_bot<27>
  PIN row_on_detect_bot<26>
    ANTENNAGATEAREA 16.128000 ;
    PORT
      LAYER met2 ;
        RECT 2.690 495.930 2.950 496.190 ;
    END
  END row_on_detect_bot<26>
  PIN row_on_detect_bot<25>
    ANTENNAGATEAREA 16.128000 ;
    PORT
      LAYER met2 ;
        RECT 2.690 518.250 2.950 518.510 ;
    END
  END row_on_detect_bot<25>
  PIN row_on_detect_bot<24>
    ANTENNAGATEAREA 16.128000 ;
    PORT
      LAYER met2 ;
        RECT 2.690 519.930 2.950 520.190 ;
    END
  END row_on_detect_bot<24>
  PIN row_on_detect_bot<5>
    ANTENNAGATEAREA 16.128000 ;
    PORT
      LAYER met2 ;
        RECT 2.690 758.250 2.950 758.510 ;
    END
  END row_on_detect_bot<5>
  PIN row_on_detect_bot<42>
    ANTENNAGATEAREA 16.128000 ;
    PORT
      LAYER met2 ;
        RECT 2.690 303.930 2.950 304.190 ;
    END
  END row_on_detect_bot<42>
  PIN row_on_detect_bot<23>
    ANTENNAGATEAREA 16.128000 ;
    PORT
      LAYER met2 ;
        RECT 2.690 542.250 2.950 542.510 ;
    END
  END row_on_detect_bot<23>
  PIN row_on_detect_bot<22>
    ANTENNAGATEAREA 16.128000 ;
    PORT
      LAYER met2 ;
        RECT 2.690 543.930 2.950 544.190 ;
    END
  END row_on_detect_bot<22>
  PIN row_on_detect_bot<21>
    ANTENNAGATEAREA 16.128000 ;
    PORT
      LAYER met2 ;
        RECT 2.690 566.250 2.950 566.510 ;
    END
  END row_on_detect_bot<21>
  PIN row_on_detect_bot<62>
    ANTENNAGATEAREA 16.128000 ;
    PORT
      LAYER met2 ;
        RECT 2.690 63.930 2.950 64.190 ;
    END
  END row_on_detect_bot<62>
  PIN row_on_detect_bot<20>
    ANTENNAGATEAREA 16.128000 ;
    PORT
      LAYER met2 ;
        RECT 2.690 567.930 2.950 568.190 ;
    END
  END row_on_detect_bot<20>
  PIN row_on_detect_bot<19>
    ANTENNAGATEAREA 16.128000 ;
    PORT
      LAYER met2 ;
        RECT 2.690 590.250 2.950 590.510 ;
    END
  END row_on_detect_bot<19>
  PIN row_on_detect_bot<18>
    ANTENNAGATEAREA 16.128000 ;
    PORT
      LAYER met2 ;
        RECT 2.690 591.930 2.950 592.190 ;
    END
  END row_on_detect_bot<18>
  PIN row_on_detect_bot<17>
    ANTENNAGATEAREA 16.128000 ;
    PORT
      LAYER met2 ;
        RECT 2.690 614.250 2.950 614.510 ;
    END
  END row_on_detect_bot<17>
  PIN row_off_detect_bot<1>
    ANTENNAGATEAREA 8.064000 ;
    PORT
      LAYER met2 ;
        RECT 2.690 805.850 2.950 806.110 ;
    END
  END row_off_detect_bot<1>
  PIN row_off_detect_bot<0>
    ANTENNAGATEAREA 8.064000 ;
    PORT
      LAYER met2 ;
        RECT 2.690 808.330 2.950 808.590 ;
    END
  END row_off_detect_bot<0>
  OBS
      LAYER nwell ;
        RECT -0.775 -0.005 1542.155 1638.445 ;
      LAYER li1 ;
        RECT -0.440 0.125 1541.820 1638.315 ;
      LAYER met1 ;
        RECT -0.500 0.065 1542.950 1638.375 ;
      LAYER met2 ;
        RECT 0.765 1628.830 1556.020 1638.230 ;
        RECT 0.765 1627.270 770.410 1628.830 ;
        RECT 771.270 1627.270 1556.020 1628.830 ;
        RECT 0.765 1620.300 1556.020 1627.270 ;
        RECT 0.765 1618.740 770.410 1620.300 ;
        RECT 771.270 1618.740 1556.020 1620.300 ;
        RECT 0.765 1608.750 1556.020 1618.740 ;
        RECT 0.765 1607.180 770.410 1608.750 ;
        RECT 771.270 1607.180 1556.020 1608.750 ;
        RECT 0.765 1576.870 1556.020 1607.180 ;
        RECT 0.765 1575.650 2.410 1576.870 ;
        RECT 3.230 1575.650 1556.020 1576.870 ;
        RECT 0.765 1574.790 1556.020 1575.650 ;
        RECT 0.765 1573.570 2.410 1574.790 ;
        RECT 3.230 1573.570 1556.020 1574.790 ;
        RECT 0.765 1552.870 1556.020 1573.570 ;
        RECT 0.765 1551.650 2.410 1552.870 ;
        RECT 3.230 1551.650 1556.020 1552.870 ;
        RECT 0.765 1550.790 1556.020 1551.650 ;
        RECT 0.765 1549.570 2.410 1550.790 ;
        RECT 3.230 1549.570 1556.020 1550.790 ;
        RECT 0.765 1528.870 1556.020 1549.570 ;
        RECT 0.765 1527.650 2.410 1528.870 ;
        RECT 3.230 1527.650 1556.020 1528.870 ;
        RECT 0.765 1526.790 1556.020 1527.650 ;
        RECT 0.765 1525.570 2.410 1526.790 ;
        RECT 3.230 1525.570 1556.020 1526.790 ;
        RECT 0.765 1504.870 1556.020 1525.570 ;
        RECT 0.765 1503.650 2.410 1504.870 ;
        RECT 3.230 1503.650 1556.020 1504.870 ;
        RECT 0.765 1502.790 1556.020 1503.650 ;
        RECT 0.765 1501.570 2.410 1502.790 ;
        RECT 3.230 1501.570 1556.020 1502.790 ;
        RECT 0.765 1480.870 1556.020 1501.570 ;
        RECT 0.765 1479.650 2.410 1480.870 ;
        RECT 3.230 1479.650 1556.020 1480.870 ;
        RECT 0.765 1478.790 1556.020 1479.650 ;
        RECT 0.765 1477.570 2.410 1478.790 ;
        RECT 3.230 1477.570 1556.020 1478.790 ;
        RECT 0.765 1456.870 1556.020 1477.570 ;
        RECT 0.765 1455.650 2.410 1456.870 ;
        RECT 3.230 1455.650 1556.020 1456.870 ;
        RECT 0.765 1454.790 1556.020 1455.650 ;
        RECT 0.765 1453.570 2.410 1454.790 ;
        RECT 3.230 1453.570 1556.020 1454.790 ;
        RECT 0.765 1432.870 1556.020 1453.570 ;
        RECT 0.765 1431.650 2.410 1432.870 ;
        RECT 3.230 1431.650 1556.020 1432.870 ;
        RECT 0.765 1430.790 1556.020 1431.650 ;
        RECT 0.765 1429.570 2.410 1430.790 ;
        RECT 3.230 1429.570 1556.020 1430.790 ;
        RECT 0.765 1408.870 1556.020 1429.570 ;
        RECT 0.765 1407.650 2.410 1408.870 ;
        RECT 3.230 1407.650 1556.020 1408.870 ;
        RECT 0.765 1406.790 1556.020 1407.650 ;
        RECT 0.765 1405.570 2.410 1406.790 ;
        RECT 3.230 1405.570 1556.020 1406.790 ;
        RECT 0.765 1384.870 1556.020 1405.570 ;
        RECT 0.765 1383.650 2.410 1384.870 ;
        RECT 3.230 1383.650 1556.020 1384.870 ;
        RECT 0.765 1382.790 1556.020 1383.650 ;
        RECT 0.765 1381.570 2.410 1382.790 ;
        RECT 3.230 1381.570 1556.020 1382.790 ;
        RECT 0.765 1360.870 1556.020 1381.570 ;
        RECT 0.765 1359.650 2.410 1360.870 ;
        RECT 3.230 1359.650 1556.020 1360.870 ;
        RECT 0.765 1358.790 1556.020 1359.650 ;
        RECT 0.765 1357.570 2.410 1358.790 ;
        RECT 3.230 1357.570 1556.020 1358.790 ;
        RECT 0.765 1336.870 1556.020 1357.570 ;
        RECT 0.765 1335.650 2.410 1336.870 ;
        RECT 3.230 1335.650 1556.020 1336.870 ;
        RECT 0.765 1334.790 1556.020 1335.650 ;
        RECT 0.765 1333.570 2.410 1334.790 ;
        RECT 3.230 1333.570 1556.020 1334.790 ;
        RECT 0.765 1312.870 1556.020 1333.570 ;
        RECT 0.765 1311.650 2.410 1312.870 ;
        RECT 3.230 1311.650 1556.020 1312.870 ;
        RECT 0.765 1310.790 1556.020 1311.650 ;
        RECT 0.765 1309.570 2.410 1310.790 ;
        RECT 3.230 1309.570 1556.020 1310.790 ;
        RECT 0.765 1288.870 1556.020 1309.570 ;
        RECT 0.765 1287.650 2.410 1288.870 ;
        RECT 3.230 1287.650 1556.020 1288.870 ;
        RECT 0.765 1286.790 1556.020 1287.650 ;
        RECT 0.765 1285.570 2.410 1286.790 ;
        RECT 3.230 1285.570 1556.020 1286.790 ;
        RECT 0.765 1264.870 1556.020 1285.570 ;
        RECT 0.765 1263.650 2.410 1264.870 ;
        RECT 3.230 1263.650 1556.020 1264.870 ;
        RECT 0.765 1262.790 1556.020 1263.650 ;
        RECT 0.765 1261.570 2.410 1262.790 ;
        RECT 3.230 1261.570 1556.020 1262.790 ;
        RECT 0.765 1240.870 1556.020 1261.570 ;
        RECT 0.765 1239.650 2.410 1240.870 ;
        RECT 3.230 1239.650 1556.020 1240.870 ;
        RECT 0.765 1238.790 1556.020 1239.650 ;
        RECT 0.765 1237.570 2.410 1238.790 ;
        RECT 3.230 1237.570 1556.020 1238.790 ;
        RECT 0.765 1216.870 1556.020 1237.570 ;
        RECT 0.765 1215.650 2.410 1216.870 ;
        RECT 3.230 1215.650 1556.020 1216.870 ;
        RECT 0.765 1214.790 1556.020 1215.650 ;
        RECT 0.765 1213.570 2.410 1214.790 ;
        RECT 3.230 1213.570 1556.020 1214.790 ;
        RECT 0.765 1192.870 1556.020 1213.570 ;
        RECT 0.765 1191.650 2.410 1192.870 ;
        RECT 3.230 1191.650 1556.020 1192.870 ;
        RECT 0.765 1190.790 1556.020 1191.650 ;
        RECT 0.765 1189.570 2.410 1190.790 ;
        RECT 3.230 1189.570 1556.020 1190.790 ;
        RECT 0.765 1168.870 1556.020 1189.570 ;
        RECT 0.765 1167.650 2.410 1168.870 ;
        RECT 3.230 1167.650 1556.020 1168.870 ;
        RECT 0.765 1166.790 1556.020 1167.650 ;
        RECT 0.765 1165.570 2.410 1166.790 ;
        RECT 3.230 1165.570 1556.020 1166.790 ;
        RECT 0.765 1144.870 1556.020 1165.570 ;
        RECT 0.765 1143.650 2.410 1144.870 ;
        RECT 3.230 1143.650 1556.020 1144.870 ;
        RECT 0.765 1142.790 1556.020 1143.650 ;
        RECT 0.765 1141.570 2.410 1142.790 ;
        RECT 3.230 1141.570 1556.020 1142.790 ;
        RECT 0.765 1120.870 1556.020 1141.570 ;
        RECT 0.765 1119.650 2.410 1120.870 ;
        RECT 3.230 1119.650 1556.020 1120.870 ;
        RECT 0.765 1118.790 1556.020 1119.650 ;
        RECT 0.765 1117.570 2.410 1118.790 ;
        RECT 3.230 1117.570 1556.020 1118.790 ;
        RECT 0.765 1096.870 1556.020 1117.570 ;
        RECT 0.765 1095.650 2.410 1096.870 ;
        RECT 3.230 1095.650 1556.020 1096.870 ;
        RECT 0.765 1094.790 1556.020 1095.650 ;
        RECT 0.765 1093.570 2.410 1094.790 ;
        RECT 3.230 1093.570 1556.020 1094.790 ;
        RECT 0.765 1072.870 1556.020 1093.570 ;
        RECT 0.765 1071.650 2.410 1072.870 ;
        RECT 3.230 1071.650 1556.020 1072.870 ;
        RECT 0.765 1070.790 1556.020 1071.650 ;
        RECT 0.765 1069.570 2.410 1070.790 ;
        RECT 3.230 1069.570 1556.020 1070.790 ;
        RECT 0.765 1048.870 1556.020 1069.570 ;
        RECT 0.765 1047.650 2.410 1048.870 ;
        RECT 3.230 1047.650 1556.020 1048.870 ;
        RECT 0.765 1046.790 1556.020 1047.650 ;
        RECT 0.765 1045.570 2.410 1046.790 ;
        RECT 3.230 1045.570 1556.020 1046.790 ;
        RECT 0.765 1024.870 1556.020 1045.570 ;
        RECT 0.765 1023.650 2.410 1024.870 ;
        RECT 3.230 1023.650 1556.020 1024.870 ;
        RECT 0.765 1022.790 1556.020 1023.650 ;
        RECT 0.765 1021.570 2.410 1022.790 ;
        RECT 3.230 1021.570 1556.020 1022.790 ;
        RECT 0.765 1000.870 1556.020 1021.570 ;
        RECT 0.765 999.650 2.410 1000.870 ;
        RECT 3.230 999.650 1556.020 1000.870 ;
        RECT 0.765 998.790 1556.020 999.650 ;
        RECT 0.765 997.570 2.410 998.790 ;
        RECT 3.230 997.570 1556.020 998.790 ;
        RECT 0.765 976.870 1556.020 997.570 ;
        RECT 0.765 975.650 2.410 976.870 ;
        RECT 3.230 975.650 1556.020 976.870 ;
        RECT 0.765 974.790 1556.020 975.650 ;
        RECT 0.765 973.570 2.410 974.790 ;
        RECT 3.230 973.570 1556.020 974.790 ;
        RECT 0.765 952.870 1556.020 973.570 ;
        RECT 0.765 951.650 2.410 952.870 ;
        RECT 3.230 951.650 1556.020 952.870 ;
        RECT 0.765 950.790 1556.020 951.650 ;
        RECT 0.765 949.570 2.410 950.790 ;
        RECT 3.230 949.570 1556.020 950.790 ;
        RECT 0.765 928.870 1556.020 949.570 ;
        RECT 0.765 927.650 2.410 928.870 ;
        RECT 3.230 927.650 1556.020 928.870 ;
        RECT 0.765 926.790 1556.020 927.650 ;
        RECT 0.765 925.570 2.410 926.790 ;
        RECT 3.230 925.570 1556.020 926.790 ;
        RECT 0.765 904.870 1556.020 925.570 ;
        RECT 0.765 903.650 2.410 904.870 ;
        RECT 3.230 903.650 1556.020 904.870 ;
        RECT 0.765 902.790 1556.020 903.650 ;
        RECT 0.765 901.570 2.410 902.790 ;
        RECT 3.230 901.570 1556.020 902.790 ;
        RECT 0.765 880.870 1556.020 901.570 ;
        RECT 0.765 879.650 2.410 880.870 ;
        RECT 3.230 879.650 1556.020 880.870 ;
        RECT 0.765 878.790 1556.020 879.650 ;
        RECT 0.765 877.570 2.410 878.790 ;
        RECT 3.230 877.570 1556.020 878.790 ;
        RECT 0.765 856.870 1556.020 877.570 ;
        RECT 0.765 855.650 2.410 856.870 ;
        RECT 3.230 855.650 1556.020 856.870 ;
        RECT 0.765 854.790 1556.020 855.650 ;
        RECT 0.765 853.570 2.410 854.790 ;
        RECT 3.230 853.570 1556.020 854.790 ;
        RECT 0.765 832.870 1556.020 853.570 ;
        RECT 0.765 831.650 2.410 832.870 ;
        RECT 3.230 831.650 1556.020 832.870 ;
        RECT 0.765 830.790 1556.020 831.650 ;
        RECT 0.765 829.570 2.410 830.790 ;
        RECT 3.230 829.570 1556.020 830.790 ;
        RECT 0.765 808.870 1556.020 829.570 ;
        RECT 0.765 807.650 2.410 808.870 ;
        RECT 3.230 807.650 1556.020 808.870 ;
        RECT 0.765 806.790 1556.020 807.650 ;
        RECT 0.765 805.570 2.410 806.790 ;
        RECT 3.230 805.570 1556.020 806.790 ;
        RECT 0.765 784.870 1556.020 805.570 ;
        RECT 0.765 783.650 2.410 784.870 ;
        RECT 3.230 783.650 1556.020 784.870 ;
        RECT 0.765 782.790 1556.020 783.650 ;
        RECT 0.765 781.570 2.410 782.790 ;
        RECT 3.230 781.570 1556.020 782.790 ;
        RECT 0.765 760.870 1556.020 781.570 ;
        RECT 0.765 759.650 2.410 760.870 ;
        RECT 3.230 759.650 1556.020 760.870 ;
        RECT 0.765 758.790 1556.020 759.650 ;
        RECT 0.765 757.570 2.410 758.790 ;
        RECT 3.230 757.570 1556.020 758.790 ;
        RECT 0.765 736.870 1556.020 757.570 ;
        RECT 0.765 735.650 2.410 736.870 ;
        RECT 3.230 735.650 1556.020 736.870 ;
        RECT 0.765 734.790 1556.020 735.650 ;
        RECT 0.765 733.570 2.410 734.790 ;
        RECT 3.230 733.570 1556.020 734.790 ;
        RECT 0.765 712.870 1556.020 733.570 ;
        RECT 0.765 711.650 2.410 712.870 ;
        RECT 3.230 711.650 1556.020 712.870 ;
        RECT 0.765 710.790 1556.020 711.650 ;
        RECT 0.765 709.570 2.410 710.790 ;
        RECT 3.230 709.570 1556.020 710.790 ;
        RECT 0.765 688.870 1556.020 709.570 ;
        RECT 0.765 687.650 2.410 688.870 ;
        RECT 3.230 687.650 1556.020 688.870 ;
        RECT 0.765 686.790 1556.020 687.650 ;
        RECT 0.765 685.570 2.410 686.790 ;
        RECT 3.230 685.570 1556.020 686.790 ;
        RECT 0.765 664.870 1556.020 685.570 ;
        RECT 0.765 663.650 2.410 664.870 ;
        RECT 3.230 663.650 1556.020 664.870 ;
        RECT 0.765 662.790 1556.020 663.650 ;
        RECT 0.765 661.570 2.410 662.790 ;
        RECT 3.230 661.570 1556.020 662.790 ;
        RECT 0.765 640.870 1556.020 661.570 ;
        RECT 0.765 639.650 2.410 640.870 ;
        RECT 3.230 639.650 1556.020 640.870 ;
        RECT 0.765 638.790 1556.020 639.650 ;
        RECT 0.765 637.570 2.410 638.790 ;
        RECT 3.230 637.570 1556.020 638.790 ;
        RECT 0.765 616.870 1556.020 637.570 ;
        RECT 0.765 615.650 2.410 616.870 ;
        RECT 3.230 615.650 1556.020 616.870 ;
        RECT 0.765 614.790 1556.020 615.650 ;
        RECT 0.765 613.570 2.410 614.790 ;
        RECT 3.230 613.570 1556.020 614.790 ;
        RECT 0.765 592.870 1556.020 613.570 ;
        RECT 0.765 591.650 2.410 592.870 ;
        RECT 3.230 591.650 1556.020 592.870 ;
        RECT 0.765 590.790 1556.020 591.650 ;
        RECT 0.765 589.570 2.410 590.790 ;
        RECT 3.230 589.570 1556.020 590.790 ;
        RECT 0.765 568.870 1556.020 589.570 ;
        RECT 0.765 567.650 2.410 568.870 ;
        RECT 3.230 567.650 1556.020 568.870 ;
        RECT 0.765 566.790 1556.020 567.650 ;
        RECT 0.765 565.570 2.410 566.790 ;
        RECT 3.230 565.570 1556.020 566.790 ;
        RECT 0.765 544.870 1556.020 565.570 ;
        RECT 0.765 543.650 2.410 544.870 ;
        RECT 3.230 543.650 1556.020 544.870 ;
        RECT 0.765 542.790 1556.020 543.650 ;
        RECT 0.765 541.570 2.410 542.790 ;
        RECT 3.230 541.570 1556.020 542.790 ;
        RECT 0.765 520.870 1556.020 541.570 ;
        RECT 0.765 519.650 2.410 520.870 ;
        RECT 3.230 519.650 1556.020 520.870 ;
        RECT 0.765 518.790 1556.020 519.650 ;
        RECT 0.765 517.570 2.410 518.790 ;
        RECT 3.230 517.570 1556.020 518.790 ;
        RECT 0.765 496.870 1556.020 517.570 ;
        RECT 0.765 495.650 2.410 496.870 ;
        RECT 3.230 495.650 1556.020 496.870 ;
        RECT 0.765 494.790 1556.020 495.650 ;
        RECT 0.765 493.570 2.410 494.790 ;
        RECT 3.230 493.570 1556.020 494.790 ;
        RECT 0.765 472.870 1556.020 493.570 ;
        RECT 0.765 471.650 2.410 472.870 ;
        RECT 3.230 471.650 1556.020 472.870 ;
        RECT 0.765 470.790 1556.020 471.650 ;
        RECT 0.765 469.570 2.410 470.790 ;
        RECT 3.230 469.570 1556.020 470.790 ;
        RECT 0.765 448.870 1556.020 469.570 ;
        RECT 0.765 447.650 2.410 448.870 ;
        RECT 3.230 447.650 1556.020 448.870 ;
        RECT 0.765 446.790 1556.020 447.650 ;
        RECT 0.765 445.570 2.410 446.790 ;
        RECT 3.230 445.570 1556.020 446.790 ;
        RECT 0.765 424.870 1556.020 445.570 ;
        RECT 0.765 423.650 2.410 424.870 ;
        RECT 3.230 423.650 1556.020 424.870 ;
        RECT 0.765 422.790 1556.020 423.650 ;
        RECT 0.765 421.570 2.410 422.790 ;
        RECT 3.230 421.570 1556.020 422.790 ;
        RECT 0.765 400.870 1556.020 421.570 ;
        RECT 0.765 399.650 2.410 400.870 ;
        RECT 3.230 399.650 1556.020 400.870 ;
        RECT 0.765 398.790 1556.020 399.650 ;
        RECT 0.765 397.570 2.410 398.790 ;
        RECT 3.230 397.570 1556.020 398.790 ;
        RECT 0.765 376.870 1556.020 397.570 ;
        RECT 0.765 375.650 2.410 376.870 ;
        RECT 3.230 375.650 1556.020 376.870 ;
        RECT 0.765 374.790 1556.020 375.650 ;
        RECT 0.765 373.570 2.410 374.790 ;
        RECT 3.230 373.570 1556.020 374.790 ;
        RECT 0.765 352.870 1556.020 373.570 ;
        RECT 0.765 351.650 2.410 352.870 ;
        RECT 3.230 351.650 1556.020 352.870 ;
        RECT 0.765 350.790 1556.020 351.650 ;
        RECT 0.765 349.570 2.410 350.790 ;
        RECT 3.230 349.570 1556.020 350.790 ;
        RECT 0.765 328.870 1556.020 349.570 ;
        RECT 0.765 327.650 2.410 328.870 ;
        RECT 3.230 327.650 1556.020 328.870 ;
        RECT 0.765 326.790 1556.020 327.650 ;
        RECT 0.765 325.570 2.410 326.790 ;
        RECT 3.230 325.570 1556.020 326.790 ;
        RECT 0.765 304.870 1556.020 325.570 ;
        RECT 0.765 303.650 2.410 304.870 ;
        RECT 3.230 303.650 1556.020 304.870 ;
        RECT 0.765 302.790 1556.020 303.650 ;
        RECT 0.765 301.570 2.410 302.790 ;
        RECT 3.230 301.570 1556.020 302.790 ;
        RECT 0.765 280.870 1556.020 301.570 ;
        RECT 0.765 279.650 2.410 280.870 ;
        RECT 3.230 279.650 1556.020 280.870 ;
        RECT 0.765 278.790 1556.020 279.650 ;
        RECT 0.765 277.570 2.410 278.790 ;
        RECT 3.230 277.570 1556.020 278.790 ;
        RECT 0.765 256.870 1556.020 277.570 ;
        RECT 0.765 255.650 2.410 256.870 ;
        RECT 3.230 255.650 1556.020 256.870 ;
        RECT 0.765 254.790 1556.020 255.650 ;
        RECT 0.765 253.570 2.410 254.790 ;
        RECT 3.230 253.570 1556.020 254.790 ;
        RECT 0.765 232.870 1556.020 253.570 ;
        RECT 0.765 231.650 2.410 232.870 ;
        RECT 3.230 231.650 1556.020 232.870 ;
        RECT 0.765 230.790 1556.020 231.650 ;
        RECT 0.765 229.570 2.410 230.790 ;
        RECT 3.230 229.570 1556.020 230.790 ;
        RECT 0.765 208.870 1556.020 229.570 ;
        RECT 0.765 207.650 2.410 208.870 ;
        RECT 3.230 207.650 1556.020 208.870 ;
        RECT 0.765 206.790 1556.020 207.650 ;
        RECT 0.765 205.570 2.410 206.790 ;
        RECT 3.230 205.570 1556.020 206.790 ;
        RECT 0.765 184.870 1556.020 205.570 ;
        RECT 0.765 183.650 2.410 184.870 ;
        RECT 3.230 183.650 1556.020 184.870 ;
        RECT 0.765 182.790 1556.020 183.650 ;
        RECT 0.765 181.570 2.410 182.790 ;
        RECT 3.230 181.570 1556.020 182.790 ;
        RECT 0.765 160.870 1556.020 181.570 ;
        RECT 0.765 159.650 2.410 160.870 ;
        RECT 3.230 159.650 1556.020 160.870 ;
        RECT 0.765 158.790 1556.020 159.650 ;
        RECT 0.765 157.570 2.410 158.790 ;
        RECT 3.230 157.570 1556.020 158.790 ;
        RECT 0.765 136.870 1556.020 157.570 ;
        RECT 0.765 135.650 2.410 136.870 ;
        RECT 3.230 135.650 1556.020 136.870 ;
        RECT 0.765 134.790 1556.020 135.650 ;
        RECT 0.765 133.570 2.410 134.790 ;
        RECT 3.230 133.570 1556.020 134.790 ;
        RECT 0.765 112.870 1556.020 133.570 ;
        RECT 0.765 111.650 2.410 112.870 ;
        RECT 3.230 111.650 1556.020 112.870 ;
        RECT 0.765 110.790 1556.020 111.650 ;
        RECT 0.765 109.570 2.410 110.790 ;
        RECT 3.230 109.570 1556.020 110.790 ;
        RECT 0.765 88.870 1556.020 109.570 ;
        RECT 0.765 87.650 2.410 88.870 ;
        RECT 3.230 87.650 1556.020 88.870 ;
        RECT 0.765 86.790 1556.020 87.650 ;
        RECT 0.765 85.570 2.410 86.790 ;
        RECT 3.230 85.570 1556.020 86.790 ;
        RECT 0.765 64.870 1556.020 85.570 ;
        RECT 0.765 63.650 2.410 64.870 ;
        RECT 3.230 63.650 1556.020 64.870 ;
        RECT 0.765 62.790 1556.020 63.650 ;
        RECT 0.765 61.570 2.410 62.790 ;
        RECT 3.230 61.570 1556.020 62.790 ;
        RECT 0.765 41.140 1556.020 61.570 ;
        RECT 0.765 39.580 2.410 41.140 ;
        RECT 1543.230 39.580 1556.020 41.140 ;
        RECT 0.765 31.260 1556.020 39.580 ;
        RECT 0.765 29.690 2.410 31.260 ;
        RECT 3.270 29.690 1556.020 31.260 ;
        RECT 0.765 19.700 1556.020 29.690 ;
        RECT 0.765 18.140 2.410 19.700 ;
        RECT 3.270 18.140 1556.020 19.700 ;
        RECT 0.765 11.170 1556.020 18.140 ;
        RECT 0.765 9.610 2.410 11.170 ;
        RECT 3.270 9.610 1556.020 11.170 ;
        RECT 0.765 0.295 1556.020 9.610 ;
      LAYER met3 ;
        RECT 0.000 1637.615 5.845 1638.230 ;
        RECT 7.415 1637.615 21.965 1638.230 ;
        RECT 23.535 1637.615 25.195 1638.230 ;
        RECT 0.000 1637.495 25.195 1637.615 ;
        RECT 26.295 1637.495 27.100 1638.230 ;
        RECT 28.200 1637.615 29.845 1638.230 ;
        RECT 31.415 1637.615 45.965 1638.230 ;
        RECT 47.535 1637.615 49.195 1638.230 ;
        RECT 28.200 1637.495 49.195 1637.615 ;
        RECT 50.295 1637.495 51.100 1638.230 ;
        RECT 52.200 1637.615 53.845 1638.230 ;
        RECT 55.415 1637.615 69.965 1638.230 ;
        RECT 71.535 1637.615 73.195 1638.230 ;
        RECT 52.200 1637.495 73.195 1637.615 ;
        RECT 74.295 1637.495 75.100 1638.230 ;
        RECT 76.200 1637.615 77.845 1638.230 ;
        RECT 79.415 1637.615 93.965 1638.230 ;
        RECT 95.535 1637.615 97.195 1638.230 ;
        RECT 76.200 1637.495 97.195 1637.615 ;
        RECT 98.295 1637.495 99.100 1638.230 ;
        RECT 100.200 1637.615 101.845 1638.230 ;
        RECT 103.415 1637.615 117.965 1638.230 ;
        RECT 119.535 1637.615 121.195 1638.230 ;
        RECT 100.200 1637.495 121.195 1637.615 ;
        RECT 122.295 1637.495 123.100 1638.230 ;
        RECT 124.200 1637.615 125.845 1638.230 ;
        RECT 127.415 1637.615 141.965 1638.230 ;
        RECT 143.535 1637.615 145.195 1638.230 ;
        RECT 124.200 1637.495 145.195 1637.615 ;
        RECT 146.295 1637.495 147.100 1638.230 ;
        RECT 148.200 1637.615 149.845 1638.230 ;
        RECT 151.415 1637.615 165.965 1638.230 ;
        RECT 167.535 1637.615 169.195 1638.230 ;
        RECT 148.200 1637.495 169.195 1637.615 ;
        RECT 170.295 1637.495 171.100 1638.230 ;
        RECT 172.200 1637.615 173.845 1638.230 ;
        RECT 175.415 1637.615 189.965 1638.230 ;
        RECT 191.535 1637.615 193.195 1638.230 ;
        RECT 172.200 1637.495 193.195 1637.615 ;
        RECT 194.295 1637.495 195.100 1638.230 ;
        RECT 196.200 1637.615 197.845 1638.230 ;
        RECT 199.415 1637.615 213.965 1638.230 ;
        RECT 215.535 1637.615 217.195 1638.230 ;
        RECT 196.200 1637.495 217.195 1637.615 ;
        RECT 218.295 1637.495 219.100 1638.230 ;
        RECT 220.200 1637.615 221.845 1638.230 ;
        RECT 223.415 1637.615 237.965 1638.230 ;
        RECT 239.535 1637.615 241.195 1638.230 ;
        RECT 220.200 1637.495 241.195 1637.615 ;
        RECT 242.295 1637.495 243.100 1638.230 ;
        RECT 244.200 1637.615 245.845 1638.230 ;
        RECT 247.415 1637.615 261.965 1638.230 ;
        RECT 263.535 1637.615 265.195 1638.230 ;
        RECT 244.200 1637.495 265.195 1637.615 ;
        RECT 266.295 1637.495 267.100 1638.230 ;
        RECT 268.200 1637.615 269.845 1638.230 ;
        RECT 271.415 1637.615 285.965 1638.230 ;
        RECT 287.535 1637.615 289.195 1638.230 ;
        RECT 268.200 1637.495 289.195 1637.615 ;
        RECT 290.295 1637.495 291.100 1638.230 ;
        RECT 292.200 1637.615 293.845 1638.230 ;
        RECT 295.415 1637.615 309.965 1638.230 ;
        RECT 311.535 1637.615 313.195 1638.230 ;
        RECT 292.200 1637.495 313.195 1637.615 ;
        RECT 314.295 1637.495 315.100 1638.230 ;
        RECT 316.200 1637.615 317.845 1638.230 ;
        RECT 319.415 1637.615 333.965 1638.230 ;
        RECT 335.535 1637.615 337.195 1638.230 ;
        RECT 316.200 1637.495 337.195 1637.615 ;
        RECT 338.295 1637.495 339.100 1638.230 ;
        RECT 340.200 1637.615 341.845 1638.230 ;
        RECT 343.415 1637.615 357.965 1638.230 ;
        RECT 359.535 1637.615 361.195 1638.230 ;
        RECT 340.200 1637.495 361.195 1637.615 ;
        RECT 362.295 1637.495 363.100 1638.230 ;
        RECT 364.200 1637.615 365.845 1638.230 ;
        RECT 367.415 1637.615 381.965 1638.230 ;
        RECT 383.535 1637.615 385.195 1638.230 ;
        RECT 364.200 1637.495 385.195 1637.615 ;
        RECT 386.295 1637.495 387.100 1638.230 ;
        RECT 388.200 1637.615 389.845 1638.230 ;
        RECT 391.415 1637.615 405.965 1638.230 ;
        RECT 407.535 1637.615 409.195 1638.230 ;
        RECT 388.200 1637.495 409.195 1637.615 ;
        RECT 410.295 1637.495 411.100 1638.230 ;
        RECT 412.200 1637.615 413.845 1638.230 ;
        RECT 415.415 1637.615 429.965 1638.230 ;
        RECT 431.535 1637.615 433.195 1638.230 ;
        RECT 412.200 1637.495 433.195 1637.615 ;
        RECT 434.295 1637.495 435.100 1638.230 ;
        RECT 436.200 1637.615 437.845 1638.230 ;
        RECT 439.415 1637.615 453.965 1638.230 ;
        RECT 455.535 1637.615 457.195 1638.230 ;
        RECT 436.200 1637.495 457.195 1637.615 ;
        RECT 458.295 1637.495 459.100 1638.230 ;
        RECT 460.200 1637.615 461.845 1638.230 ;
        RECT 463.415 1637.615 477.965 1638.230 ;
        RECT 479.535 1637.615 481.195 1638.230 ;
        RECT 460.200 1637.495 481.195 1637.615 ;
        RECT 482.295 1637.495 483.100 1638.230 ;
        RECT 484.200 1637.615 485.845 1638.230 ;
        RECT 487.415 1637.615 501.965 1638.230 ;
        RECT 503.535 1637.615 505.195 1638.230 ;
        RECT 484.200 1637.495 505.195 1637.615 ;
        RECT 506.295 1637.495 507.100 1638.230 ;
        RECT 508.200 1637.615 509.845 1638.230 ;
        RECT 511.415 1637.615 525.965 1638.230 ;
        RECT 527.535 1637.615 529.195 1638.230 ;
        RECT 508.200 1637.495 529.195 1637.615 ;
        RECT 530.295 1637.495 531.100 1638.230 ;
        RECT 532.200 1637.615 533.845 1638.230 ;
        RECT 535.415 1637.615 549.965 1638.230 ;
        RECT 551.535 1637.615 553.195 1638.230 ;
        RECT 532.200 1637.495 553.195 1637.615 ;
        RECT 554.295 1637.495 555.100 1638.230 ;
        RECT 556.200 1637.615 557.845 1638.230 ;
        RECT 559.415 1637.615 573.965 1638.230 ;
        RECT 575.535 1637.615 577.195 1638.230 ;
        RECT 556.200 1637.495 577.195 1637.615 ;
        RECT 578.295 1637.495 579.100 1638.230 ;
        RECT 580.200 1637.615 581.845 1638.230 ;
        RECT 583.415 1637.615 597.965 1638.230 ;
        RECT 599.535 1637.615 601.195 1638.230 ;
        RECT 580.200 1637.495 601.195 1637.615 ;
        RECT 602.295 1637.495 603.100 1638.230 ;
        RECT 604.200 1637.615 605.845 1638.230 ;
        RECT 607.415 1637.615 621.965 1638.230 ;
        RECT 623.535 1637.615 625.195 1638.230 ;
        RECT 604.200 1637.495 625.195 1637.615 ;
        RECT 626.295 1637.495 627.100 1638.230 ;
        RECT 628.200 1637.615 629.845 1638.230 ;
        RECT 631.415 1637.615 645.965 1638.230 ;
        RECT 647.535 1637.615 649.195 1638.230 ;
        RECT 628.200 1637.495 649.195 1637.615 ;
        RECT 650.295 1637.495 651.100 1638.230 ;
        RECT 652.200 1637.615 653.845 1638.230 ;
        RECT 655.415 1637.615 669.965 1638.230 ;
        RECT 671.535 1637.615 673.195 1638.230 ;
        RECT 652.200 1637.495 673.195 1637.615 ;
        RECT 674.295 1637.495 675.100 1638.230 ;
        RECT 676.200 1637.615 677.845 1638.230 ;
        RECT 679.415 1637.615 693.965 1638.230 ;
        RECT 695.535 1637.615 697.195 1638.230 ;
        RECT 676.200 1637.495 697.195 1637.615 ;
        RECT 698.295 1637.495 699.100 1638.230 ;
        RECT 700.200 1637.615 701.845 1638.230 ;
        RECT 703.415 1637.615 717.965 1638.230 ;
        RECT 719.535 1637.615 721.195 1638.230 ;
        RECT 700.200 1637.495 721.195 1637.615 ;
        RECT 722.295 1637.495 723.100 1638.230 ;
        RECT 724.200 1637.615 725.845 1638.230 ;
        RECT 727.415 1637.615 741.965 1638.230 ;
        RECT 743.535 1637.615 745.195 1638.230 ;
        RECT 724.200 1637.495 745.195 1637.615 ;
        RECT 746.295 1637.495 747.100 1638.230 ;
        RECT 748.200 1637.615 749.845 1638.230 ;
        RECT 751.415 1637.615 765.965 1638.230 ;
        RECT 767.535 1637.615 769.195 1638.230 ;
        RECT 748.200 1637.495 769.195 1637.615 ;
        RECT 770.295 1637.615 773.845 1638.230 ;
        RECT 775.415 1637.615 789.965 1638.230 ;
        RECT 791.535 1637.615 793.195 1638.230 ;
        RECT 770.295 1637.495 793.195 1637.615 ;
        RECT 794.295 1637.495 795.100 1638.230 ;
        RECT 796.200 1637.615 797.845 1638.230 ;
        RECT 799.415 1637.615 813.965 1638.230 ;
        RECT 815.535 1637.615 817.195 1638.230 ;
        RECT 796.200 1637.495 817.195 1637.615 ;
        RECT 818.295 1637.495 819.100 1638.230 ;
        RECT 820.200 1637.615 821.845 1638.230 ;
        RECT 823.415 1637.615 837.965 1638.230 ;
        RECT 839.535 1637.615 841.195 1638.230 ;
        RECT 820.200 1637.495 841.195 1637.615 ;
        RECT 842.295 1637.495 843.100 1638.230 ;
        RECT 844.200 1637.615 845.845 1638.230 ;
        RECT 847.415 1637.615 861.965 1638.230 ;
        RECT 863.535 1637.615 865.195 1638.230 ;
        RECT 844.200 1637.495 865.195 1637.615 ;
        RECT 866.295 1637.495 867.100 1638.230 ;
        RECT 868.200 1637.615 869.845 1638.230 ;
        RECT 871.415 1637.615 885.965 1638.230 ;
        RECT 887.535 1637.615 889.195 1638.230 ;
        RECT 868.200 1637.495 889.195 1637.615 ;
        RECT 890.295 1637.495 891.100 1638.230 ;
        RECT 892.200 1637.615 893.845 1638.230 ;
        RECT 895.415 1637.615 909.965 1638.230 ;
        RECT 911.535 1637.615 913.195 1638.230 ;
        RECT 892.200 1637.495 913.195 1637.615 ;
        RECT 914.295 1637.495 915.100 1638.230 ;
        RECT 916.200 1637.615 917.845 1638.230 ;
        RECT 919.415 1637.615 933.965 1638.230 ;
        RECT 935.535 1637.615 937.195 1638.230 ;
        RECT 916.200 1637.495 937.195 1637.615 ;
        RECT 938.295 1637.495 939.100 1638.230 ;
        RECT 940.200 1637.615 941.845 1638.230 ;
        RECT 943.415 1637.615 957.965 1638.230 ;
        RECT 959.535 1637.615 961.195 1638.230 ;
        RECT 940.200 1637.495 961.195 1637.615 ;
        RECT 962.295 1637.495 963.100 1638.230 ;
        RECT 964.200 1637.615 965.845 1638.230 ;
        RECT 967.415 1637.615 981.965 1638.230 ;
        RECT 983.535 1637.615 985.195 1638.230 ;
        RECT 964.200 1637.495 985.195 1637.615 ;
        RECT 986.295 1637.495 987.100 1638.230 ;
        RECT 988.200 1637.615 989.845 1638.230 ;
        RECT 991.415 1637.615 1005.965 1638.230 ;
        RECT 1007.535 1637.615 1009.195 1638.230 ;
        RECT 988.200 1637.495 1009.195 1637.615 ;
        RECT 1010.295 1637.495 1011.100 1638.230 ;
        RECT 1012.200 1637.615 1013.845 1638.230 ;
        RECT 1015.415 1637.615 1029.965 1638.230 ;
        RECT 1031.535 1637.615 1033.195 1638.230 ;
        RECT 1012.200 1637.495 1033.195 1637.615 ;
        RECT 1034.295 1637.495 1035.100 1638.230 ;
        RECT 1036.200 1637.615 1037.845 1638.230 ;
        RECT 1039.415 1637.615 1053.965 1638.230 ;
        RECT 1055.535 1637.615 1057.195 1638.230 ;
        RECT 1036.200 1637.495 1057.195 1637.615 ;
        RECT 1058.295 1637.495 1059.100 1638.230 ;
        RECT 1060.200 1637.615 1061.845 1638.230 ;
        RECT 1063.415 1637.615 1077.965 1638.230 ;
        RECT 1079.535 1637.615 1081.195 1638.230 ;
        RECT 1060.200 1637.495 1081.195 1637.615 ;
        RECT 1082.295 1637.495 1083.100 1638.230 ;
        RECT 1084.200 1637.615 1085.845 1638.230 ;
        RECT 1087.415 1637.615 1101.965 1638.230 ;
        RECT 1103.535 1637.615 1105.195 1638.230 ;
        RECT 1084.200 1637.495 1105.195 1637.615 ;
        RECT 1106.295 1637.495 1107.100 1638.230 ;
        RECT 1108.200 1637.615 1109.845 1638.230 ;
        RECT 1111.415 1637.615 1125.965 1638.230 ;
        RECT 1127.535 1637.615 1129.195 1638.230 ;
        RECT 1108.200 1637.495 1129.195 1637.615 ;
        RECT 1130.295 1637.495 1131.100 1638.230 ;
        RECT 1132.200 1637.615 1133.845 1638.230 ;
        RECT 1135.415 1637.615 1149.965 1638.230 ;
        RECT 1151.535 1637.615 1153.195 1638.230 ;
        RECT 1132.200 1637.495 1153.195 1637.615 ;
        RECT 1154.295 1637.495 1155.100 1638.230 ;
        RECT 1156.200 1637.615 1157.845 1638.230 ;
        RECT 1159.415 1637.615 1173.965 1638.230 ;
        RECT 1175.535 1637.615 1177.195 1638.230 ;
        RECT 1156.200 1637.495 1177.195 1637.615 ;
        RECT 1178.295 1637.495 1179.100 1638.230 ;
        RECT 1180.200 1637.615 1181.845 1638.230 ;
        RECT 1183.415 1637.615 1197.965 1638.230 ;
        RECT 1199.535 1637.615 1201.195 1638.230 ;
        RECT 1180.200 1637.495 1201.195 1637.615 ;
        RECT 1202.295 1637.495 1203.100 1638.230 ;
        RECT 1204.200 1637.615 1205.845 1638.230 ;
        RECT 1207.415 1637.615 1221.965 1638.230 ;
        RECT 1223.535 1637.615 1225.195 1638.230 ;
        RECT 1204.200 1637.495 1225.195 1637.615 ;
        RECT 1226.295 1637.495 1227.100 1638.230 ;
        RECT 1228.200 1637.615 1229.845 1638.230 ;
        RECT 1231.415 1637.615 1245.965 1638.230 ;
        RECT 1247.535 1637.615 1249.195 1638.230 ;
        RECT 1228.200 1637.495 1249.195 1637.615 ;
        RECT 1250.295 1637.495 1251.100 1638.230 ;
        RECT 1252.200 1637.615 1253.845 1638.230 ;
        RECT 1255.415 1637.615 1269.965 1638.230 ;
        RECT 1271.535 1637.615 1273.195 1638.230 ;
        RECT 1252.200 1637.495 1273.195 1637.615 ;
        RECT 1274.295 1637.495 1275.100 1638.230 ;
        RECT 1276.200 1637.615 1277.845 1638.230 ;
        RECT 1279.415 1637.615 1293.965 1638.230 ;
        RECT 1295.535 1637.615 1297.195 1638.230 ;
        RECT 1276.200 1637.495 1297.195 1637.615 ;
        RECT 1298.295 1637.495 1299.100 1638.230 ;
        RECT 1300.200 1637.615 1301.845 1638.230 ;
        RECT 1303.415 1637.615 1317.965 1638.230 ;
        RECT 1319.535 1637.615 1321.195 1638.230 ;
        RECT 1300.200 1637.495 1321.195 1637.615 ;
        RECT 1322.295 1637.495 1323.100 1638.230 ;
        RECT 1324.200 1637.615 1325.845 1638.230 ;
        RECT 1327.415 1637.615 1341.965 1638.230 ;
        RECT 1343.535 1637.615 1345.195 1638.230 ;
        RECT 1324.200 1637.495 1345.195 1637.615 ;
        RECT 1346.295 1637.495 1347.100 1638.230 ;
        RECT 1348.200 1637.615 1349.845 1638.230 ;
        RECT 1351.415 1637.615 1365.965 1638.230 ;
        RECT 1367.535 1637.615 1369.195 1638.230 ;
        RECT 1348.200 1637.495 1369.195 1637.615 ;
        RECT 1370.295 1637.495 1371.100 1638.230 ;
        RECT 1372.200 1637.615 1373.845 1638.230 ;
        RECT 1375.415 1637.615 1389.965 1638.230 ;
        RECT 1391.535 1637.615 1393.195 1638.230 ;
        RECT 1372.200 1637.495 1393.195 1637.615 ;
        RECT 1394.295 1637.495 1395.100 1638.230 ;
        RECT 1396.200 1637.615 1397.845 1638.230 ;
        RECT 1399.415 1637.615 1413.965 1638.230 ;
        RECT 1415.535 1637.615 1417.195 1638.230 ;
        RECT 1396.200 1637.495 1417.195 1637.615 ;
        RECT 1418.295 1637.495 1419.100 1638.230 ;
        RECT 1420.200 1637.615 1421.845 1638.230 ;
        RECT 1423.415 1637.615 1437.965 1638.230 ;
        RECT 1439.535 1637.615 1441.195 1638.230 ;
        RECT 1420.200 1637.495 1441.195 1637.615 ;
        RECT 1442.295 1637.495 1443.100 1638.230 ;
        RECT 1444.200 1637.615 1445.845 1638.230 ;
        RECT 1447.415 1637.615 1461.965 1638.230 ;
        RECT 1463.535 1637.615 1465.195 1638.230 ;
        RECT 1444.200 1637.495 1465.195 1637.615 ;
        RECT 1466.295 1637.495 1467.100 1638.230 ;
        RECT 1468.200 1637.615 1469.845 1638.230 ;
        RECT 1471.415 1637.615 1485.965 1638.230 ;
        RECT 1487.535 1637.615 1489.195 1638.230 ;
        RECT 1468.200 1637.495 1489.195 1637.615 ;
        RECT 1490.295 1637.495 1491.100 1638.230 ;
        RECT 1492.200 1637.615 1493.845 1638.230 ;
        RECT 1495.415 1637.615 1509.965 1638.230 ;
        RECT 1511.535 1637.615 1513.195 1638.230 ;
        RECT 1492.200 1637.495 1513.195 1637.615 ;
        RECT 1514.295 1637.495 1515.100 1638.230 ;
        RECT 1516.200 1637.615 1517.845 1638.230 ;
        RECT 1519.415 1637.615 1533.965 1638.230 ;
        RECT 1535.535 1637.615 1537.195 1638.230 ;
        RECT 1516.200 1637.495 1537.195 1637.615 ;
        RECT 1538.295 1637.495 1556.020 1638.230 ;
        RECT 0.000 1635.925 1556.020 1637.495 ;
        RECT 0.000 1634.825 771.100 1635.925 ;
        RECT 772.200 1634.825 1556.020 1635.925 ;
        RECT 0.000 823.120 1556.020 1634.825 ;
        RECT 0.000 815.320 1555.125 823.120 ;
        RECT 0.000 0.945 1556.020 815.320 ;
        RECT 0.000 0.245 3.100 0.945 ;
        RECT 4.200 0.825 25.195 0.945 ;
        RECT 4.200 0.245 5.845 0.825 ;
        RECT 7.415 0.245 21.965 0.825 ;
        RECT 23.535 0.245 25.195 0.825 ;
        RECT 26.295 0.245 27.100 0.945 ;
        RECT 28.200 0.825 49.195 0.945 ;
        RECT 28.200 0.245 29.845 0.825 ;
        RECT 31.415 0.245 45.965 0.825 ;
        RECT 47.535 0.245 49.195 0.825 ;
        RECT 50.295 0.245 51.100 0.945 ;
        RECT 52.200 0.825 73.195 0.945 ;
        RECT 52.200 0.245 53.845 0.825 ;
        RECT 55.415 0.245 69.965 0.825 ;
        RECT 71.535 0.245 73.195 0.825 ;
        RECT 74.295 0.245 75.100 0.945 ;
        RECT 76.200 0.825 97.195 0.945 ;
        RECT 76.200 0.245 77.845 0.825 ;
        RECT 79.415 0.245 93.965 0.825 ;
        RECT 95.535 0.245 97.195 0.825 ;
        RECT 98.295 0.245 99.100 0.945 ;
        RECT 100.200 0.825 121.195 0.945 ;
        RECT 100.200 0.245 101.845 0.825 ;
        RECT 103.415 0.245 117.965 0.825 ;
        RECT 119.535 0.245 121.195 0.825 ;
        RECT 122.295 0.245 123.100 0.945 ;
        RECT 124.200 0.825 145.195 0.945 ;
        RECT 124.200 0.245 125.845 0.825 ;
        RECT 127.415 0.245 141.965 0.825 ;
        RECT 143.535 0.245 145.195 0.825 ;
        RECT 146.295 0.245 147.100 0.945 ;
        RECT 148.200 0.825 169.195 0.945 ;
        RECT 148.200 0.245 149.845 0.825 ;
        RECT 151.415 0.245 165.965 0.825 ;
        RECT 167.535 0.245 169.195 0.825 ;
        RECT 170.295 0.245 171.100 0.945 ;
        RECT 172.200 0.825 193.195 0.945 ;
        RECT 172.200 0.245 173.845 0.825 ;
        RECT 175.415 0.245 189.965 0.825 ;
        RECT 191.535 0.245 193.195 0.825 ;
        RECT 194.295 0.245 195.100 0.945 ;
        RECT 196.200 0.825 217.195 0.945 ;
        RECT 196.200 0.245 197.845 0.825 ;
        RECT 199.415 0.245 213.965 0.825 ;
        RECT 215.535 0.245 217.195 0.825 ;
        RECT 218.295 0.245 219.100 0.945 ;
        RECT 220.200 0.825 241.195 0.945 ;
        RECT 220.200 0.245 221.845 0.825 ;
        RECT 223.415 0.245 237.965 0.825 ;
        RECT 239.535 0.245 241.195 0.825 ;
        RECT 242.295 0.245 243.100 0.945 ;
        RECT 244.200 0.825 265.195 0.945 ;
        RECT 244.200 0.245 245.845 0.825 ;
        RECT 247.415 0.245 261.965 0.825 ;
        RECT 263.535 0.245 265.195 0.825 ;
        RECT 266.295 0.245 267.100 0.945 ;
        RECT 268.200 0.825 289.195 0.945 ;
        RECT 268.200 0.245 269.845 0.825 ;
        RECT 271.415 0.245 285.965 0.825 ;
        RECT 287.535 0.245 289.195 0.825 ;
        RECT 290.295 0.245 291.100 0.945 ;
        RECT 292.200 0.825 313.195 0.945 ;
        RECT 292.200 0.245 293.845 0.825 ;
        RECT 295.415 0.245 309.965 0.825 ;
        RECT 311.535 0.245 313.195 0.825 ;
        RECT 314.295 0.245 315.100 0.945 ;
        RECT 316.200 0.825 337.195 0.945 ;
        RECT 316.200 0.245 317.845 0.825 ;
        RECT 319.415 0.245 333.965 0.825 ;
        RECT 335.535 0.245 337.195 0.825 ;
        RECT 338.295 0.245 339.100 0.945 ;
        RECT 340.200 0.825 361.195 0.945 ;
        RECT 340.200 0.245 341.845 0.825 ;
        RECT 343.415 0.245 357.965 0.825 ;
        RECT 359.535 0.245 361.195 0.825 ;
        RECT 362.295 0.245 363.100 0.945 ;
        RECT 364.200 0.825 385.195 0.945 ;
        RECT 364.200 0.245 365.845 0.825 ;
        RECT 367.415 0.245 381.965 0.825 ;
        RECT 383.535 0.245 385.195 0.825 ;
        RECT 386.295 0.245 387.100 0.945 ;
        RECT 388.200 0.825 409.195 0.945 ;
        RECT 388.200 0.245 389.845 0.825 ;
        RECT 391.415 0.245 405.965 0.825 ;
        RECT 407.535 0.245 409.195 0.825 ;
        RECT 410.295 0.245 411.100 0.945 ;
        RECT 412.200 0.825 433.195 0.945 ;
        RECT 412.200 0.245 413.845 0.825 ;
        RECT 415.415 0.245 429.965 0.825 ;
        RECT 431.535 0.245 433.195 0.825 ;
        RECT 434.295 0.245 435.100 0.945 ;
        RECT 436.200 0.825 457.195 0.945 ;
        RECT 436.200 0.245 437.845 0.825 ;
        RECT 439.415 0.245 453.965 0.825 ;
        RECT 455.535 0.245 457.195 0.825 ;
        RECT 458.295 0.245 459.100 0.945 ;
        RECT 460.200 0.825 481.195 0.945 ;
        RECT 460.200 0.245 461.845 0.825 ;
        RECT 463.415 0.245 477.965 0.825 ;
        RECT 479.535 0.245 481.195 0.825 ;
        RECT 482.295 0.245 483.100 0.945 ;
        RECT 484.200 0.825 505.195 0.945 ;
        RECT 484.200 0.245 485.845 0.825 ;
        RECT 487.415 0.245 501.965 0.825 ;
        RECT 503.535 0.245 505.195 0.825 ;
        RECT 506.295 0.245 507.100 0.945 ;
        RECT 508.200 0.825 529.195 0.945 ;
        RECT 508.200 0.245 509.845 0.825 ;
        RECT 511.415 0.245 525.965 0.825 ;
        RECT 527.535 0.245 529.195 0.825 ;
        RECT 530.295 0.245 531.100 0.945 ;
        RECT 532.200 0.825 553.195 0.945 ;
        RECT 532.200 0.245 533.845 0.825 ;
        RECT 535.415 0.245 549.965 0.825 ;
        RECT 551.535 0.245 553.195 0.825 ;
        RECT 554.295 0.245 555.100 0.945 ;
        RECT 556.200 0.825 577.195 0.945 ;
        RECT 556.200 0.245 557.845 0.825 ;
        RECT 559.415 0.245 573.965 0.825 ;
        RECT 575.535 0.245 577.195 0.825 ;
        RECT 578.295 0.245 579.100 0.945 ;
        RECT 580.200 0.825 601.195 0.945 ;
        RECT 580.200 0.245 581.845 0.825 ;
        RECT 583.415 0.245 597.965 0.825 ;
        RECT 599.535 0.245 601.195 0.825 ;
        RECT 602.295 0.245 603.100 0.945 ;
        RECT 604.200 0.825 625.195 0.945 ;
        RECT 604.200 0.245 605.845 0.825 ;
        RECT 607.415 0.245 621.965 0.825 ;
        RECT 623.535 0.245 625.195 0.825 ;
        RECT 626.295 0.245 627.100 0.945 ;
        RECT 628.200 0.825 649.195 0.945 ;
        RECT 628.200 0.245 629.845 0.825 ;
        RECT 631.415 0.245 645.965 0.825 ;
        RECT 647.535 0.245 649.195 0.825 ;
        RECT 650.295 0.245 651.100 0.945 ;
        RECT 652.200 0.825 673.195 0.945 ;
        RECT 652.200 0.245 653.845 0.825 ;
        RECT 655.415 0.245 669.965 0.825 ;
        RECT 671.535 0.245 673.195 0.825 ;
        RECT 674.295 0.245 675.100 0.945 ;
        RECT 676.200 0.825 697.195 0.945 ;
        RECT 676.200 0.245 677.845 0.825 ;
        RECT 679.415 0.245 693.965 0.825 ;
        RECT 695.535 0.245 697.195 0.825 ;
        RECT 698.295 0.245 699.100 0.945 ;
        RECT 700.200 0.825 721.195 0.945 ;
        RECT 700.200 0.245 701.845 0.825 ;
        RECT 703.415 0.245 717.965 0.825 ;
        RECT 719.535 0.245 721.195 0.825 ;
        RECT 722.295 0.245 723.100 0.945 ;
        RECT 724.200 0.825 745.195 0.945 ;
        RECT 724.200 0.245 725.845 0.825 ;
        RECT 727.415 0.245 741.965 0.825 ;
        RECT 743.535 0.245 745.195 0.825 ;
        RECT 746.295 0.245 747.100 0.945 ;
        RECT 748.200 0.825 769.195 0.945 ;
        RECT 748.200 0.245 749.845 0.825 ;
        RECT 751.415 0.245 765.965 0.825 ;
        RECT 767.535 0.245 769.195 0.825 ;
        RECT 770.295 0.245 771.100 0.945 ;
        RECT 772.200 0.825 793.195 0.945 ;
        RECT 772.200 0.245 773.845 0.825 ;
        RECT 775.415 0.245 789.965 0.825 ;
        RECT 791.535 0.245 793.195 0.825 ;
        RECT 794.295 0.245 795.100 0.945 ;
        RECT 796.200 0.825 817.195 0.945 ;
        RECT 796.200 0.245 797.845 0.825 ;
        RECT 799.415 0.245 813.965 0.825 ;
        RECT 815.535 0.245 817.195 0.825 ;
        RECT 818.295 0.245 819.100 0.945 ;
        RECT 820.200 0.825 841.195 0.945 ;
        RECT 820.200 0.245 821.845 0.825 ;
        RECT 823.415 0.245 837.965 0.825 ;
        RECT 839.535 0.245 841.195 0.825 ;
        RECT 842.295 0.245 843.100 0.945 ;
        RECT 844.200 0.825 865.195 0.945 ;
        RECT 844.200 0.245 845.845 0.825 ;
        RECT 847.415 0.245 861.965 0.825 ;
        RECT 863.535 0.245 865.195 0.825 ;
        RECT 866.295 0.245 867.100 0.945 ;
        RECT 868.200 0.825 889.195 0.945 ;
        RECT 868.200 0.245 869.845 0.825 ;
        RECT 871.415 0.245 885.965 0.825 ;
        RECT 887.535 0.245 889.195 0.825 ;
        RECT 890.295 0.245 891.100 0.945 ;
        RECT 892.200 0.825 913.195 0.945 ;
        RECT 892.200 0.245 893.845 0.825 ;
        RECT 895.415 0.245 909.965 0.825 ;
        RECT 911.535 0.245 913.195 0.825 ;
        RECT 914.295 0.245 915.100 0.945 ;
        RECT 916.200 0.825 937.195 0.945 ;
        RECT 916.200 0.245 917.845 0.825 ;
        RECT 919.415 0.245 933.965 0.825 ;
        RECT 935.535 0.245 937.195 0.825 ;
        RECT 938.295 0.245 939.100 0.945 ;
        RECT 940.200 0.825 961.195 0.945 ;
        RECT 940.200 0.245 941.845 0.825 ;
        RECT 943.415 0.245 957.965 0.825 ;
        RECT 959.535 0.245 961.195 0.825 ;
        RECT 962.295 0.245 963.100 0.945 ;
        RECT 964.200 0.825 985.195 0.945 ;
        RECT 964.200 0.245 965.845 0.825 ;
        RECT 967.415 0.245 981.965 0.825 ;
        RECT 983.535 0.245 985.195 0.825 ;
        RECT 986.295 0.245 987.100 0.945 ;
        RECT 988.200 0.825 1009.195 0.945 ;
        RECT 988.200 0.245 989.845 0.825 ;
        RECT 991.415 0.245 1005.965 0.825 ;
        RECT 1007.535 0.245 1009.195 0.825 ;
        RECT 1010.295 0.245 1011.100 0.945 ;
        RECT 1012.200 0.825 1033.195 0.945 ;
        RECT 1012.200 0.245 1013.845 0.825 ;
        RECT 1015.415 0.245 1029.965 0.825 ;
        RECT 1031.535 0.245 1033.195 0.825 ;
        RECT 1034.295 0.245 1035.100 0.945 ;
        RECT 1036.200 0.825 1057.195 0.945 ;
        RECT 1036.200 0.245 1037.845 0.825 ;
        RECT 1039.415 0.245 1053.965 0.825 ;
        RECT 1055.535 0.245 1057.195 0.825 ;
        RECT 1058.295 0.245 1059.100 0.945 ;
        RECT 1060.200 0.825 1081.195 0.945 ;
        RECT 1060.200 0.245 1061.845 0.825 ;
        RECT 1063.415 0.245 1077.965 0.825 ;
        RECT 1079.535 0.245 1081.195 0.825 ;
        RECT 1082.295 0.245 1083.100 0.945 ;
        RECT 1084.200 0.825 1105.195 0.945 ;
        RECT 1084.200 0.245 1085.845 0.825 ;
        RECT 1087.415 0.245 1101.965 0.825 ;
        RECT 1103.535 0.245 1105.195 0.825 ;
        RECT 1106.295 0.245 1107.100 0.945 ;
        RECT 1108.200 0.825 1129.195 0.945 ;
        RECT 1108.200 0.245 1109.845 0.825 ;
        RECT 1111.415 0.245 1125.965 0.825 ;
        RECT 1127.535 0.245 1129.195 0.825 ;
        RECT 1130.295 0.245 1131.100 0.945 ;
        RECT 1132.200 0.825 1153.195 0.945 ;
        RECT 1132.200 0.245 1133.845 0.825 ;
        RECT 1135.415 0.245 1149.965 0.825 ;
        RECT 1151.535 0.245 1153.195 0.825 ;
        RECT 1154.295 0.245 1155.100 0.945 ;
        RECT 1156.200 0.825 1177.195 0.945 ;
        RECT 1156.200 0.245 1157.845 0.825 ;
        RECT 1159.415 0.245 1173.965 0.825 ;
        RECT 1175.535 0.245 1177.195 0.825 ;
        RECT 1178.295 0.245 1179.100 0.945 ;
        RECT 1180.200 0.825 1201.195 0.945 ;
        RECT 1180.200 0.245 1181.845 0.825 ;
        RECT 1183.415 0.245 1197.965 0.825 ;
        RECT 1199.535 0.245 1201.195 0.825 ;
        RECT 1202.295 0.245 1203.100 0.945 ;
        RECT 1204.200 0.825 1225.195 0.945 ;
        RECT 1204.200 0.245 1205.845 0.825 ;
        RECT 1207.415 0.245 1221.965 0.825 ;
        RECT 1223.535 0.245 1225.195 0.825 ;
        RECT 1226.295 0.245 1227.100 0.945 ;
        RECT 1228.200 0.825 1249.195 0.945 ;
        RECT 1228.200 0.245 1229.845 0.825 ;
        RECT 1231.415 0.245 1245.965 0.825 ;
        RECT 1247.535 0.245 1249.195 0.825 ;
        RECT 1250.295 0.245 1251.100 0.945 ;
        RECT 1252.200 0.825 1273.195 0.945 ;
        RECT 1252.200 0.245 1253.845 0.825 ;
        RECT 1255.415 0.245 1269.965 0.825 ;
        RECT 1271.535 0.245 1273.195 0.825 ;
        RECT 1274.295 0.245 1275.100 0.945 ;
        RECT 1276.200 0.825 1297.195 0.945 ;
        RECT 1276.200 0.245 1277.845 0.825 ;
        RECT 1279.415 0.245 1293.965 0.825 ;
        RECT 1295.535 0.245 1297.195 0.825 ;
        RECT 1298.295 0.245 1299.100 0.945 ;
        RECT 1300.200 0.825 1321.195 0.945 ;
        RECT 1300.200 0.245 1301.845 0.825 ;
        RECT 1303.415 0.245 1317.965 0.825 ;
        RECT 1319.535 0.245 1321.195 0.825 ;
        RECT 1322.295 0.245 1323.100 0.945 ;
        RECT 1324.200 0.825 1345.195 0.945 ;
        RECT 1324.200 0.245 1325.845 0.825 ;
        RECT 1327.415 0.245 1341.965 0.825 ;
        RECT 1343.535 0.245 1345.195 0.825 ;
        RECT 1346.295 0.245 1347.100 0.945 ;
        RECT 1348.200 0.825 1369.195 0.945 ;
        RECT 1348.200 0.245 1349.845 0.825 ;
        RECT 1351.415 0.245 1365.965 0.825 ;
        RECT 1367.535 0.245 1369.195 0.825 ;
        RECT 1370.295 0.245 1371.100 0.945 ;
        RECT 1372.200 0.825 1393.195 0.945 ;
        RECT 1372.200 0.245 1373.845 0.825 ;
        RECT 1375.415 0.245 1389.965 0.825 ;
        RECT 1391.535 0.245 1393.195 0.825 ;
        RECT 1394.295 0.245 1395.100 0.945 ;
        RECT 1396.200 0.825 1417.195 0.945 ;
        RECT 1396.200 0.245 1397.845 0.825 ;
        RECT 1399.415 0.245 1413.965 0.825 ;
        RECT 1415.535 0.245 1417.195 0.825 ;
        RECT 1418.295 0.245 1419.100 0.945 ;
        RECT 1420.200 0.825 1441.195 0.945 ;
        RECT 1420.200 0.245 1421.845 0.825 ;
        RECT 1423.415 0.245 1437.965 0.825 ;
        RECT 1439.535 0.245 1441.195 0.825 ;
        RECT 1442.295 0.245 1443.100 0.945 ;
        RECT 1444.200 0.825 1465.195 0.945 ;
        RECT 1444.200 0.245 1445.845 0.825 ;
        RECT 1447.415 0.245 1461.965 0.825 ;
        RECT 1463.535 0.245 1465.195 0.825 ;
        RECT 1466.295 0.245 1467.100 0.945 ;
        RECT 1468.200 0.825 1489.195 0.945 ;
        RECT 1468.200 0.245 1469.845 0.825 ;
        RECT 1471.415 0.245 1485.965 0.825 ;
        RECT 1487.535 0.245 1489.195 0.825 ;
        RECT 1490.295 0.245 1491.100 0.945 ;
        RECT 1492.200 0.825 1513.195 0.945 ;
        RECT 1492.200 0.245 1493.845 0.825 ;
        RECT 1495.415 0.245 1509.965 0.825 ;
        RECT 1511.535 0.245 1513.195 0.825 ;
        RECT 1514.295 0.245 1515.100 0.945 ;
        RECT 1516.200 0.825 1537.195 0.945 ;
        RECT 1516.200 0.245 1517.845 0.825 ;
        RECT 1519.415 0.245 1533.965 0.825 ;
        RECT 1535.535 0.245 1537.195 0.825 ;
        RECT 1538.295 0.245 1556.020 0.945 ;
      LAYER met4 ;
        RECT 1.565 52.450 1539.815 1638.290 ;
        RECT 1.565 49.990 368.395 52.450 ;
        RECT 380.985 49.990 1539.815 52.450 ;
        RECT 1.565 0.150 1539.815 49.990 ;
      LAYER met5 ;
        RECT 0.000 0.475 1541.380 1637.965 ;
  END
END pixel_4tile_v1
END LIBRARY

